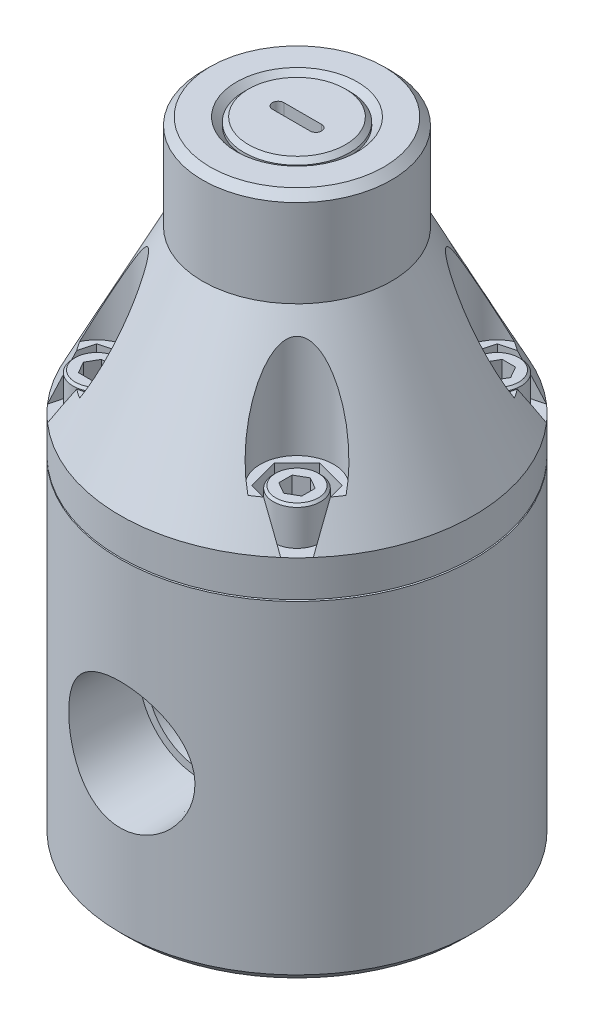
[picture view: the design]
ISO-10303-21;
HEADER;
FILE_DESCRIPTION(('STEP AP214'),'2;1');
FILE_NAME('part.step','',(''),(''),'','','');
FILE_SCHEMA(('AUTOMOTIVE_DESIGN { 1 0 10303 214 1 1 1 1 }'));
ENDSEC;
DATA;
#1=APPLICATION_CONTEXT('core data for automotive mechanical design processes');
#2=APPLICATION_PROTOCOL_DEFINITION('international standard','automotive_design',2000,#1);
#3=PRODUCT_CONTEXT('',#1,'mechanical');
#4=PRODUCT('Part','Part','',(#3));
#5=PRODUCT_RELATED_PRODUCT_CATEGORY('part','',(#4));
#6=PRODUCT_DEFINITION_FORMATION('','',#4);
#7=PRODUCT_DEFINITION_CONTEXT('part definition',#1,'design');
#8=PRODUCT_DEFINITION('design','',#6,#7);
#9=PRODUCT_DEFINITION_SHAPE('','',#8);
#10=(LENGTH_UNIT() NAMED_UNIT(*) SI_UNIT(.MILLI.,.METRE.));
#11=(NAMED_UNIT(*) PLANE_ANGLE_UNIT() SI_UNIT($,.RADIAN.));
#12=(NAMED_UNIT(*) SI_UNIT($,.STERADIAN.) SOLID_ANGLE_UNIT());
#13=UNCERTAINTY_MEASURE_WITH_UNIT(LENGTH_MEASURE(1.E-05),#10,'distance_accuracy_value','');
#14=(GEOMETRIC_REPRESENTATION_CONTEXT(3) GLOBAL_UNCERTAINTY_ASSIGNED_CONTEXT((#13)) GLOBAL_UNIT_ASSIGNED_CONTEXT((#10,
#11,#12)) REPRESENTATION_CONTEXT('',''));
#15=CARTESIAN_POINT('',(0.,0.,0.));
#16=DIRECTION('',(0.,0.,1.));
#17=DIRECTION('',(1.,0.,0.));
#18=AXIS2_PLACEMENT_3D('',#15,#16,#17);
#19=CARTESIAN_POINT('',(0.,62.23,0.));
#20=DIRECTION('',(0.,-1.,0.));
#21=DIRECTION('',(0.,0.,-1.));
#22=AXIS2_PLACEMENT_3D('',#19,#20,#21);
#23=CONICAL_SURFACE('',#22,29.718,0.471096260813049);
#24=CARTESIAN_POINT('',(-22.3373805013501,62.2298,-19.6011992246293));
#25=CARTESIAN_POINT('',(-22.2547645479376,62.7634166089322,-19.2832519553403));
#26=CARTESIAN_POINT('',(-22.1717744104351,63.29612059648,-18.9638646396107));
#27=CARTESIAN_POINT('',(-22.0049530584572,64.3594037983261,-18.3218531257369));
#28=CARTESIAN_POINT('',(-21.9211218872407,64.8899831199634,-17.9992290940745));
#29=CARTESIAN_POINT('',(-21.7525165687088,65.9487768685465,-17.3503519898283));
#30=CARTESIAN_POINT('',(-21.6677424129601,66.4769912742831,-17.0240988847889));
#31=CARTESIAN_POINT('',(-21.4971243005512,67.5307185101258,-16.367475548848));
#32=CARTESIAN_POINT('',(-21.4112802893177,68.0562312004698,-16.0371051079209));
#33=CARTESIAN_POINT('',(-21.3248419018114,68.5802,-15.7044472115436));
#34=B_SPLINE_CURVE_WITH_KNOTS('',3,(#24,#25,#26,#27,#28,#29,#30,#31,#32,#33),.UNSPECIFIED.,.F.,
.F.,(4,2,2,2,4),(0.,1.87988537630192,3.75967455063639,5.63948054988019,7.51938283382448),.UNSPECIFIED.);
#35=CARTESIAN_POINT('',(-22.3373495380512,62.23,-19.6010800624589));
#36=VERTEX_POINT('',#35);
#37=CARTESIAN_POINT('',(-21.324874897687,68.58,-15.7045741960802));
#38=VERTEX_POINT('',#37);
#39=EDGE_CURVE('E627',#36,#38,#34,.T.);
#40=ORIENTED_EDGE('',*,*,#39,.F.);
#41=CARTESIAN_POINT('',(0.,62.23,0.));
#42=DIRECTION('',(0.,-1.,0.));
#43=DIRECTION('',(0.,0.,-1.));
#44=AXIS2_PLACEMENT_3D('',#41,#42,#43);
#45=CIRCLE('',#44,29.718);
#46=CARTESIAN_POINT('',(-22.3373495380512,62.23,19.6010800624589));
#47=VERTEX_POINT('',#46);
#48=EDGE_CURVE('E935',#47,#36,#45,.T.);
#49=ORIENTED_EDGE('',*,*,#48,.F.);
#50=CARTESIAN_POINT('',(-21.3248419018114,68.5802,15.7044472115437));
#51=CARTESIAN_POINT('',(-21.4112802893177,68.0562312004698,16.0371051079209));
#52=CARTESIAN_POINT('',(-21.4971243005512,67.5307185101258,16.367475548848));
#53=CARTESIAN_POINT('',(-21.66774241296,66.4769912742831,17.024098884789));
#54=CARTESIAN_POINT('',(-21.7525165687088,65.9487768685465,17.3503519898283));
#55=CARTESIAN_POINT('',(-21.9211218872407,64.8899831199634,17.9992290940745));
#56=CARTESIAN_POINT('',(-22.0049530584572,64.3594037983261,18.3218531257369));
#57=CARTESIAN_POINT('',(-22.1717744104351,63.29612059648,18.9638646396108));
#58=CARTESIAN_POINT('',(-22.2547645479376,62.7634166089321,19.2832519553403));
#59=CARTESIAN_POINT('',(-22.3373805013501,62.2298,19.6011992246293));
#60=B_SPLINE_CURVE_WITH_KNOTS('',3,(#50,#51,#52,#53,#54,#55,#56,#57,#58,#59),.UNSPECIFIED.,.F.,
.F.,(4,2,2,2,4),(0.,1.87990228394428,3.75970828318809,5.63949745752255,7.51938283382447),.UNSPECIFIED.);
#61=CARTESIAN_POINT('',(-21.324874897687,68.58,15.7045741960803));
#62=VERTEX_POINT('',#61);
#63=EDGE_CURVE('E681',#62,#47,#60,.T.);
#64=ORIENTED_EDGE('',*,*,#63,.F.);
#65=CARTESIAN_POINT('',(0.,68.58,0.));
#66=DIRECTION('',(0.,1.,0.));
#67=DIRECTION('',(0.,0.,1.));
#68=AXIS2_PLACEMENT_3D('',#65,#66,#67);
#69=CIRCLE('',#68,26.4836542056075);
#70=CARTESIAN_POINT('',(-22.3908779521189,68.58,14.1432854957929));
#71=VERTEX_POINT('',#70);
#72=EDGE_CURVE('E1431',#62,#71,#69,.F.);
#73=ORIENTED_EDGE('',*,*,#72,.T.);
#74=CARTESIAN_POINT('',(-22.3909303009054,68.5798,14.143393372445));
#75=CARTESIAN_POINT('',(-22.350304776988,68.7350022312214,14.0596815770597));
#76=CARTESIAN_POINT('',(-22.3081630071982,68.89069928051,13.9776470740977));
#77=CARTESIAN_POINT('',(-22.2210302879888,69.2029732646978,13.8168553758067));
#78=CARTESIAN_POINT('',(-22.1760395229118,69.3595501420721,13.7380979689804));
#79=CARTESIAN_POINT('',(-22.0370947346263,69.8303500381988,13.5066666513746));
#80=CARTESIAN_POINT('',(-21.9391379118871,70.1457572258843,13.3587718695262));
#81=CARTESIAN_POINT('',(-21.7338262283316,70.7787217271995,13.0753567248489));
#82=CARTESIAN_POINT('',(-21.6264783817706,71.0962772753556,12.9398272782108));
#83=CARTESIAN_POINT('',(-21.4032338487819,71.7332404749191,12.6806046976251));
#84=CARTESIAN_POINT('',(-21.2873363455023,72.0526483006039,12.556912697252));
#85=CARTESIAN_POINT('',(-21.0470421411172,72.6946343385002,12.3204109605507));
#86=CARTESIAN_POINT('',(-20.9226003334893,73.0172202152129,12.2076680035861));
#87=CARTESIAN_POINT('',(-20.6663853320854,73.6632945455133,11.9936819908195));
#88=CARTESIAN_POINT('',(-20.5346119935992,73.9867830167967,11.8924391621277));
#89=CARTESIAN_POINT('',(-20.2641447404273,74.6342665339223,11.7013595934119));
#90=CARTESIAN_POINT('',(-20.1254503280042,74.9582616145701,11.6115236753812));
#91=CARTESIAN_POINT('',(-19.8414364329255,75.6062899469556,11.4433041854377));
#92=CARTESIAN_POINT('',(-19.6961171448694,75.9303231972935,11.3649202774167));
#93=CARTESIAN_POINT('',(-19.3211632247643,76.7476954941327,11.1817059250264));
#94=CARTESIAN_POINT('',(-19.0872302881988,77.2408247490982,11.0845248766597));
#95=CARTESIAN_POINT('',(-18.7249280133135,77.9784605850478,10.9599064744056));
#96=CARTESIAN_POINT('',(-18.6022415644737,78.2240315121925,10.9218885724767));
#97=CARTESIAN_POINT('',(-18.3529388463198,78.7141977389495,10.8531925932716));
#98=CARTESIAN_POINT('',(-18.2263228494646,78.9587931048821,10.8225140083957));
#99=CARTESIAN_POINT('',(-17.9690231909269,79.4465771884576,10.7688733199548));
#100=CARTESIAN_POINT('',(-17.8383410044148,79.6897663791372,10.7459084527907));
#101=CARTESIAN_POINT('',(-17.5726008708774,80.1743656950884,10.7081842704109));
#102=CARTESIAN_POINT('',(-17.4375433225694,80.4157759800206,10.693424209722));
#103=CARTESIAN_POINT('',(-17.1627429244,80.8961071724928,10.6727907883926));
#104=CARTESIAN_POINT('',(-17.0230031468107,81.1350295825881,10.6669117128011));
#105=CARTESIAN_POINT('',(-16.7382475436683,81.6097183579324,10.6649433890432));
#106=CARTESIAN_POINT('',(-16.5932325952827,81.8454852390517,10.6688525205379));
#107=CARTESIAN_POINT('',(-16.2968182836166,82.3133650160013,10.6877509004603));
#108=CARTESIAN_POINT('',(-16.1454043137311,82.5454676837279,10.7027669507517));
#109=CARTESIAN_POINT('',(-15.8354539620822,83.0038758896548,10.7457309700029));
#110=CARTESIAN_POINT('',(-15.6769137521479,83.2301782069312,10.7736859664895));
#111=CARTESIAN_POINT('',(-15.3515270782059,83.6741617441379,10.8451251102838));
#112=CARTESIAN_POINT('',(-15.1846866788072,83.8918490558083,10.8885980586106));
#113=CARTESIAN_POINT('',(-14.9269806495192,84.2084557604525,10.9683843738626));
#114=CARTESIAN_POINT('',(-14.839881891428,84.3122892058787,10.997391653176));
#115=CARTESIAN_POINT('',(-14.6629301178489,84.515808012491,11.0609509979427));
#116=CARTESIAN_POINT('',(-14.5730777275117,84.6154943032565,11.0955018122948));
#117=CARTESIAN_POINT('',(-14.3891167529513,84.8109037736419,11.1714874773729));
#118=CARTESIAN_POINT('',(-14.2949676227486,84.9065572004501,11.2130072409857));
#119=CARTESIAN_POINT('',(-14.1034347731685,85.0907355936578,11.3035808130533));
#120=CARTESIAN_POINT('',(-14.0060494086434,85.1792568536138,11.3526385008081));
#121=CARTESIAN_POINT('',(-13.7101223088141,85.429646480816,11.5123405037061));
#122=CARTESIAN_POINT('',(-13.5060546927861,85.5782916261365,11.6361944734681));
#123=CARTESIAN_POINT('',(-13.1996116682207,85.7493306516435,11.8507095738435));
#124=CARTESIAN_POINT('',(-13.0998509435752,85.7971000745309,11.9248690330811));
#125=CARTESIAN_POINT('',(-12.900706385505,85.873763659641,12.0829789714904));
#126=CARTESIAN_POINT('',(-12.8013223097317,85.9026733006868,12.1669213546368));
#127=CARTESIAN_POINT('',(-12.6053038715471,85.9385908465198,12.3437610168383));
#128=CARTESIAN_POINT('',(-12.5086917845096,85.9454540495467,12.4367133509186));
#129=CARTESIAN_POINT('',(-12.3223166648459,85.9359739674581,12.6281475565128));
#130=CARTESIAN_POINT('',(-12.2325552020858,85.9196253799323,12.7266306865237));
#131=CARTESIAN_POINT('',(-12.0684910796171,85.8677160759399,12.9184346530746));
#132=CARTESIAN_POINT('',(-11.9935403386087,85.8336265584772,13.0116153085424));
#133=CARTESIAN_POINT('',(-11.8522698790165,85.7502029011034,13.1975950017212));
#134=CARTESIAN_POINT('',(-11.7859543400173,85.7008614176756,13.290393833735));
#135=CARTESIAN_POINT('',(-11.6163662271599,85.5496530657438,13.5413620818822));
#136=CARTESIAN_POINT('',(-11.5214197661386,85.4357254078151,13.6978402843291));
#137=CARTESIAN_POINT('',(-11.3524385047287,85.1845941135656,14.0032728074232));
#138=CARTESIAN_POINT('',(-11.2784789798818,85.0473094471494,14.1521985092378));
#139=CARTESIAN_POINT('',(-11.1484302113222,84.7600134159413,14.44015441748));
#140=CARTESIAN_POINT('',(-11.0920802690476,84.6102339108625,14.5793027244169));
#141=CARTESIAN_POINT('',(-10.9925096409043,84.3006741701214,14.851149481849));
#142=CARTESIAN_POINT('',(-10.9493023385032,84.1408839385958,14.9838412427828));
#143=CARTESIAN_POINT('',(-10.8736636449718,83.8139640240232,15.2438249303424));
#144=CARTESIAN_POINT('',(-10.8412572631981,83.6468183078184,15.3711037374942));
#145=CARTESIAN_POINT('',(-10.7856662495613,83.307480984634,15.6206584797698));
#146=CARTESIAN_POINT('',(-10.7624784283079,83.1352911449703,15.7429361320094));
#147=CARTESIAN_POINT('',(-10.7205377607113,82.7552655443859,16.0051192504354));
#148=CARTESIAN_POINT('',(-10.7033691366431,82.5466647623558,16.1441638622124));
#149=CARTESIAN_POINT('',(-10.6786273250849,82.125493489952,16.4170496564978));
#150=CARTESIAN_POINT('',(-10.6710565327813,81.9129220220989,16.5508895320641));
#151=CARTESIAN_POINT('',(-10.664422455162,81.4846459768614,16.8140587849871));
#152=CARTESIAN_POINT('',(-10.6653663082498,81.2689389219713,16.9433842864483));
#153=CARTESIAN_POINT('',(-10.674967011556,80.8352423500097,17.1978874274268));
#154=CARTESIAN_POINT('',(-10.6836247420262,80.6172525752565,17.323064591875));
#155=CARTESIAN_POINT('',(-10.7080782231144,80.178919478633,17.5699535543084));
#156=CARTESIAN_POINT('',(-10.7238938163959,79.9585712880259,17.691654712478));
#157=CARTESIAN_POINT('',(-10.7622068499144,79.516512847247,17.9314908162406));
#158=CARTESIAN_POINT('',(-10.7847047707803,79.2948025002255,18.0496255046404));
#159=CARTESIAN_POINT('',(-10.8616544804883,78.628245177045,18.3989144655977));
#160=CARTESIAN_POINT('',(-10.9255713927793,78.1818168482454,18.6250403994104));
#161=CARTESIAN_POINT('',(-11.0664102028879,77.3479438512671,19.0346218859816));
#162=CARTESIAN_POINT('',(-11.1403619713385,76.9607742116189,19.2196861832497));
#163=CARTESIAN_POINT('',(-11.3050181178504,76.1856258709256,19.5805572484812));
#164=CARTESIAN_POINT('',(-11.3957241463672,75.7976470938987,19.7563631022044));
#165=CARTESIAN_POINT('',(-11.5935742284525,75.0216151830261,20.0985507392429));
#166=CARTESIAN_POINT('',(-11.7007221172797,74.6335620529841,20.264930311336));
#167=CARTESIAN_POINT('',(-11.9313879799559,73.8581881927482,20.5877481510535));
#168=CARTESIAN_POINT('',(-12.0549056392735,73.470867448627,20.7441866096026));
#169=CARTESIAN_POINT('',(-12.3163714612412,72.7038997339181,21.0439307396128));
#170=CARTESIAN_POINT('',(-12.4540552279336,72.3242296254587,21.1874073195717));
#171=CARTESIAN_POINT('',(-12.7458005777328,71.5671030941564,21.4629534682));
#172=CARTESIAN_POINT('',(-12.8998598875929,71.1896463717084,21.5950246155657));
#173=CARTESIAN_POINT('',(-13.2250025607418,70.4376533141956,21.8464430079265));
#174=CARTESIAN_POINT('',(-13.396090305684,70.0631177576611,21.9657869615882));
#175=CARTESIAN_POINT('',(-13.6660711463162,69.5043911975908,22.1338540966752));
#176=CARTESIAN_POINT('',(-13.7583155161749,69.3186135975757,22.1880644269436));
#177=CARTESIAN_POINT('',(-13.9473861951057,68.9482602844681,22.2925349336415));
#178=CARTESIAN_POINT('',(-14.044212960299,68.7636846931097,22.3427947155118));
#179=CARTESIAN_POINT('',(-14.1433933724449,68.5798000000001,22.3909303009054));
#180=B_SPLINE_CURVE_WITH_KNOTS('',3,(#74,#75,#76,#77,#78,#79,#80,#81,#82,#83,#84,#85,#86,#87,
#88,#89,#90,#91,#92,#93,#94,#95,#96,#97,#98,#99,#100,#101,#102,#103,#104,#105,#106,#107,#108,
#109,#110,#111,#112,#113,#114,#115,#116,#117,#118,#119,#120,#121,#122,#123,#124,#125,#126,#127,
#128,#129,#130,#131,#132,#133,#134,#135,#136,#137,#138,#139,#140,#141,#142,#143,#144,#145,#146,
#147,#148,#149,#150,#151,#152,#153,#154,#155,#156,#157,#158,#159,#160,#161,#162,#163,#164,#165,
#166,#167,#168,#169,#170,#171,#172,#173,#174,#175,#176,#177,#178,#179),.UNSPECIFIED.,.F.,.F.,(4,
2,2,2,2,2,2,2,2,2,2,2,2,2,2,2,2,2,2,2,2,2,2,2,2,2,2,2,2,2,2,2,2,2,2,2,2,2,2,2,2,2,2,2,2,2,2,2,2,
2,2,2,4),(0.,0.542840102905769,1.08564511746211,2.17085376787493,3.25525867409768,
4.33976732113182,5.43052218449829,6.5212985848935,7.61215354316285,8.70297647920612,
10.3650975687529,11.196398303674,12.027641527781,12.8585866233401,13.6894562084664,
14.5197908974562,15.3499881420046,16.1821952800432,17.014854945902,17.8469149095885,
18.2625409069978,18.6780732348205,19.0990950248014,19.5203342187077,20.354755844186,
20.7529146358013,21.1507462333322,21.5511837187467,21.9517126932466,22.32334462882,
22.6951557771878,23.3381727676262,23.9834677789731,24.6186994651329,25.2545758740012,
25.8919145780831,26.5290325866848,27.2825500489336,28.0362555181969,28.7905929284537,
29.5450164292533,30.3015442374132,31.0581264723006,32.5707579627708,33.8767149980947,
35.1828007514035,36.4891916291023,37.7955574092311,39.0808873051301,40.3660390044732,
41.6515222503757,42.2946005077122,42.9377429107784),.UNSPECIFIED.);
#181=CARTESIAN_POINT('',(-14.1432854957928,68.58,22.390877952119));
#182=VERTEX_POINT('',#181);
#183=EDGE_CURVE('E1425',#71,#182,#180,.T.);
#184=ORIENTED_EDGE('',*,*,#183,.T.);
#185=CARTESIAN_POINT('',(-15.7045741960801,68.58,21.3248748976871));
#186=VERTEX_POINT('',#185);
#187=EDGE_CURVE('E1358',#182,#186,#69,.F.);
#188=ORIENTED_EDGE('',*,*,#187,.T.);
#189=CARTESIAN_POINT('',(-19.6011992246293,62.2298,22.3373805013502));
#190=CARTESIAN_POINT('',(-19.2832519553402,62.7634166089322,22.2547645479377));
#191=CARTESIAN_POINT('',(-18.9638646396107,63.29612059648,22.1717744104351));
#192=CARTESIAN_POINT('',(-18.3218531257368,64.3594037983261,22.0049530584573));
#193=CARTESIAN_POINT('',(-17.9992290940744,64.8899831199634,21.9211218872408));
#194=CARTESIAN_POINT('',(-17.3503519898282,65.9487768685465,21.7525165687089));
#195=CARTESIAN_POINT('',(-17.0240988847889,66.4769912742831,21.6677424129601));
#196=CARTESIAN_POINT('',(-16.3674755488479,67.5307185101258,21.4971243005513));
#197=CARTESIAN_POINT('',(-16.0371051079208,68.0562312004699,21.4112802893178));
#198=CARTESIAN_POINT('',(-15.7044472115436,68.5802,21.3248419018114));
#199=B_SPLINE_CURVE_WITH_KNOTS('',3,(#189,#190,#191,#192,#193,#194,#195,#196,#197,#198),
.UNSPECIFIED.,.F.,.F.,(4,2,2,2,4),(0.,1.87988537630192,3.75967455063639,5.63948054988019,
7.51938283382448),.UNSPECIFIED.);
#200=CARTESIAN_POINT('',(-19.6010800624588,62.23,22.3373495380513));
#201=VERTEX_POINT('',#200);
#202=EDGE_CURVE('E674',#201,#186,#199,.T.);
#203=ORIENTED_EDGE('',*,*,#202,.F.);
#204=CARTESIAN_POINT('',(19.601080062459,62.23,22.3373495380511));
#205=VERTEX_POINT('',#204);
#206=EDGE_CURVE('E948',#205,#201,#45,.T.);
#207=ORIENTED_EDGE('',*,*,#206,.F.);
#208=CARTESIAN_POINT('',(15.7044472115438,68.5802,21.3248419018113));
#209=CARTESIAN_POINT('',(16.037105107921,68.0562312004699,21.4112802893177));
#210=CARTESIAN_POINT('',(16.3674755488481,67.5307185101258,21.4971243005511));
#211=CARTESIAN_POINT('',(17.024098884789,66.4769912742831,21.66774241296));
#212=CARTESIAN_POINT('',(17.3503519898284,65.9487768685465,21.7525165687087));
#213=CARTESIAN_POINT('',(17.9992290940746,64.8899831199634,21.9211218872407));
#214=CARTESIAN_POINT('',(18.321853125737,64.3594037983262,22.0049530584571));
#215=CARTESIAN_POINT('',(18.9638646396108,63.29612059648,22.171774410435));
#216=CARTESIAN_POINT('',(19.2832519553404,62.7634166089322,22.2547645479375));
#217=CARTESIAN_POINT('',(19.6011992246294,62.2298,22.33738050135));
#218=B_SPLINE_CURVE_WITH_KNOTS('',3,(#208,#209,#210,#211,#212,#213,#214,#215,#216,#217),
.UNSPECIFIED.,.F.,.F.,(4,2,2,2,4),(0.,1.87990228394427,3.75970828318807,5.63949745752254,
7.51938283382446),.UNSPECIFIED.);
#219=CARTESIAN_POINT('',(15.7045741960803,68.58,21.3248748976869));
#220=VERTEX_POINT('',#219);
#221=EDGE_CURVE('E712',#220,#205,#218,.T.);
#222=ORIENTED_EDGE('',*,*,#221,.F.);
#223=CARTESIAN_POINT('',(0.,68.58,0.));
#224=DIRECTION('',(0.,1.,0.));
#225=DIRECTION('',(0.,0.,1.));
#226=AXIS2_PLACEMENT_3D('',#223,#224,#225);
#227=CIRCLE('',#226,26.4836542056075);
#228=CARTESIAN_POINT('',(14.143285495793,68.58,22.3908779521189));
#229=VERTEX_POINT('',#228);
#230=EDGE_CURVE('E979',#220,#229,#227,.F.);
#231=ORIENTED_EDGE('',*,*,#230,.T.);
#232=CARTESIAN_POINT('',(14.1433933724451,68.5798,22.3909303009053));
#233=CARTESIAN_POINT('',(14.0596815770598,68.7350022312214,22.3503047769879));
#234=CARTESIAN_POINT('',(13.9776470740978,68.89069928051,22.3081630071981));
#235=CARTESIAN_POINT('',(13.8168553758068,69.2029732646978,22.2210302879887));
#236=CARTESIAN_POINT('',(13.7380979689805,69.3595501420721,22.1760395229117));
#237=CARTESIAN_POINT('',(13.5066666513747,69.8303500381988,22.0370947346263));
#238=CARTESIAN_POINT('',(13.3587718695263,70.1457572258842,21.939137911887));
#239=CARTESIAN_POINT('',(13.075356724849,70.7787217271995,21.7338262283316));
#240=CARTESIAN_POINT('',(12.9398272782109,71.0962772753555,21.6264783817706));
#241=CARTESIAN_POINT('',(12.6806046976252,71.7332404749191,21.4032338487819));
#242=CARTESIAN_POINT('',(12.5569126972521,72.0526483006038,21.2873363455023));
#243=CARTESIAN_POINT('',(12.3204109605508,72.6946343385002,21.0470421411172));
#244=CARTESIAN_POINT('',(12.2076680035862,73.0172202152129,20.9226003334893));
#245=CARTESIAN_POINT('',(11.9936819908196,73.6632945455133,20.6663853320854));
#246=CARTESIAN_POINT('',(11.8924391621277,73.9867830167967,20.5346119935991));
#247=CARTESIAN_POINT('',(11.7013595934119,74.6342665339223,20.2641447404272));
#248=CARTESIAN_POINT('',(11.6115236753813,74.9582616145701,20.1254503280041));
#249=CARTESIAN_POINT('',(11.4433041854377,75.6062899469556,19.8414364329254));
#250=CARTESIAN_POINT('',(11.3649202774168,75.9303231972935,19.6961171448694));
#251=CARTESIAN_POINT('',(11.1817059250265,76.7476954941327,19.3211632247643));
#252=CARTESIAN_POINT('',(11.0845248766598,77.2408247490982,19.0872302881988));
#253=CARTESIAN_POINT('',(10.9599064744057,77.9784605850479,18.7249280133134));
#254=CARTESIAN_POINT('',(10.9218885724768,78.2240315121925,18.6022415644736));
#255=CARTESIAN_POINT('',(10.8531925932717,78.7141977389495,18.3529388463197));
#256=CARTESIAN_POINT('',(10.8225140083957,78.9587931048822,18.2263228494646));
#257=CARTESIAN_POINT('',(10.7688733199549,79.4465771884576,17.9690231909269));
#258=CARTESIAN_POINT('',(10.7459084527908,79.6897663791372,17.8383410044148));
#259=CARTESIAN_POINT('',(10.7081842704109,80.1743656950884,17.5726008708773));
#260=CARTESIAN_POINT('',(10.6934242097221,80.4157759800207,17.4375433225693));
#261=CARTESIAN_POINT('',(10.6727907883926,80.8961071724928,17.1627429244));
#262=CARTESIAN_POINT('',(10.6669117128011,81.1350295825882,17.0230031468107));
#263=CARTESIAN_POINT('',(10.6649433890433,81.6097183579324,16.7382475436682));
#264=CARTESIAN_POINT('',(10.668852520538,81.8454852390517,16.5932325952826));
#265=CARTESIAN_POINT('',(10.6877509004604,82.3133650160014,16.2968182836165));
#266=CARTESIAN_POINT('',(10.7027669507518,82.545467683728,16.1454043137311));
#267=CARTESIAN_POINT('',(10.745730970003,83.0038758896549,15.8354539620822));
#268=CARTESIAN_POINT('',(10.7736859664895,83.2301782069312,15.6769137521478));
#269=CARTESIAN_POINT('',(10.8451251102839,83.6741617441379,15.3515270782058));
#270=CARTESIAN_POINT('',(10.8885980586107,83.8918490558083,15.1846866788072));
#271=CARTESIAN_POINT('',(10.9683843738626,84.2084557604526,14.9269806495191));
#272=CARTESIAN_POINT('',(10.997391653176,84.3122892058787,14.8398818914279));
#273=CARTESIAN_POINT('',(11.0609509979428,84.515808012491,14.6629301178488));
#274=CARTESIAN_POINT('',(11.0955018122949,84.6154943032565,14.5730777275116));
#275=CARTESIAN_POINT('',(11.171487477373,84.8109037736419,14.3891167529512));
#276=CARTESIAN_POINT('',(11.2130072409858,84.9065572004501,14.2949676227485));
#277=CARTESIAN_POINT('',(11.3035808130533,85.0907355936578,14.1034347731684));
#278=CARTESIAN_POINT('',(11.3526385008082,85.1792568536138,14.0060494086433));
#279=CARTESIAN_POINT('',(11.5123405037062,85.4296464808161,13.710122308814));
#280=CARTESIAN_POINT('',(11.6361944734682,85.5782916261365,13.506054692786));
#281=CARTESIAN_POINT('',(11.8507095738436,85.7493306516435,13.1996116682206));
#282=CARTESIAN_POINT('',(11.9248690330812,85.797100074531,13.0998509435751));
#283=CARTESIAN_POINT('',(12.0829789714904,85.873763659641,12.9007063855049));
#284=CARTESIAN_POINT('',(12.1669213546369,85.9026733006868,12.8013223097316));
#285=CARTESIAN_POINT('',(12.3437610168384,85.9385908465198,12.605303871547));
#286=CARTESIAN_POINT('',(12.4367133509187,85.9454540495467,12.5086917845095));
#287=CARTESIAN_POINT('',(12.6281475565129,85.9359739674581,12.3223166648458));
#288=CARTESIAN_POINT('',(12.7266306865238,85.9196253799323,12.2325552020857));
#289=CARTESIAN_POINT('',(12.9184346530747,85.8677160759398,12.068491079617));
#290=CARTESIAN_POINT('',(13.0116153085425,85.8336265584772,11.9935403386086));
#291=CARTESIAN_POINT('',(13.1975950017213,85.7502029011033,11.8522698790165));
#292=CARTESIAN_POINT('',(13.2903938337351,85.7008614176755,11.7859543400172));
#293=CARTESIAN_POINT('',(13.5413620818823,85.5496530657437,11.6163662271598));
#294=CARTESIAN_POINT('',(13.6978402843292,85.435725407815,11.5214197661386));
#295=CARTESIAN_POINT('',(14.0032728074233,85.1845941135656,11.3524385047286));
#296=CARTESIAN_POINT('',(14.1521985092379,85.0473094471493,11.2784789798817));
#297=CARTESIAN_POINT('',(14.4401544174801,84.7600134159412,11.1484302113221));
#298=CARTESIAN_POINT('',(14.579302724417,84.6102339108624,11.0920802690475));
#299=CARTESIAN_POINT('',(14.8511494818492,84.3006741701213,10.9925096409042));
#300=CARTESIAN_POINT('',(14.983841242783,84.1408839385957,10.9493023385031));
#301=CARTESIAN_POINT('',(15.2438249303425,83.813964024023,10.8736636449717));
#302=CARTESIAN_POINT('',(15.3711037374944,83.6468183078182,10.841257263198));
#303=CARTESIAN_POINT('',(15.62065847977,83.3074809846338,10.7856662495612));
#304=CARTESIAN_POINT('',(15.7429361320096,83.1352911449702,10.7624784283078));
#305=CARTESIAN_POINT('',(16.0051192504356,82.7552655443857,10.7205377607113));
#306=CARTESIAN_POINT('',(16.1441638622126,82.5466647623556,10.703369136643));
#307=CARTESIAN_POINT('',(16.417049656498,82.1254934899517,10.6786273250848));
#308=CARTESIAN_POINT('',(16.5508895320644,81.9129220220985,10.6710565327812));
#309=CARTESIAN_POINT('',(16.8140587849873,81.4846459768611,10.6644224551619));
#310=CARTESIAN_POINT('',(16.9433842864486,81.2689389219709,10.6653663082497));
#311=CARTESIAN_POINT('',(17.1978874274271,80.8352423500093,10.674967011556));
#312=CARTESIAN_POINT('',(17.3230645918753,80.6172525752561,10.6836247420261));
#313=CARTESIAN_POINT('',(17.5699535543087,80.1789194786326,10.7080782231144));
#314=CARTESIAN_POINT('',(17.6916547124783,79.9585712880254,10.7238938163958));
#315=CARTESIAN_POINT('',(17.9314908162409,79.5165128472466,10.7622068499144));
#316=CARTESIAN_POINT('',(18.0496255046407,79.294802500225,10.7847047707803));
#317=CARTESIAN_POINT('',(18.398914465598,78.6282451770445,10.8616544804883));
#318=CARTESIAN_POINT('',(18.6250403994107,78.1818168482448,10.9255713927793));
#319=CARTESIAN_POINT('',(19.0346218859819,77.3479438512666,11.0664102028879));
#320=CARTESIAN_POINT('',(19.21968618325,76.9607742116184,11.1403619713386));
#321=CARTESIAN_POINT('',(19.5805572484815,76.1856258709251,11.3050181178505));
#322=CARTESIAN_POINT('',(19.7563631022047,75.7976470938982,11.3957241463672));
#323=CARTESIAN_POINT('',(20.0985507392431,75.0216151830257,11.5935742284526));
#324=CARTESIAN_POINT('',(20.2649303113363,74.6335620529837,11.7007221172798));
#325=CARTESIAN_POINT('',(20.5877481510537,73.8581881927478,11.9313879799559));
#326=CARTESIAN_POINT('',(20.7441866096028,73.4708674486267,12.0549056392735));
#327=CARTESIAN_POINT('',(21.0439307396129,72.7038997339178,12.3163714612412));
#328=CARTESIAN_POINT('',(21.1874073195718,72.3242296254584,12.4540552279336));
#329=CARTESIAN_POINT('',(21.4629534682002,71.5671030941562,12.7458005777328));
#330=CARTESIAN_POINT('',(21.5950246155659,71.1896463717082,12.8998598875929));
#331=CARTESIAN_POINT('',(21.8464430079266,70.4376533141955,13.2250025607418));
#332=CARTESIAN_POINT('',(21.9657869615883,70.0631177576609,13.396090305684));
#333=CARTESIAN_POINT('',(22.1338540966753,69.5043911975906,13.6660711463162));
#334=CARTESIAN_POINT('',(22.1880644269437,69.3186135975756,13.7583155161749));
#335=CARTESIAN_POINT('',(22.2925349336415,68.948260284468,13.9473861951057));
#336=CARTESIAN_POINT('',(22.3427947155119,68.7636846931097,14.0442129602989));
#337=CARTESIAN_POINT('',(22.3909303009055,68.5798,14.1433933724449));
#338=B_SPLINE_CURVE_WITH_KNOTS('',3,(#232,#233,#234,#235,#236,#237,#238,#239,#240,#241,#242,
#243,#244,#245,#246,#247,#248,#249,#250,#251,#252,#253,#254,#255,#256,#257,#258,#259,#260,#261,
#262,#263,#264,#265,#266,#267,#268,#269,#270,#271,#272,#273,#274,#275,#276,#277,#278,#279,#280,
#281,#282,#283,#284,#285,#286,#287,#288,#289,#290,#291,#292,#293,#294,#295,#296,#297,#298,#299,
#300,#301,#302,#303,#304,#305,#306,#307,#308,#309,#310,#311,#312,#313,#314,#315,#316,#317,#318,
#319,#320,#321,#322,#323,#324,#325,#326,#327,#328,#329,#330,#331,#332,#333,#334,#335,#336,#337),
.UNSPECIFIED.,.F.,.F.,(4,2,2,2,2,2,2,2,2,2,2,2,2,2,2,2,2,2,2,2,2,2,2,2,2,2,2,2,2,2,2,2,2,2,2,2,
2,2,2,2,2,2,2,2,2,2,2,2,2,2,2,2,4),(0.,0.542840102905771,1.08564511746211,2.17085376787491,
3.25525867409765,4.3397673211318,5.43052218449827,6.52129858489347,7.61215354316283,
8.7029764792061,10.3650975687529,11.196398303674,12.0276415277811,12.8585866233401,
13.6894562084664,14.5197908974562,15.3499881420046,16.1821952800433,17.0148549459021,
17.8469149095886,18.2625409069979,18.6780732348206,19.0990950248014,19.5203342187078,
20.3547558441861,20.7529146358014,21.1507462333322,21.5511837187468,21.9517126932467,
22.3233446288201,22.6951557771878,23.3381727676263,23.9834677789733,24.618699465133,
25.2545758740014,25.8919145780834,26.529032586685,27.2825500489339,28.0362555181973,
28.7905929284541,29.5450164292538,30.3015442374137,31.0581264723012,32.5707579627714,
33.8767149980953,35.182800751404,36.4891916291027,37.7955574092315,39.0808873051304,
40.3660390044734,41.6515222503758,42.2946005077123,42.9377429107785),.UNSPECIFIED.);
#339=CARTESIAN_POINT('',(22.390877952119,68.58,14.1432854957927));
#340=VERTEX_POINT('',#339);
#341=EDGE_CURVE('E1432',#229,#340,#338,.T.);
#342=ORIENTED_EDGE('',*,*,#341,.T.);
#343=CARTESIAN_POINT('',(21.3248748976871,68.58,15.7045741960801));
#344=VERTEX_POINT('',#343);
#345=EDGE_CURVE('E989',#340,#344,#227,.F.);
#346=ORIENTED_EDGE('',*,*,#345,.T.);
#347=CARTESIAN_POINT('',(22.3373805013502,62.2298,19.6011992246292));
#348=CARTESIAN_POINT('',(22.2547645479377,62.7634166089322,19.2832519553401));
#349=CARTESIAN_POINT('',(22.1717744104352,63.29612059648,18.9638646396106));
#350=CARTESIAN_POINT('',(22.0049530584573,64.3594037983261,18.3218531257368));
#351=CARTESIAN_POINT('',(21.9211218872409,64.8899831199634,17.9992290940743));
#352=CARTESIAN_POINT('',(21.752516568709,65.9487768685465,17.3503519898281));
#353=CARTESIAN_POINT('',(21.6677424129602,66.4769912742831,17.0240988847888));
#354=CARTESIAN_POINT('',(21.4971243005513,67.5307185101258,16.3674755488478));
#355=CARTESIAN_POINT('',(21.4112802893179,68.0562312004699,16.0371051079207));
#356=CARTESIAN_POINT('',(21.3248419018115,68.5802,15.7044472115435));
#357=B_SPLINE_CURVE_WITH_KNOTS('',3,(#347,#348,#349,#350,#351,#352,#353,#354,#355,#356),
.UNSPECIFIED.,.F.,.F.,(4,2,2,2,4),(0.,1.87988537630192,3.75967455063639,5.63948054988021,
7.51938283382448),.UNSPECIFIED.);
#358=CARTESIAN_POINT('',(22.3373495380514,62.23,19.6010800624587));
#359=VERTEX_POINT('',#358);
#360=EDGE_CURVE('E725',#359,#344,#357,.T.);
#361=ORIENTED_EDGE('',*,*,#360,.F.);
#362=CARTESIAN_POINT('',(22.3373495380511,62.23,-19.6010800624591));
#363=VERTEX_POINT('',#362);
#364=EDGE_CURVE('E854',#363,#359,#45,.T.);
#365=ORIENTED_EDGE('',*,*,#364,.F.);
#366=CARTESIAN_POINT('',(21.3248419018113,68.5802,-15.7044472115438));
#367=CARTESIAN_POINT('',(21.4112802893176,68.0562312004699,-16.037105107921));
#368=CARTESIAN_POINT('',(21.4971243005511,67.5307185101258,-16.3674755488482));
#369=CARTESIAN_POINT('',(21.6677424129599,66.4769912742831,-17.0240988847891));
#370=CARTESIAN_POINT('',(21.7525165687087,65.9487768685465,-17.3503519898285));
#371=CARTESIAN_POINT('',(21.9211218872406,64.8899831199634,-17.9992290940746));
#372=CARTESIAN_POINT('',(22.004953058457,64.3594037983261,-18.3218531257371));
#373=CARTESIAN_POINT('',(22.1717744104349,63.29612059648,-18.9638646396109));
#374=CARTESIAN_POINT('',(22.2547645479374,62.7634166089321,-19.2832519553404));
#375=CARTESIAN_POINT('',(22.3373805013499,62.2298,-19.6011992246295));
#376=B_SPLINE_CURVE_WITH_KNOTS('',3,(#366,#367,#368,#369,#370,#371,#372,#373,#374,#375),
.UNSPECIFIED.,.F.,.F.,(4,2,2,2,4),(0.,1.87990228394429,3.75970828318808,5.63949745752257,
7.51938283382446),.UNSPECIFIED.);
#377=CARTESIAN_POINT('',(21.3248748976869,68.58,-15.7045741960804));
#378=VERTEX_POINT('',#377);
#379=EDGE_CURVE('E774',#378,#363,#376,.T.);
#380=ORIENTED_EDGE('',*,*,#379,.F.);
#381=CARTESIAN_POINT('',(0.,68.58,0.));
#382=DIRECTION('',(0.,1.,0.));
#383=DIRECTION('',(0.,0.,1.));
#384=AXIS2_PLACEMENT_3D('',#381,#382,#383);
#385=CIRCLE('',#384,26.4836542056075);
#386=CARTESIAN_POINT('',(22.3908779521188,68.58,-14.1432854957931));
#387=VERTEX_POINT('',#386);
#388=EDGE_CURVE('E977',#378,#387,#385,.F.);
#389=ORIENTED_EDGE('',*,*,#388,.T.);
#390=CARTESIAN_POINT('',(22.3909303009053,68.5798000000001,-14.1433933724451));
#391=CARTESIAN_POINT('',(22.3503047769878,68.7350022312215,-14.0596815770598));
#392=CARTESIAN_POINT('',(22.3081630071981,68.8906992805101,-13.9776470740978));
#393=CARTESIAN_POINT('',(22.2210302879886,69.2029732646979,-13.8168553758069));
#394=CARTESIAN_POINT('',(22.1760395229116,69.3595501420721,-13.7380979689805));
#395=CARTESIAN_POINT('',(22.0370947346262,69.8303500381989,-13.5066666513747));
#396=CARTESIAN_POINT('',(21.939137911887,70.1457572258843,-13.3587718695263));
#397=CARTESIAN_POINT('',(21.7338262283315,70.7787217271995,-13.075356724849));
#398=CARTESIAN_POINT('',(21.6264783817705,71.0962772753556,-12.9398272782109));
#399=CARTESIAN_POINT('',(21.4032338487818,71.7332404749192,-12.6806046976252));
#400=CARTESIAN_POINT('',(21.2873363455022,72.0526483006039,-12.5569126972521));
#401=CARTESIAN_POINT('',(21.0470421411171,72.6946343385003,-12.3204109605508));
#402=CARTESIAN_POINT('',(20.9226003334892,73.017220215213,-12.2076680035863));
#403=CARTESIAN_POINT('',(20.6663853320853,73.6632945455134,-11.9936819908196));
#404=CARTESIAN_POINT('',(20.5346119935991,73.9867830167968,-11.8924391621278));
#405=CARTESIAN_POINT('',(20.2641447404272,74.6342665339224,-11.701359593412));
#406=CARTESIAN_POINT('',(20.1254503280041,74.9582616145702,-11.6115236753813));
#407=CARTESIAN_POINT('',(19.8414364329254,75.6062899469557,-11.4433041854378));
#408=CARTESIAN_POINT('',(19.6961171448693,75.9303231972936,-11.3649202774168));
#409=CARTESIAN_POINT('',(19.3211632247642,76.7476954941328,-11.1817059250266));
#410=CARTESIAN_POINT('',(19.0872302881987,77.2408247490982,-11.0845248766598));
#411=CARTESIAN_POINT('',(18.7249280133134,77.9784605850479,-10.9599064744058));
#412=CARTESIAN_POINT('',(18.6022415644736,78.2240315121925,-10.9218885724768));
#413=CARTESIAN_POINT('',(18.3529388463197,78.7141977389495,-10.8531925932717));
#414=CARTESIAN_POINT('',(18.2263228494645,78.9587931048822,-10.8225140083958));
#415=CARTESIAN_POINT('',(17.9690231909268,79.4465771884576,-10.7688733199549));
#416=CARTESIAN_POINT('',(17.8383410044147,79.6897663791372,-10.7459084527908));
#417=CARTESIAN_POINT('',(17.5726008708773,80.1743656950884,-10.708184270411));
#418=CARTESIAN_POINT('',(17.4375433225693,80.4157759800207,-10.6934242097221));
#419=CARTESIAN_POINT('',(17.1627429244,80.8961071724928,-10.6727907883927));
#420=CARTESIAN_POINT('',(17.0230031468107,81.1350295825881,-10.6669117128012));
#421=CARTESIAN_POINT('',(16.7382475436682,81.6097183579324,-10.6649433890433));
#422=CARTESIAN_POINT('',(16.5932325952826,81.8454852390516,-10.668852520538));
#423=CARTESIAN_POINT('',(16.2968182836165,82.3133650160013,-10.6877509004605));
#424=CARTESIAN_POINT('',(16.1454043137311,82.5454676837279,-10.7027669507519));
#425=CARTESIAN_POINT('',(15.8354539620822,83.0038758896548,-10.745730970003));
#426=CARTESIAN_POINT('',(15.6769137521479,83.2301782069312,-10.7736859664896));
#427=CARTESIAN_POINT('',(15.3515270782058,83.6741617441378,-10.8451251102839));
#428=CARTESIAN_POINT('',(15.1846866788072,83.8918490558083,-10.8885980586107));
#429=CARTESIAN_POINT('',(14.9269806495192,84.2084557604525,-10.9683843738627));
#430=CARTESIAN_POINT('',(14.8398818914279,84.3122892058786,-10.9973916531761));
#431=CARTESIAN_POINT('',(14.6629301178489,84.5158080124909,-11.0609509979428));
#432=CARTESIAN_POINT('',(14.5730777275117,84.6154943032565,-11.0955018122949));
#433=CARTESIAN_POINT('',(14.3891167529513,84.8109037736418,-11.171487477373));
#434=CARTESIAN_POINT('',(14.2949676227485,84.90655720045,-11.2130072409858));
#435=CARTESIAN_POINT('',(14.1034347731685,85.0907355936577,-11.3035808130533));
#436=CARTESIAN_POINT('',(14.0060494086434,85.1792568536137,-11.3526385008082));
#437=CARTESIAN_POINT('',(13.7101223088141,85.429646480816,-11.5123405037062));
#438=CARTESIAN_POINT('',(13.5060546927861,85.5782916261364,-11.6361944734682));
#439=CARTESIAN_POINT('',(13.1996116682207,85.7493306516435,-11.8507095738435));
#440=CARTESIAN_POINT('',(13.0998509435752,85.7971000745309,-11.9248690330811));
#441=CARTESIAN_POINT('',(12.9007063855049,85.873763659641,-12.0829789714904));
#442=CARTESIAN_POINT('',(12.8013223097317,85.9026733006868,-12.1669213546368));
#443=CARTESIAN_POINT('',(12.6053038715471,85.9385908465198,-12.3437610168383));
#444=CARTESIAN_POINT('',(12.5086917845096,85.9454540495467,-12.4367133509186));
#445=CARTESIAN_POINT('',(12.3223166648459,85.9359739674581,-12.6281475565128));
#446=CARTESIAN_POINT('',(12.2325552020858,85.9196253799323,-12.7266306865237));
#447=CARTESIAN_POINT('',(12.0684910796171,85.8677160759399,-12.9184346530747));
#448=CARTESIAN_POINT('',(11.9935403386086,85.8336265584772,-13.0116153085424));
#449=CARTESIAN_POINT('',(11.8522698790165,85.7502029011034,-13.1975950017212));
#450=CARTESIAN_POINT('',(11.7859543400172,85.7008614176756,-13.290393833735));
#451=CARTESIAN_POINT('',(11.6163662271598,85.5496530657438,-13.5413620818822));
#452=CARTESIAN_POINT('',(11.5214197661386,85.4357254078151,-13.6978402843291));
#453=CARTESIAN_POINT('',(11.3524385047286,85.1845941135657,-14.0032728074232));
#454=CARTESIAN_POINT('',(11.2784789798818,85.0473094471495,-14.1521985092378));
#455=CARTESIAN_POINT('',(11.1484302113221,84.7600134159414,-14.4401544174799));
#456=CARTESIAN_POINT('',(11.0920802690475,84.6102339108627,-14.5793027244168));
#457=CARTESIAN_POINT('',(10.9925096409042,84.3006741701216,-14.851149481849));
#458=CARTESIAN_POINT('',(10.9493023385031,84.140883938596,-14.9838412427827));
#459=CARTESIAN_POINT('',(10.8736636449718,83.8139640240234,-15.2438249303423));
#460=CARTESIAN_POINT('',(10.841257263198,83.6468183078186,-15.3711037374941));
#461=CARTESIAN_POINT('',(10.7856662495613,83.3074809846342,-15.6206584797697));
#462=CARTESIAN_POINT('',(10.7624784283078,83.1352911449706,-15.7429361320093));
#463=CARTESIAN_POINT('',(10.7205377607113,82.7552655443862,-16.0051192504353));
#464=CARTESIAN_POINT('',(10.703369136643,82.5466647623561,-16.1441638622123));
#465=CARTESIAN_POINT('',(10.6786273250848,82.1254934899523,-16.4170496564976));
#466=CARTESIAN_POINT('',(10.6710565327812,81.9129220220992,-16.550889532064));
#467=CARTESIAN_POINT('',(10.6644224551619,81.4846459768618,-16.814058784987));
#468=CARTESIAN_POINT('',(10.6653663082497,81.2689389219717,-16.9433842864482));
#469=CARTESIAN_POINT('',(10.6749670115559,80.8352423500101,-17.1978874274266));
#470=CARTESIAN_POINT('',(10.683624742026,80.6172525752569,-17.3230645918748));
#471=CARTESIAN_POINT('',(10.7080782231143,80.1789194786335,-17.5699535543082));
#472=CARTESIAN_POINT('',(10.7238938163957,79.9585712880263,-17.6916547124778));
#473=CARTESIAN_POINT('',(10.7622068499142,79.5165128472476,-17.9314908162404));
#474=CARTESIAN_POINT('',(10.7847047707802,79.2948025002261,-18.0496255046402));
#475=CARTESIAN_POINT('',(10.8616544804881,78.6282451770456,-18.3989144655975));
#476=CARTESIAN_POINT('',(10.9255713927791,78.181816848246,-18.6250403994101));
#477=CARTESIAN_POINT('',(11.0664102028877,77.3479438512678,-19.0346218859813));
#478=CARTESIAN_POINT('',(11.1403619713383,76.9607742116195,-19.2196861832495));
#479=CARTESIAN_POINT('',(11.3050181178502,76.1856258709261,-19.580557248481));
#480=CARTESIAN_POINT('',(11.3957241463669,75.7976470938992,-19.7563631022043));
#481=CARTESIAN_POINT('',(11.5935742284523,75.0216151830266,-20.0985507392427));
#482=CARTESIAN_POINT('',(11.7007221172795,74.6335620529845,-20.264930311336));
#483=CARTESIAN_POINT('',(11.9313879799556,73.8581881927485,-20.5877481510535));
#484=CARTESIAN_POINT('',(12.0549056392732,73.4708674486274,-20.7441866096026));
#485=CARTESIAN_POINT('',(12.3163714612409,72.7038997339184,-21.0439307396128));
#486=CARTESIAN_POINT('',(12.4540552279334,72.3242296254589,-21.1874073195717));
#487=CARTESIAN_POINT('',(12.7458005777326,71.5671030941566,-21.4629534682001));
#488=CARTESIAN_POINT('',(12.8998598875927,71.1896463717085,-21.5950246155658));
#489=CARTESIAN_POINT('',(13.2250025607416,70.4376533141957,-21.8464430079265));
#490=CARTESIAN_POINT('',(13.3960903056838,70.0631177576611,-21.9657869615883));
#491=CARTESIAN_POINT('',(13.666071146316,69.5043911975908,-22.1338540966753));
#492=CARTESIAN_POINT('',(13.7583155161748,69.3186135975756,-22.1880644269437));
#493=CARTESIAN_POINT('',(13.9473861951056,68.948260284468,-22.2925349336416));
#494=CARTESIAN_POINT('',(14.0442129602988,68.7636846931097,-22.3427947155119));
#495=CARTESIAN_POINT('',(14.1433933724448,68.5798,-22.3909303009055));
#496=B_SPLINE_CURVE_WITH_KNOTS('',3,(#390,#391,#392,#393,#394,#395,#396,#397,#398,#399,#400,
#401,#402,#403,#404,#405,#406,#407,#408,#409,#410,#411,#412,#413,#414,#415,#416,#417,#418,#419,
#420,#421,#422,#423,#424,#425,#426,#427,#428,#429,#430,#431,#432,#433,#434,#435,#436,#437,#438,
#439,#440,#441,#442,#443,#444,#445,#446,#447,#448,#449,#450,#451,#452,#453,#454,#455,#456,#457,
#458,#459,#460,#461,#462,#463,#464,#465,#466,#467,#468,#469,#470,#471,#472,#473,#474,#475,#476,
#477,#478,#479,#480,#481,#482,#483,#484,#485,#486,#487,#488,#489,#490,#491,#492,#493,#494,#495),
.UNSPECIFIED.,.F.,.F.,(4,2,2,2,2,2,2,2,2,2,2,2,2,2,2,2,2,2,2,2,2,2,2,2,2,2,2,2,2,2,2,2,2,2,2,2,
2,2,2,2,2,2,2,2,2,2,2,2,2,2,2,2,4),(0.,0.542840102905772,1.08564511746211,2.17085376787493,
3.25525867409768,4.33976732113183,5.4305221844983,6.5212985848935,7.61215354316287,
8.70297647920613,10.3650975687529,11.196398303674,12.027641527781,12.85858662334,
13.6894562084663,14.5197908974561,15.3499881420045,16.1821952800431,17.0148549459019,
17.8469149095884,18.2625409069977,18.6780732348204,19.0990950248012,19.5203342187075,
20.3547558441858,20.7529146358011,21.150746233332,21.5511837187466,21.9517126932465,
22.3233446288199,22.6951557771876,23.338172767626,23.9834677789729,24.6186994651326,
25.2545758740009,25.8919145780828,26.5290325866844,27.2825500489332,28.0362555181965,
28.7905929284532,29.5450164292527,30.3015442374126,31.0581264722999,32.5707579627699,
33.876714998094,35.1828007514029,36.4891916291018,37.7955574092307,39.0808873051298,
40.366039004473,41.6515222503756,42.2946005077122,42.9377429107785),.UNSPECIFIED.);
#497=CARTESIAN_POINT('',(14.1432854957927,68.58,-22.3908779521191));
#498=VERTEX_POINT('',#497);
#499=EDGE_CURVE('E974',#387,#498,#496,.T.);
#500=ORIENTED_EDGE('',*,*,#499,.T.);
#501=CARTESIAN_POINT('',(15.70457419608,68.58,-21.3248748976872));
#502=VERTEX_POINT('',#501);
#503=EDGE_CURVE('E972',#498,#502,#385,.F.);
#504=ORIENTED_EDGE('',*,*,#503,.T.);
#505=CARTESIAN_POINT('',(19.6011992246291,62.2298,-22.3373805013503));
#506=CARTESIAN_POINT('',(19.28325195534,62.7634166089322,-22.2547645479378));
#507=CARTESIAN_POINT('',(18.9638646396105,63.29612059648,-22.1717744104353));
#508=CARTESIAN_POINT('',(18.3218531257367,64.3594037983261,-22.0049530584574));
#509=CARTESIAN_POINT('',(17.9992290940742,64.8899831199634,-21.9211218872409));
#510=CARTESIAN_POINT('',(17.350351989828,65.9487768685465,-21.752516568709));
#511=CARTESIAN_POINT('',(17.0240988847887,66.4769912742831,-21.6677424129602));
#512=CARTESIAN_POINT('',(16.3674755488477,67.5307185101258,-21.4971243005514));
#513=CARTESIAN_POINT('',(16.0371051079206,68.0562312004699,-21.4112802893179));
#514=CARTESIAN_POINT('',(15.7044472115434,68.5802,-21.3248419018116));
#515=B_SPLINE_CURVE_WITH_KNOTS('',3,(#505,#506,#507,#508,#509,#510,#511,#512,#513,#514),
.UNSPECIFIED.,.F.,.F.,(4,2,2,2,4),(0.,1.87988537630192,3.75967455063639,5.63948054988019,
7.51938283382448),.UNSPECIFIED.);
#516=CARTESIAN_POINT('',(19.6010800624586,62.23,-22.3373495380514));
#517=VERTEX_POINT('',#516);
#518=EDGE_CURVE('E767',#517,#502,#515,.T.);
#519=ORIENTED_EDGE('',*,*,#518,.F.);
#520=CARTESIAN_POINT('',(-19.6010800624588,62.23,-22.3373495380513));
#521=VERTEX_POINT('',#520);
#522=EDGE_CURVE('E849',#521,#517,#45,.T.);
#523=ORIENTED_EDGE('',*,*,#522,.F.);
#524=CARTESIAN_POINT('',(-15.7044472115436,68.5802,-21.3248419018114));
#525=CARTESIAN_POINT('',(-16.0371051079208,68.0562312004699,-21.4112802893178));
#526=CARTESIAN_POINT('',(-16.3674755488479,67.5307185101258,-21.4971243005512));
#527=CARTESIAN_POINT('',(-17.0240988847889,66.4769912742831,-21.6677424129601));
#528=CARTESIAN_POINT('',(-17.3503519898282,65.9487768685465,-21.7525165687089));
#529=CARTESIAN_POINT('',(-17.9992290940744,64.8899831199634,-21.9211218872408));
#530=CARTESIAN_POINT('',(-18.3218531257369,64.3594037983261,-22.0049530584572));
#531=CARTESIAN_POINT('',(-18.9638646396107,63.29612059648,-22.1717744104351));
#532=CARTESIAN_POINT('',(-19.2832519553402,62.7634166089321,-22.2547645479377));
#533=CARTESIAN_POINT('',(-19.6011992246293,62.2298,-22.3373805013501));
#534=B_SPLINE_CURVE_WITH_KNOTS('',3,(#524,#525,#526,#527,#528,#529,#530,#531,#532,#533),
.UNSPECIFIED.,.F.,.F.,(4,2,2,2,4),(0.,1.87990228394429,3.75970828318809,5.63949745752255,
7.51938283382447),.UNSPECIFIED.);
#535=CARTESIAN_POINT('',(-15.7045741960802,68.58,-21.3248748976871));
#536=VERTEX_POINT('',#535);
#537=EDGE_CURVE('E613',#536,#521,#534,.T.);
#538=ORIENTED_EDGE('',*,*,#537,.F.);
#539=CARTESIAN_POINT('',(0.,68.58,0.));
#540=DIRECTION('',(0.,1.,0.));
#541=DIRECTION('',(0.,0.,1.));
#542=AXIS2_PLACEMENT_3D('',#539,#540,#541);
#543=CIRCLE('',#542,26.4836542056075);
#544=CARTESIAN_POINT('',(-14.1432854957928,68.58,-22.390877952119));
#545=VERTEX_POINT('',#544);
#546=EDGE_CURVE('E1430',#536,#545,#543,.F.);
#547=ORIENTED_EDGE('',*,*,#546,.T.);
#548=CARTESIAN_POINT('',(-14.1433933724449,68.5798000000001,-22.3909303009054));
#549=CARTESIAN_POINT('',(-14.0596815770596,68.7350022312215,-22.350304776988));
#550=CARTESIAN_POINT('',(-13.9776470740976,68.8906992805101,-22.3081630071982));
#551=CARTESIAN_POINT('',(-13.8168553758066,69.2029732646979,-22.2210302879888));
#552=CARTESIAN_POINT('',(-13.7380979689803,69.3595501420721,-22.1760395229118));
#553=CARTESIAN_POINT('',(-13.5066666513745,69.8303500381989,-22.0370947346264));
#554=CARTESIAN_POINT('',(-13.3587718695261,70.1457572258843,-21.9391379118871));
#555=CARTESIAN_POINT('',(-13.0753567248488,70.7787217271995,-21.7338262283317));
#556=CARTESIAN_POINT('',(-12.9398272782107,71.0962772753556,-21.6264783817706));
#557=CARTESIAN_POINT('',(-12.680604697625,71.7332404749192,-21.4032338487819));
#558=CARTESIAN_POINT('',(-12.5569126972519,72.0526483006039,-21.2873363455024));
#559=CARTESIAN_POINT('',(-12.3204109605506,72.6946343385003,-21.0470421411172));
#560=CARTESIAN_POINT('',(-12.207668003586,73.017220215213,-20.9226003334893));
#561=CARTESIAN_POINT('',(-11.9936819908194,73.6632945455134,-20.6663853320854));
#562=CARTESIAN_POINT('',(-11.8924391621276,73.9867830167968,-20.5346119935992));
#563=CARTESIAN_POINT('',(-11.7013595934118,74.6342665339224,-20.2641447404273));
#564=CARTESIAN_POINT('',(-11.6115236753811,74.9582616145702,-20.1254503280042));
#565=CARTESIAN_POINT('',(-11.4433041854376,75.6062899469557,-19.8414364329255));
#566=CARTESIAN_POINT('',(-11.3649202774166,75.9303231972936,-19.6961171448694));
#567=CARTESIAN_POINT('',(-11.1817059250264,76.7476954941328,-19.3211632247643));
#568=CARTESIAN_POINT('',(-11.0845248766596,77.2408247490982,-19.0872302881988));
#569=CARTESIAN_POINT('',(-10.9599064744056,77.9784605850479,-18.7249280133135));
#570=CARTESIAN_POINT('',(-10.9218885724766,78.2240315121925,-18.6022415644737));
#571=CARTESIAN_POINT('',(-10.8531925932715,78.7141977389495,-18.3529388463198));
#572=CARTESIAN_POINT('',(-10.8225140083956,78.9587931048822,-18.2263228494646));
#573=CARTESIAN_POINT('',(-10.7688733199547,79.4465771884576,-17.9690231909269));
#574=CARTESIAN_POINT('',(-10.7459084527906,79.6897663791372,-17.8383410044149));
#575=CARTESIAN_POINT('',(-10.7081842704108,80.1743656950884,-17.5726008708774));
#576=CARTESIAN_POINT('',(-10.693424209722,80.4157759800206,-17.4375433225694));
#577=CARTESIAN_POINT('',(-10.6727907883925,80.8961071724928,-17.1627429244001));
#578=CARTESIAN_POINT('',(-10.666911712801,81.1350295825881,-17.0230031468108));
#579=CARTESIAN_POINT('',(-10.6649433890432,81.6097183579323,-16.7382475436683));
#580=CARTESIAN_POINT('',(-10.6688525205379,81.8454852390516,-16.5932325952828));
#581=CARTESIAN_POINT('',(-10.6877509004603,82.3133650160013,-16.2968182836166));
#582=CARTESIAN_POINT('',(-10.7027669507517,82.5454676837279,-16.1454043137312));
#583=CARTESIAN_POINT('',(-10.7457309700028,83.0038758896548,-15.8354539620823));
#584=CARTESIAN_POINT('',(-10.7736859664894,83.2301782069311,-15.676913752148));
#585=CARTESIAN_POINT('',(-10.8451251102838,83.6741617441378,-15.351527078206));
#586=CARTESIAN_POINT('',(-10.8885980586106,83.8918490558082,-15.1846866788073));
#587=CARTESIAN_POINT('',(-10.9683843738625,84.2084557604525,-14.9269806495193));
#588=CARTESIAN_POINT('',(-10.9973916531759,84.3122892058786,-14.8398818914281));
#589=CARTESIAN_POINT('',(-11.0609509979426,84.5158080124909,-14.662930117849));
#590=CARTESIAN_POINT('',(-11.0955018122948,84.6154943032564,-14.5730777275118));
#591=CARTESIAN_POINT('',(-11.1714874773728,84.8109037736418,-14.3891167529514));
#592=CARTESIAN_POINT('',(-11.2130072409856,84.90655720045,-14.2949676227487));
#593=CARTESIAN_POINT('',(-11.3035808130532,85.0907355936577,-14.1034347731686));
#594=CARTESIAN_POINT('',(-11.352638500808,85.1792568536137,-14.0060494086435));
#595=CARTESIAN_POINT('',(-11.512340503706,85.429646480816,-13.7101223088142));
#596=CARTESIAN_POINT('',(-11.636194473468,85.5782916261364,-13.5060546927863));
#597=CARTESIAN_POINT('',(-11.8507095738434,85.7493306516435,-13.1996116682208));
#598=CARTESIAN_POINT('',(-11.924869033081,85.7971000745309,-13.0998509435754));
#599=CARTESIAN_POINT('',(-12.0829789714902,85.873763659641,-12.9007063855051));
#600=CARTESIAN_POINT('',(-12.1669213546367,85.9026733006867,-12.8013223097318));
#601=CARTESIAN_POINT('',(-12.3437610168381,85.9385908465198,-12.6053038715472));
#602=CARTESIAN_POINT('',(-12.4367133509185,85.9454540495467,-12.5086917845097));
#603=CARTESIAN_POINT('',(-12.6281475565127,85.9359739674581,-12.322316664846));
#604=CARTESIAN_POINT('',(-12.7266306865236,85.9196253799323,-12.2325552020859));
#605=CARTESIAN_POINT('',(-12.9184346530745,85.8677160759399,-12.0684910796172));
#606=CARTESIAN_POINT('',(-13.0116153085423,85.8336265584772,-11.9935403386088));
#607=CARTESIAN_POINT('',(-13.1975950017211,85.7502029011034,-11.8522698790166));
#608=CARTESIAN_POINT('',(-13.2903938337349,85.7008614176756,-11.7859543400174));
#609=CARTESIAN_POINT('',(-13.5413620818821,85.5496530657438,-11.61636622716));
#610=CARTESIAN_POINT('',(-13.697840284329,85.4357254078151,-11.5214197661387));
#611=CARTESIAN_POINT('',(-14.0032728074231,85.1845941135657,-11.3524385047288));
#612=CARTESIAN_POINT('',(-14.1521985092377,85.0473094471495,-11.2784789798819));
#613=CARTESIAN_POINT('',(-14.4401544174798,84.7600134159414,-11.1484302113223));
#614=CARTESIAN_POINT('',(-14.5793027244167,84.6102339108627,-11.0920802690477));
#615=CARTESIAN_POINT('',(-14.8511494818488,84.3006741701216,-10.9925096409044));
#616=CARTESIAN_POINT('',(-14.9838412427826,84.140883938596,-10.9493023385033));
#617=CARTESIAN_POINT('',(-15.2438249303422,83.8139640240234,-10.8736636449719));
#618=CARTESIAN_POINT('',(-15.371103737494,83.6468183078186,-10.8412572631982));
#619=CARTESIAN_POINT('',(-15.6206584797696,83.3074809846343,-10.7856662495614));
#620=CARTESIAN_POINT('',(-15.7429361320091,83.1352911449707,-10.762478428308));
#621=CARTESIAN_POINT('',(-16.0051192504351,82.7552655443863,-10.7205377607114));
#622=CARTESIAN_POINT('',(-16.1441638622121,82.5466647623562,-10.7033691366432));
#623=CARTESIAN_POINT('',(-16.4170496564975,82.1254934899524,-10.678627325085));
#624=CARTESIAN_POINT('',(-16.5508895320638,81.9129220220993,-10.6710565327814));
#625=CARTESIAN_POINT('',(-16.8140587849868,81.4846459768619,-10.664422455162));
#626=CARTESIAN_POINT('',(-16.943384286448,81.2689389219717,-10.6653663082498));
#627=CARTESIAN_POINT('',(-17.1978874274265,80.8352423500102,-10.674967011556));
#628=CARTESIAN_POINT('',(-17.3230645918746,80.6172525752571,-10.6836247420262));
#629=CARTESIAN_POINT('',(-17.5699535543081,80.1789194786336,-10.7080782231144));
#630=CARTESIAN_POINT('',(-17.6916547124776,79.9585712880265,-10.7238938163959));
#631=CARTESIAN_POINT('',(-17.9314908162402,79.5165128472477,-10.7622068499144));
#632=CARTESIAN_POINT('',(-18.04962550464,79.2948025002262,-10.7847047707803));
#633=CARTESIAN_POINT('',(-18.3989144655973,78.6282451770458,-10.8616544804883));
#634=CARTESIAN_POINT('',(-18.62504039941,78.1818168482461,-10.9255713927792));
#635=CARTESIAN_POINT('',(-19.0346218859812,77.3479438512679,-11.0664102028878));
#636=CARTESIAN_POINT('',(-19.2196861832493,76.9607742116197,-11.1403619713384));
#637=CARTESIAN_POINT('',(-19.5805572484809,76.1856258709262,-11.3050181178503));
#638=CARTESIAN_POINT('',(-19.7563631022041,75.7976470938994,-11.3957241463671));
#639=CARTESIAN_POINT('',(-20.0985507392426,75.0216151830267,-11.5935742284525));
#640=CARTESIAN_POINT('',(-20.2649303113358,74.6335620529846,-11.7007221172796));
#641=CARTESIAN_POINT('',(-20.5877481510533,73.8581881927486,-11.9313879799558));
#642=CARTESIAN_POINT('',(-20.7441866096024,73.4708674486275,-12.0549056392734));
#643=CARTESIAN_POINT('',(-21.0439307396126,72.7038997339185,-12.3163714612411));
#644=CARTESIAN_POINT('',(-21.1874073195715,72.324229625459,-12.4540552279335));
#645=CARTESIAN_POINT('',(-21.4629534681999,71.5671030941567,-12.7458005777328));
#646=CARTESIAN_POINT('',(-21.5950246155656,71.1896463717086,-12.8998598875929));
#647=CARTESIAN_POINT('',(-21.8464430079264,70.4376533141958,-13.2250025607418));
#648=CARTESIAN_POINT('',(-21.9657869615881,70.0631177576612,-13.396090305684));
#649=CARTESIAN_POINT('',(-22.1338540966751,69.5043911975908,-13.6660711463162));
#650=CARTESIAN_POINT('',(-22.1880644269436,69.3186135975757,-13.7583155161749));
#651=CARTESIAN_POINT('',(-22.2925349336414,68.9482602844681,-13.9473861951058));
#652=CARTESIAN_POINT('',(-22.3427947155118,68.7636846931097,-14.044212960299));
#653=CARTESIAN_POINT('',(-22.3909303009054,68.5798000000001,-14.143393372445));
#654=B_SPLINE_CURVE_WITH_KNOTS('',3,(#548,#549,#550,#551,#552,#553,#554,#555,#556,#557,#558,
#559,#560,#561,#562,#563,#564,#565,#566,#567,#568,#569,#570,#571,#572,#573,#574,#575,#576,#577,
#578,#579,#580,#581,#582,#583,#584,#585,#586,#587,#588,#589,#590,#591,#592,#593,#594,#595,#596,
#597,#598,#599,#600,#601,#602,#603,#604,#605,#606,#607,#608,#609,#610,#611,#612,#613,#614,#615,
#616,#617,#618,#619,#620,#621,#622,#623,#624,#625,#626,#627,#628,#629,#630,#631,#632,#633,#634,
#635,#636,#637,#638,#639,#640,#641,#642,#643,#644,#645,#646,#647,#648,#649,#650,#651,#652,#653),
.UNSPECIFIED.,.F.,.F.,(4,2,2,2,2,2,2,2,2,2,2,2,2,2,2,2,2,2,2,2,2,2,2,2,2,2,2,2,2,2,2,2,2,2,2,2,
2,2,2,2,2,2,2,2,2,2,2,2,2,2,2,2,4),(0.,0.542840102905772,1.08564511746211,2.17085376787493,
3.25525867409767,4.33976732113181,5.43052218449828,6.52129858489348,7.61215354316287,
8.70297647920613,10.3650975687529,11.196398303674,12.027641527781,12.85858662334,
13.6894562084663,14.5197908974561,15.3499881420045,16.1821952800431,17.0148549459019,
17.8469149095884,18.2625409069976,18.6780732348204,19.0990950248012,19.5203342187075,
20.3547558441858,20.7529146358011,21.150746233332,21.5511837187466,21.9517126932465,
22.3233446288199,22.6951557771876,23.338172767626,23.9834677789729,24.6186994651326,
25.2545758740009,25.8919145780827,26.5290325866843,27.2825500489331,28.0362555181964,
28.7905929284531,29.5450164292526,30.3015442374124,31.0581264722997,32.5707579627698,
33.8767149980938,35.1828007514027,36.4891916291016,37.7955574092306,39.0808873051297,
40.3660390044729,41.6515222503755,42.294600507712,42.9377429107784),.UNSPECIFIED.);
#655=CARTESIAN_POINT('',(-22.3908779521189,68.58,-14.1432854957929));
#656=VERTEX_POINT('',#655);
#657=EDGE_CURVE('E1400',#545,#656,#654,.T.);
#658=ORIENTED_EDGE('',*,*,#657,.T.);
#659=EDGE_CURVE('E938',#656,#38,#543,.F.);
#660=ORIENTED_EDGE('',*,*,#659,.T.);
#661=EDGE_LOOP('',(#40,#49,#64,#73,#184,#188,#203,#207,#222,#231,#342,#346,#361,#365,#380,#389,
#500,#504,#519,#523,#538,#547,#658,#660));
#662=FACE_BOUND('',#661,.T.);
#663=CARTESIAN_POINT('',(0.,89.408,0.));
#664=DIRECTION('',(0.,-1.,0.));
#665=DIRECTION('',(0.,0.,-1.));
#666=AXIS2_PLACEMENT_3D('',#663,#664,#665);
#667=CIRCLE('',#666,15.875);
#668=CARTESIAN_POINT('',(0.,89.408,-15.875));
#669=VERTEX_POINT('',#668);
#670=EDGE_CURVE('E846',#669,#669,#667,.T.);
#671=ORIENTED_EDGE('',*,*,#670,.T.);
#672=EDGE_LOOP('',(#671));
#673=FACE_BOUND('',#672,.T.);
#674=ADVANCED_FACE('F31',(#662,#673),#23,.T.);
#675=CARTESIAN_POINT('',(0.,105.41,0.));
#676=DIRECTION('',(0.,-1.,0.));
#677=DIRECTION('',(0.,0.,-1.));
#678=AXIS2_PLACEMENT_3D('',#675,#676,#677);
#679=CYLINDRICAL_SURFACE('',#678,29.718);
#680=CARTESIAN_POINT('',(0.,1.52399999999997,0.));
#681=DIRECTION('',(0.,1.,0.));
#682=DIRECTION('',(0.,0.,1.));
#683=AXIS2_PLACEMENT_3D('',#680,#681,#682);
#684=CIRCLE('',#683,29.718);
#685=CARTESIAN_POINT('',(0.,1.52399999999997,29.718));
#686=VERTEX_POINT('',#685);
#687=EDGE_CURVE('E1056',#686,#686,#684,.T.);
#688=ORIENTED_EDGE('',*,*,#687,.T.);
#689=EDGE_LOOP('',(#688));
#690=FACE_BOUND('',#689,.T.);
#691=CARTESIAN_POINT('',(-7.85615249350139,20.2665766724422,-28.6607814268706));
#692=CARTESIAN_POINT('',(-7.65712208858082,20.0459360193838,-28.7153371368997));
#693=CARTESIAN_POINT('',(-7.4488859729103,19.8336774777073,-28.7701860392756));
#694=CARTESIAN_POINT('',(-7.01523925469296,19.4272434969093,-28.8789872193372));
#695=CARTESIAN_POINT('',(-6.7898288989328,19.2330677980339,-28.9329395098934));
#696=CARTESIAN_POINT('',(-6.32315712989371,18.8640818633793,-29.0384990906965));
#697=CARTESIAN_POINT('',(-6.08189568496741,18.689271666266,-29.0901063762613));
#698=CARTESIAN_POINT('',(-5.58505684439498,18.3603278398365,-29.189566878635));
#699=CARTESIAN_POINT('',(-5.32948479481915,18.2061865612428,-29.2374214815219));
#700=CARTESIAN_POINT('',(-4.80487780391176,17.9193486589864,-29.3282065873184));
#701=CARTESIAN_POINT('',(-4.53581076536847,17.7867066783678,-29.3711244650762));
#702=CARTESIAN_POINT('',(-3.98658729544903,17.5444751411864,-29.4506982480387));
#703=CARTESIAN_POINT('',(-3.70643082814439,17.4348856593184,-29.4873541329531));
#704=CARTESIAN_POINT('',(-3.13708182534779,17.2398112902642,-29.5533473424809));
#705=CARTESIAN_POINT('',(-2.84789163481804,17.1543202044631,-29.5826865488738));
#706=CARTESIAN_POINT('',(-2.26258385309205,17.008271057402,-29.6331992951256));
#707=CARTESIAN_POINT('',(-1.96646656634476,16.9477119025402,-29.6543731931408));
#708=CARTESIAN_POINT('',(-1.3821546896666,16.8541726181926,-29.6872225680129));
#709=CARTESIAN_POINT('',(-1.09414803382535,16.8201432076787,-29.6992588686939));
#710=CARTESIAN_POINT('',(-0.516084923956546,16.7759074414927,-29.7149250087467));
#711=CARTESIAN_POINT('',(-0.226028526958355,16.7657004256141,-29.718555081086));
#712=CARTESIAN_POINT('',(0.353873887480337,16.7692146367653,-29.7173074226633));
#713=CARTESIAN_POINT('',(0.643719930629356,16.7829321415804,-29.7124310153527));
#714=CARTESIAN_POINT('',(1.22103534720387,16.8341457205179,-29.6943092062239));
#715=CARTESIAN_POINT('',(1.50850475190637,16.8716414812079,-29.68106391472));
#716=CARTESIAN_POINT('',(2.06928409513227,16.9683662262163,-29.6471554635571));
#717=CARTESIAN_POINT('',(2.34274450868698,17.0268191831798,-29.6267576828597));
#718=CARTESIAN_POINT('',(2.88359361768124,17.1650314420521,-29.5790147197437));
#719=CARTESIAN_POINT('',(3.15098248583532,17.2447901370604,-29.5516697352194));
#720=CARTESIAN_POINT('',(3.67795466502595,17.4249187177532,-29.490719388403));
#721=CARTESIAN_POINT('',(3.93753866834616,17.5252867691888,-29.4571145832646));
#722=CARTESIAN_POINT('',(4.4474483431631,17.7458715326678,-29.3844531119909));
#723=CARTESIAN_POINT('',(4.69777045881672,17.8660957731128,-29.3453943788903));
#724=CARTESIAN_POINT('',(5.19505086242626,18.1294068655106,-29.2615185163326));
#725=CARTESIAN_POINT('',(5.44167732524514,18.2730761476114,-29.2165627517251));
#726=CARTESIAN_POINT('',(5.92213668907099,18.5795185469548,-29.1229763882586));
#727=CARTESIAN_POINT('',(6.15596514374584,18.7422982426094,-29.0743445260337));
#728=CARTESIAN_POINT('',(6.60948160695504,19.0858614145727,-28.9746129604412));
#729=CARTESIAN_POINT('',(6.82916780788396,19.2666471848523,-28.9235129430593));
#730=CARTESIAN_POINT('',(7.25318857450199,19.6450937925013,-28.8201043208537));
#731=CARTESIAN_POINT('',(7.45752256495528,19.8427552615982,-28.7677956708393));
#732=CARTESIAN_POINT('',(7.86066679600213,20.2652712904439,-28.6603446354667));
#733=CARTESIAN_POINT('',(8.05853452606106,20.4910274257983,-28.6052067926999));
#734=CARTESIAN_POINT('',(8.4346253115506,20.9585947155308,-28.4965775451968));
#735=CARTESIAN_POINT('',(8.61285462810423,21.2004007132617,-28.4430856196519));
#736=CARTESIAN_POINT('',(8.94864434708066,21.698776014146,-28.3392342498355));
#737=CARTESIAN_POINT('',(9.10619506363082,21.955352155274,-28.288876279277));
#738=CARTESIAN_POINT('',(9.39933251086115,22.4814601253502,-28.1928335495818));
#739=CARTESIAN_POINT('',(9.53492829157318,22.7509865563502,-28.1471468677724));
#740=CARTESIAN_POINT('',(9.78379719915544,23.3027621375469,-28.0616152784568));
#741=CARTESIAN_POINT('',(9.8969522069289,23.5850694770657,-28.0218015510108));
#742=CARTESIAN_POINT('',(10.0990649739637,24.1591535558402,-27.9495964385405));
#743=CARTESIAN_POINT('',(10.1880225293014,24.4509303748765,-27.9172051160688));
#744=CARTESIAN_POINT('',(10.3408444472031,25.0416664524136,-27.8609601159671));
#745=CARTESIAN_POINT('',(10.4047193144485,25.3406226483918,-27.8371028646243));
#746=CARTESIAN_POINT('',(10.5067576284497,25.9434799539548,-27.7987509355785));
#747=CARTESIAN_POINT('',(10.5449225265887,26.2473807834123,-27.7842557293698));
#748=CARTESIAN_POINT('',(10.5937616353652,26.8410408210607,-27.7656689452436));
#749=CARTESIAN_POINT('',(10.605817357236,27.1306708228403,-27.7610546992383));
#750=CARTESIAN_POINT('',(10.6064476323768,27.7099540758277,-27.7608140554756));
#751=CARTESIAN_POINT('',(10.5950230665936,27.9996073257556,-27.7651873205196));
#752=CARTESIAN_POINT('',(10.5488110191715,28.5767481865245,-27.7827773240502));
#753=CARTESIAN_POINT('',(10.5140251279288,28.8642359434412,-27.7959934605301));
#754=CARTESIAN_POINT('',(10.421435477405,29.4349587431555,-27.8308398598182));
#755=CARTESIAN_POINT('',(10.3636316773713,29.7181937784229,-27.8524701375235));
#756=CARTESIAN_POINT('',(10.2271486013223,30.2719313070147,-27.9028692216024));
#757=CARTESIAN_POINT('',(10.1489826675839,30.5425767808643,-27.9314614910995));
#758=CARTESIAN_POINT('',(9.97182944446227,31.0762719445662,-27.9951959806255));
#759=CARTESIAN_POINT('',(9.87283479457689,31.3393189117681,-28.0303405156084));
#760=CARTESIAN_POINT('',(9.65480789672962,31.8561278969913,-28.1061829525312));
#761=CARTESIAN_POINT('',(9.53577608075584,32.1098901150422,-28.1468807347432));
#762=CARTESIAN_POINT('',(9.27850647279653,32.6067091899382,-28.2327332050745));
#763=CARTESIAN_POINT('',(9.14026731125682,32.8497652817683,-28.2778882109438));
#764=CARTESIAN_POINT('',(8.83859079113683,33.3349100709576,-28.3736678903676));
#765=CARTESIAN_POINT('',(8.67427839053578,33.5764239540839,-28.4244494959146));
#766=CARTESIAN_POINT('',(8.32665356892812,34.0448622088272,-28.5282186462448));
#767=CARTESIAN_POINT('',(8.14334067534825,34.2717862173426,-28.5812062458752));
#768=CARTESIAN_POINT('',(7.75876512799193,34.7097930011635,-28.6879925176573));
#769=CARTESIAN_POINT('',(7.55749731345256,34.9208711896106,-28.7417914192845));
#770=CARTESIAN_POINT('',(7.13822296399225,35.3258509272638,-28.8487798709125));
#771=CARTESIAN_POINT('',(6.92021667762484,35.5197527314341,-28.9019694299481));
#772=CARTESIAN_POINT('',(6.45929676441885,35.8968536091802,-29.0085374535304));
#773=CARTESIAN_POINT('',(6.21572442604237,36.079272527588,-29.0618318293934));
#774=CARTESIAN_POINT('',(5.71336110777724,36.42275081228,-29.1647515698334));
#775=CARTESIAN_POINT('',(5.45457598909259,36.5838183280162,-29.2143783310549));
#776=CARTESIAN_POINT('',(4.92335444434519,36.8833936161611,-29.3085800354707));
#777=CARTESIAN_POINT('',(4.65091730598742,37.0219002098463,-29.3531547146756));
#778=CARTESIAN_POINT('',(4.0942712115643,37.275117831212,-29.4359580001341));
#779=CARTESIAN_POINT('',(3.81006275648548,37.3898298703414,-29.4741868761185));
#780=CARTESIAN_POINT('',(3.2401694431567,37.5914480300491,-29.54218704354));
#781=CARTESIAN_POINT('',(2.95475677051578,37.6790525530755,-29.5721680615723));
#782=CARTESIAN_POINT('',(2.37685200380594,37.8299064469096,-29.6242173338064));
#783=CARTESIAN_POINT('',(2.08436001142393,37.8931561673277,-29.6462857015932));
#784=CARTESIAN_POINT('',(1.49464909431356,37.99462391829,-29.6818593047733));
#785=CARTESIAN_POINT('',(1.19743179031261,38.0328503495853,-29.6953674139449));
#786=CARTESIAN_POINT('',(0.600556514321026,38.0838878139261,-29.713431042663));
#787=CARTESIAN_POINT('',(0.300898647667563,38.0966999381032,-29.7179869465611));
#788=CARTESIAN_POINT('',(-0.281947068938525,38.096770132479,-29.7180122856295));
#789=CARTESIAN_POINT('',(-0.565135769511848,38.0853927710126,-29.7139669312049));
#790=CARTESIAN_POINT('',(-1.1294453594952,38.0399317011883,-29.6978710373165));
#791=CARTESIAN_POINT('',(-1.41056633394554,38.0058489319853,-29.6858208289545));
#792=CARTESIAN_POINT('',(-1.96872638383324,37.9153106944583,-29.6540348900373));
#793=CARTESIAN_POINT('',(-2.24576557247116,37.8588558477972,-29.6342993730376));
#794=CARTESIAN_POINT('',(-2.79385992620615,37.7241019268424,-29.5876583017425));
#795=CARTESIAN_POINT('',(-3.06491500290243,37.6458025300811,-29.5607526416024));
#796=CARTESIAN_POINT('',(-3.59825216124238,37.4683865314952,-29.500573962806));
#797=CARTESIAN_POINT('',(-3.86056317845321,37.3693486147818,-29.4673250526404));
#798=CARTESIAN_POINT('',(-4.37593704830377,37.1510568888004,-29.3952110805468));
#799=CARTESIAN_POINT('',(-4.62899655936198,37.031795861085,-29.3563440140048));
#800=CARTESIAN_POINT('',(-5.12428986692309,36.7739905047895,-29.2739510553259));
#801=CARTESIAN_POINT('',(-5.36652380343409,36.6354464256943,-29.2304252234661));
#802=CARTESIAN_POINT('',(-5.83884689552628,36.3400342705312,-29.1397534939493));
#803=CARTESIAN_POINT('',(-6.06893518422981,36.1831648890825,-29.0926073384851));
#804=CARTESIAN_POINT('',(-6.52722679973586,35.8436007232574,-28.9933198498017));
#805=CARTESIAN_POINT('',(-6.7547255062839,35.6599930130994,-28.941046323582));
#806=CARTESIAN_POINT('',(-7.19364342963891,35.2748427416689,-28.8350828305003));
#807=CARTESIAN_POINT('',(-7.4050621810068,35.0732996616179,-28.7813928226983));
#808=CARTESIAN_POINT('',(-7.81067832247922,34.6534507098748,-28.6739753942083));
#809=CARTESIAN_POINT('',(-8.00487021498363,34.4351395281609,-28.6202479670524));
#810=CARTESIAN_POINT('',(-8.37481066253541,33.9831027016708,-28.5141912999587));
#811=CARTESIAN_POINT('',(-8.55055951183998,33.7493773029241,-28.4618620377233));
#812=CARTESIAN_POINT('',(-8.8891678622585,33.258223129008,-28.3579765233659));
#813=CARTESIAN_POINT('',(-9.05123108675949,33.0002202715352,-28.306534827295));
#814=CARTESIAN_POINT('',(-9.35298806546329,32.4707399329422,-28.2082668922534));
#815=CARTESIAN_POINT('',(-9.49269043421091,32.1992676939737,-28.1614388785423));
#816=CARTESIAN_POINT('',(-9.74867898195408,31.6445492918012,-28.0738507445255));
#817=CARTESIAN_POINT('',(-9.86496546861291,31.3613032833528,-28.0330905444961));
#818=CARTESIAN_POINT('',(-10.0730862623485,30.7850245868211,-27.9589820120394));
#819=CARTESIAN_POINT('',(-10.164921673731,30.4919923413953,-27.9256333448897));
#820=CARTESIAN_POINT('',(-10.3208696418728,29.907250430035,-27.86836683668));
#821=CARTESIAN_POINT('',(-10.3857324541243,29.6157657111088,-27.844195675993));
#822=CARTESIAN_POINT('',(-10.4909749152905,29.0278123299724,-27.8047143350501));
#823=CARTESIAN_POINT('',(-10.5313550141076,28.73134375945,-27.7894039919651));
#824=CARTESIAN_POINT('',(-10.5871996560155,28.1358399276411,-27.7681764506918));
#825=CARTESIAN_POINT('',(-10.6026731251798,27.8368056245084,-27.7622558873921));
#826=CARTESIAN_POINT('',(-10.6085644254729,27.2384585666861,-27.7600053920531));
#827=CARTESIAN_POINT('',(-10.5989830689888,26.9391458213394,-27.7636751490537));
#828=CARTESIAN_POINT('',(-10.556017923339,26.3581211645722,-27.7800376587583));
#829=CARTESIAN_POINT('',(-10.5238943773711,26.0763015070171,-27.7922525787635));
#830=CARTESIAN_POINT('',(-10.4375304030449,25.5165639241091,-27.8248020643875));
#831=CARTESIAN_POINT('',(-10.3832910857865,25.2386458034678,-27.8451362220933));
#832=CARTESIAN_POINT('',(-10.2531692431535,24.6885142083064,-27.8933119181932));
#833=CARTESIAN_POINT('',(-10.177280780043,24.4163023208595,-27.9211555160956));
#834=CARTESIAN_POINT('',(-10.0045082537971,23.8794008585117,-27.9835266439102));
#835=CARTESIAN_POINT('',(-9.90762230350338,23.6147119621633,-28.018054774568));
#836=CARTESIAN_POINT('',(-9.68381651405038,23.070672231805,-28.0962368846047));
#837=CARTESIAN_POINT('',(-9.55496000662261,22.7921951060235,-28.1404367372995));
#838=CARTESIAN_POINT('',(-9.27422460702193,22.2480367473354,-28.2342020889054));
#839=CARTESIAN_POINT('',(-9.12234385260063,21.9823565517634,-28.2837680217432));
#840=CARTESIAN_POINT('',(-8.79671166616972,21.4654965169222,-28.3867317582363));
#841=CARTESIAN_POINT('',(-8.62295725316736,21.2143186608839,-28.4401300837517));
#842=CARTESIAN_POINT('',(-8.25475219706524,20.7280097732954,-28.5491761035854));
#843=CARTESIAN_POINT('',(-8.06029467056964,20.4928841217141,-28.6048245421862));
#844=CARTESIAN_POINT('',(-7.85615249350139,20.2665766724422,-28.6607814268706));
#845=B_SPLINE_CURVE_WITH_KNOTS('',3,(#691,#692,#693,#694,#695,#696,#697,#698,#699,#700,#701,
#702,#703,#704,#705,#706,#707,#708,#709,#710,#711,#712,#713,#714,#715,#716,#717,#718,#719,#720,
#721,#722,#723,#724,#725,#726,#727,#728,#729,#730,#731,#732,#733,#734,#735,#736,#737,#738,#739,
#740,#741,#742,#743,#744,#745,#746,#747,#748,#749,#750,#751,#752,#753,#754,#755,#756,#757,#758,
#759,#760,#761,#762,#763,#764,#765,#766,#767,#768,#769,#770,#771,#772,#773,#774,#775,#776,#777,
#778,#779,#780,#781,#782,#783,#784,#785,#786,#787,#788,#789,#790,#791,#792,#793,#794,#795,#796,
#797,#798,#799,#800,#801,#802,#803,#804,#805,#806,#807,#808,#809,#810,#811,#812,#813,#814,#815,
#816,#817,#818,#819,#820,#821,#822,#823,#824,#825,#826,#827,#828,#829,#830,#831,#832,#833,#834,
#835,#836,#837,#838,#839,#840,#841,#842,#843,#844),.UNSPECIFIED.,.T.,.F.,(4,2,2,2,2,2,2,2,2,2,2,
2,2,2,2,2,2,2,2,2,2,2,2,2,2,2,2,2,2,2,2,2,2,2,2,2,2,2,2,2,2,2,2,2,2,2,2,2,2,2,2,2,2,2,2,2,2,2,2,
2,2,2,2,2,2,2,2,2,2,2,2,2,2,2,2,2,4),(0.,0.906072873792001,1.8121327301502,2.71819439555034,
3.62391980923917,4.53191230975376,5.43990775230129,6.34766942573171,7.25539127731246,
8.12507804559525,8.99474071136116,9.86426808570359,10.7337839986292,11.5739601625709,
12.4141123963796,13.2541898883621,14.0945866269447,14.9604511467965,15.826614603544,
16.6928885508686,17.5591949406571,18.4737819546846,19.3880765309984,20.3027978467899,
21.2171411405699,22.1361763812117,23.0552193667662,23.9738770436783,24.8924828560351,
25.7611573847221,26.6297993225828,27.4983821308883,28.3669664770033,29.215476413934,
30.0642867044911,30.9130786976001,31.7619312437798,32.6504093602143,33.5389095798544,
34.4276660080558,35.3164092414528,36.2421030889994,37.1674425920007,38.0928304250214,
39.0181789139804,39.9171937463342,40.8161956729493,41.7148956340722,42.613557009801,
43.4628719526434,44.312151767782,45.1614079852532,46.0106767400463,46.8567798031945,
47.7031855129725,48.549580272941,49.3960353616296,50.2859932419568,51.1759768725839,
52.0662435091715,52.9564959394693,53.8823420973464,54.8078307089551,55.7333071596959,
56.6587418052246,57.5563624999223,58.4539666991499,59.3512491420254,60.2485024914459,
61.0992213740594,61.9498975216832,62.8008072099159,63.6517934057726,64.5806255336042,
65.5095328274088,66.4385668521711,67.3679107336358),.UNSPECIFIED.);
#846=CARTESIAN_POINT('',(-7.85615249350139,20.2665766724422,-28.6607814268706));
#847=VERTEX_POINT('',#846);
#848=EDGE_CURVE('E873',#847,#847,#845,.T.);
#849=ORIENTED_EDGE('',*,*,#848,.T.);
#850=EDGE_LOOP('',(#849));
#851=FACE_BOUND('',#850,.T.);
#852=CARTESIAN_POINT('',(-7.85615249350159,20.2665766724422,28.6607814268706));
#853=CARTESIAN_POINT('',(-8.05440487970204,20.4863542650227,28.6064390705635));
#854=CARTESIAN_POINT('',(-8.24351690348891,20.7144413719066,28.5523893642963));
#855=CARTESIAN_POINT('',(-8.60230043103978,21.1858739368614,28.446352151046));
#856=CARTESIAN_POINT('',(-8.77197245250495,21.4292189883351,28.3943645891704));
#857=CARTESIAN_POINT('',(-9.0907466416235,21.929701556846,28.2939178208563));
#858=CARTESIAN_POINT('',(-9.23985026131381,22.1868380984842,28.2454583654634));
#859=CARTESIAN_POINT('',(-9.51637581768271,22.7132509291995,28.1534962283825));
#860=CARTESIAN_POINT('',(-9.64380576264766,22.9825226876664,28.1099917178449));
#861=CARTESIAN_POINT('',(-9.8763493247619,23.5323041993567,28.0291358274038));
#862=CARTESIAN_POINT('',(-9.98140246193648,23.8128420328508,27.991801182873));
#863=CARTESIAN_POINT('',(-10.1678372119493,24.3825604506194,27.9246207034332));
#864=CARTESIAN_POINT('',(-10.2492188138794,24.6717410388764,27.894774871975));
#865=CARTESIAN_POINT('',(-10.3875092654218,25.2565510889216,27.8435741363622));
#866=CARTESIAN_POINT('',(-10.4444253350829,25.5521786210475,27.8222167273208));
#867=CARTESIAN_POINT('',(-10.5332319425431,26.147683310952,27.7887173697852));
#868=CARTESIAN_POINT('',(-10.5651235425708,26.4475602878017,27.7765750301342));
#869=CARTESIAN_POINT('',(-10.6027218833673,27.0363134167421,27.762243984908));
#870=CARTESIAN_POINT('',(-10.6094885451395,27.325112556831,27.7596524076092));
#871=CARTESIAN_POINT('',(-10.599711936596,27.902252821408,27.7633870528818));
#872=CARTESIAN_POINT('',(-10.5831693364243,28.1905939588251,27.7697130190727));
#873=CARTESIAN_POINT('',(-10.5269416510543,28.7646703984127,27.7910763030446));
#874=CARTESIAN_POINT('',(-10.4872572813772,29.0504057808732,27.8061133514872));
#875=CARTESIAN_POINT('',(-10.3851323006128,29.6172150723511,27.8444162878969));
#876=CARTESIAN_POINT('',(-10.3226916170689,29.8982889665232,27.8676822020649));
#877=CARTESIAN_POINT('',(-10.1770024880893,30.4486440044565,27.9212113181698));
#878=CARTESIAN_POINT('',(-10.0941635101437,30.7180473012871,27.9513360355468));
#879=CARTESIAN_POINT('',(-9.90777687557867,31.2488829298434,28.0179455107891));
#880=CARTESIAN_POINT('',(-9.80422188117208,31.5103123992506,28.0544325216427));
#881=CARTESIAN_POINT('',(-9.57720952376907,32.0235402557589,28.1327387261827));
#882=CARTESIAN_POINT('',(-9.45375244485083,32.2753387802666,28.1745578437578));
#883=CARTESIAN_POINT('',(-9.18778347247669,32.7679059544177,28.2624090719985));
#884=CARTESIAN_POINT('',(-9.04527023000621,33.0086738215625,28.3084414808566));
#885=CARTESIAN_POINT('',(-8.73467232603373,33.4893503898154,28.4058582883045));
#886=CARTESIAN_POINT('',(-8.56567771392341,33.7286407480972,28.4573943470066));
#887=CARTESIAN_POINT('',(-8.20880040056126,34.1922479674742,28.562382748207));
#888=CARTESIAN_POINT('',(-8.02091719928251,34.4165644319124,28.6158351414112));
#889=CARTESIAN_POINT('',(-7.62733393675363,34.8489716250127,28.7232469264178));
#890=CARTESIAN_POINT('',(-7.42162886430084,35.0570577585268,28.7772064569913));
#891=CARTESIAN_POINT('',(-6.99363962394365,35.4556679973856,28.8842029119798));
#892=CARTESIAN_POINT('',(-6.77135576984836,35.6461924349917,28.9372398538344));
#893=CARTESIAN_POINT('',(-6.30257497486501,36.0154674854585,29.0430198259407));
#894=CARTESIAN_POINT('',(-6.055474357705,36.1934788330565,29.0956723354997));
#895=CARTESIAN_POINT('',(-5.54639100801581,36.5278427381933,29.1969928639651));
#896=CARTESIAN_POINT('',(-5.28441408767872,36.6842036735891,29.2456624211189));
#897=CARTESIAN_POINT('',(-4.74719064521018,36.9740730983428,29.3376543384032));
#898=CARTESIAN_POINT('',(-4.47194379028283,37.1075810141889,29.3809765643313));
#899=CARTESIAN_POINT('',(-3.91010018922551,37.3505335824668,29.461010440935));
#900=CARTESIAN_POINT('',(-3.62350395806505,37.4599793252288,29.4977223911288));
#901=CARTESIAN_POINT('',(-3.05038221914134,37.650643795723,29.562394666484));
#902=CARTESIAN_POINT('',(-2.76414686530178,37.7326524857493,29.590597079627));
#903=CARTESIAN_POINT('',(-2.18512234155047,37.8723094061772,29.6389802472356));
#904=CARTESIAN_POINT('',(-1.89233328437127,37.9299580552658,29.6591611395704));
#905=CARTESIAN_POINT('',(-1.30255918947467,38.0202767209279,29.6909084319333));
#906=CARTESIAN_POINT('',(-1.00557553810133,38.0529548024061,29.7024776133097));
#907=CARTESIAN_POINT('',(-0.409697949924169,38.0930061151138,29.7166699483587));
#908=CARTESIAN_POINT('',(-0.110804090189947,38.1003803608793,29.7192934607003));
#909=CARTESIAN_POINT('',(0.470401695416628,38.0900338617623,29.7156208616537));
#910=CARTESIAN_POINT('',(0.752741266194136,38.0736408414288,29.7097966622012));
#911=CARTESIAN_POINT('',(1.31491276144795,38.0182945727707,29.6902277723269));
#912=CARTESIAN_POINT('',(1.59474478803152,37.9793422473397,29.6764834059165));
#913=CARTESIAN_POINT('',(2.14992064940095,37.8792536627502,29.6414361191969));
#914=CARTESIAN_POINT('',(2.4252645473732,37.8181177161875,29.620133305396));
#915=CARTESIAN_POINT('',(2.96959537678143,37.6742257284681,29.5705212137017));
#916=CARTESIAN_POINT('',(3.23858219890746,37.5914693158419,29.5422118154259));
#917=CARTESIAN_POINT('',(3.76845279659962,37.4050564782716,29.4793059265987));
#918=CARTESIAN_POINT('',(4.02933640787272,37.3013996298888,29.4447093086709));
#919=CARTESIAN_POINT('',(4.54148803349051,37.073987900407,29.3700767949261));
#920=CARTESIAN_POINT('',(4.79275256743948,36.9502258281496,29.3300389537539));
#921=CARTESIAN_POINT('',(5.28411618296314,36.6835567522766,29.2455089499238));
#922=CARTESIAN_POINT('',(5.52421525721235,36.5406497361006,29.2010167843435));
#923=CARTESIAN_POINT('',(5.99194625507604,36.2366667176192,29.1086403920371));
#924=CARTESIAN_POINT('',(6.21957729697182,36.0755894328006,29.0607559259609));
#925=CARTESIAN_POINT('',(6.67283458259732,35.7273197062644,28.9601364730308));
#926=CARTESIAN_POINT('',(6.8977194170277,35.5391971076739,28.9072788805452));
#927=CARTESIAN_POINT('',(7.33104140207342,35.1451679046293,28.800436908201));
#928=CARTESIAN_POINT('',(7.53947805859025,34.9392607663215,28.7464524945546));
#929=CARTESIAN_POINT('',(7.93876344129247,34.5108555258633,28.6387558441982));
#930=CARTESIAN_POINT('',(8.12960671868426,34.2883523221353,28.5850436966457));
#931=CARTESIAN_POINT('',(8.49248650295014,33.8281290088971,28.4793419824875));
#932=CARTESIAN_POINT('',(8.66452338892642,33.5904092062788,28.4273523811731));
#933=CARTESIAN_POINT('',(8.99471646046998,33.0920519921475,28.3246465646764));
#934=CARTESIAN_POINT('',(9.15212157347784,32.8308916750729,28.2740490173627));
#935=CARTESIAN_POINT('',(9.44430021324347,32.2954623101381,28.1777994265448));
#936=CARTESIAN_POINT('',(9.57908257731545,32.021198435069,28.1321454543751));
#937=CARTESIAN_POINT('',(9.82497867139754,31.4613109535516,28.0472146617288));
#938=CARTESIAN_POINT('',(9.93609358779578,31.175687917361,28.0079375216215));
#939=CARTESIAN_POINT('',(10.1336492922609,30.5951058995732,27.937066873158));
#940=CARTESIAN_POINT('',(10.2200912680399,30.3001473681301,27.9054729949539));
#941=CARTESIAN_POINT('',(10.3649707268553,29.7131592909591,27.8519778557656));
#942=CARTESIAN_POINT('',(10.4242515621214,29.4213643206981,27.829786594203));
#943=CARTESIAN_POINT('',(10.5183821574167,28.8333193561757,27.7943465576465));
#944=CARTESIAN_POINT('',(10.5532324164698,28.5370694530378,27.7810975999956));
#945=CARTESIAN_POINT('',(10.5981301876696,27.9425110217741,27.7640007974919));
#946=CARTESIAN_POINT('',(10.6081848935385,27.6442031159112,27.7601502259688));
#947=CARTESIAN_POINT('',(10.6034035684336,27.0478212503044,27.7619769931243));
#948=CARTESIAN_POINT('',(10.5885683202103,26.7497472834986,27.7676540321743));
#949=CARTESIAN_POINT('',(10.5355294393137,26.1710252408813,27.7878190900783));
#950=CARTESIAN_POINT('',(10.4985291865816,25.8902499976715,27.8018531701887));
#951=CARTESIAN_POINT('',(10.4025599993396,25.3330133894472,27.8379039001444));
#952=CARTESIAN_POINT('',(10.3435918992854,25.0565518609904,27.8599202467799));
#953=CARTESIAN_POINT('',(10.2042194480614,24.5098132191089,27.911268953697));
#954=CARTESIAN_POINT('',(10.1238167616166,24.2395356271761,27.9406007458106));
#955=CARTESIAN_POINT('',(9.94220977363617,23.7067585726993,28.0057367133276));
#956=CARTESIAN_POINT('',(9.84099754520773,23.4442621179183,28.0415433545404));
#957=CARTESIAN_POINT('',(9.61661885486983,22.9242137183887,28.1192905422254));
#958=CARTESIAN_POINT('',(9.49309926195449,22.6668286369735,28.1613274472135));
#959=CARTESIAN_POINT('',(9.22619757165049,22.163275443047,28.2498950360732));
#960=CARTESIAN_POINT('',(9.08280869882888,21.9171111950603,28.2964272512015));
#961=CARTESIAN_POINT('',(8.77713295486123,21.4374498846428,28.3927302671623));
#962=CARTESIAN_POINT('',(8.6148443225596,21.2039540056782,28.4425013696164));
#963=CARTESIAN_POINT('',(8.27236355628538,20.7509290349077,28.5439909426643));
#964=CARTESIAN_POINT('',(8.09217073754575,20.5314004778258,28.5957094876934));
#965=CARTESIAN_POINT('',(7.7042553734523,20.0955554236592,28.7027297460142));
#966=CARTESIAN_POINT('',(7.49555319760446,19.8801189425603,28.7580689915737));
#967=CARTESIAN_POINT('',(7.06065147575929,19.4676197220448,28.867923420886));
#968=CARTESIAN_POINT('',(6.83445752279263,19.2705511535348,28.9224388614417));
#969=CARTESIAN_POINT('',(6.36574964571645,18.8959350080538,29.0292015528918));
#970=CARTESIAN_POINT('',(6.12322792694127,18.718396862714,29.0814477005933));
#971=CARTESIAN_POINT('',(5.62353927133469,18.3843064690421,29.1821906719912));
#972=CARTESIAN_POINT('',(5.36637837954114,18.2277456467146,29.2306890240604));
#973=CARTESIAN_POINT('',(4.83729568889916,17.9358519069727,29.3229029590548));
#974=CARTESIAN_POINT('',(4.56529168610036,17.8006577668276,29.3665867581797));
#975=CARTESIAN_POINT('',(4.00984816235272,17.5538714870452,29.4475703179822));
#976=CARTESIAN_POINT('',(3.72640851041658,17.4422796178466,29.4848700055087));
#977=CARTESIAN_POINT('',(3.15024705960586,17.243803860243,29.551980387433));
#978=CARTESIAN_POINT('',(2.85752853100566,17.1569113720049,29.5817936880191));
#979=CARTESIAN_POINT('',(2.26497523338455,17.008685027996,29.6330528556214));
#980=CARTESIAN_POINT('',(1.96514086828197,16.9473497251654,29.6544991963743));
#981=CARTESIAN_POINT('',(1.37692945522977,16.8534805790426,29.68746673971));
#982=CARTESIAN_POINT('',(1.08879555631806,16.8195836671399,29.6994567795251));
#983=CARTESIAN_POINT('',(0.510492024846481,16.7756322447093,29.715022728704));
#984=CARTESIAN_POINT('',(0.220322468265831,16.7655768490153,29.7185989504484));
#985=CARTESIAN_POINT('',(-0.359771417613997,16.7694117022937,29.7172374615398));
#986=CARTESIAN_POINT('',(-0.649695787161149,16.7832966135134,29.7123016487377));
#987=CARTESIAN_POINT('',(-1.22715260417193,16.8348575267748,29.6940577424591));
#988=CARTESIAN_POINT('',(-1.51468507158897,16.8725333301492,29.6807497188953));
#989=CARTESIAN_POINT('',(-2.07545456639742,16.969602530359,29.6467235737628));
#990=CARTESIAN_POINT('',(-2.34884445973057,17.0282103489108,29.6262740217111));
#991=CARTESIAN_POINT('',(-2.88953685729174,17.1667216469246,29.5784340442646));
#992=CARTESIAN_POINT('',(-3.15683961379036,17.2466242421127,29.5510439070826));
#993=CARTESIAN_POINT('',(-3.68373476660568,17.4270662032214,29.4899980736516));
#994=CARTESIAN_POINT('',(-3.94332478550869,17.5276118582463,29.4563404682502));
#995=CARTESIAN_POINT('',(-4.45315323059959,17.7485215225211,29.383588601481));
#996=CARTESIAN_POINT('',(-4.70339074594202,17.8688874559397,29.3444938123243));
#997=CARTESIAN_POINT('',(-5.22210445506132,18.1439423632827,29.2569012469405));
#998=CARTESIAN_POINT('',(-5.48922760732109,18.3010084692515,29.2078381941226));
#999=CARTESIAN_POINT('',(-6.00816795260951,18.637492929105,29.1055221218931));
#1000=CARTESIAN_POINT('',(-6.2599835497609,18.8169136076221,29.0522686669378));
#1001=CARTESIAN_POINT('',(-6.74670086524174,19.1967346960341,28.9431126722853));
#1002=CARTESIAN_POINT('',(-6.98160005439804,19.3971382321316,28.8872097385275));
#1003=CARTESIAN_POINT('',(-7.43302973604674,19.8175411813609,28.7743593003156));
#1004=CARTESIAN_POINT('',(-7.64955418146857,20.0375469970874,28.7174114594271));
#1005=CARTESIAN_POINT('',(-7.85615249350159,20.2665766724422,28.6607814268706));
#1006=B_SPLINE_CURVE_WITH_KNOTS('',3,(#852,#853,#854,#855,#856,#857,#858,#859,#860,#861,#862,
#863,#864,#865,#866,#867,#868,#869,#870,#871,#872,#873,#874,#875,#876,#877,#878,#879,#880,#881,
#882,#883,#884,#885,#886,#887,#888,#889,#890,#891,#892,#893,#894,#895,#896,#897,#898,#899,#900,
#901,#902,#903,#904,#905,#906,#907,#908,#909,#910,#911,#912,#913,#914,#915,#916,#917,#918,#919,
#920,#921,#922,#923,#924,#925,#926,#927,#928,#929,#930,#931,#932,#933,#934,#935,#936,#937,#938,
#939,#940,#941,#942,#943,#944,#945,#946,#947,#948,#949,#950,#951,#952,#953,#954,#955,#956,#957,
#958,#959,#960,#961,#962,#963,#964,#965,#966,#967,#968,#969,#970,#971,#972,#973,#974,#975,#976,
#977,#978,#979,#980,#981,#982,#983,#984,#985,#986,#987,#988,#989,#990,#991,#992,#993,#994,#995,
#996,#997,#998,#999,#1000,#1001,#1002,#1003,#1004,#1005),.UNSPECIFIED.,.T.,.F.,(4,2,2,2,2,2,2,2,
2,2,2,2,2,2,2,2,2,2,2,2,2,2,2,2,2,2,2,2,2,2,2,2,2,2,2,2,2,2,2,2,2,2,2,2,2,2,2,2,2,2,2,2,2,2,2,2,
2,2,2,2,2,2,2,2,2,2,2,2,2,2,2,2,2,2,2,2,4),(0.,0.902527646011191,1.80503125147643,
2.70747111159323,3.60957679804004,4.51409059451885,5.41860480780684,6.32285190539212,
7.22706061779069,8.0926605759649,8.95823564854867,9.82378395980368,10.6893350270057,
11.5387553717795,12.3884771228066,13.2381867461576,14.0879565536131,14.9793010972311,
15.8706692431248,16.7622888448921,17.6538915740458,18.5799411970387,19.505631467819,
20.4313449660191,21.357016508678,22.2531201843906,23.1492084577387,24.0450071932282,
24.9407700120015,25.7883791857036,26.6359536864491,27.4835162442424,28.331093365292,
29.1786876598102,30.0265857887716,30.8744844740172,31.7224430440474,32.6152049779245,
33.5079937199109,34.4010580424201,35.2941043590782,36.2202594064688,37.1460518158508,
38.0717978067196,38.9974992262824,39.8920974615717,40.7866774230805,41.6809978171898,
42.5752900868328,43.4249443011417,44.2745662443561,45.1241222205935,45.9740024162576,
46.8387521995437,47.7037975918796,48.5689236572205,49.4340828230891,50.3480537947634,
51.2617337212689,52.175852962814,53.0895974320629,54.0090523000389,54.9285177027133,
55.8476625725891,56.7667553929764,57.636769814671,58.5067519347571,59.3765401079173,
60.2463210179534,61.0863994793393,61.9264430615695,62.7667429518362,63.6071244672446,
64.5470999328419,65.4871732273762,66.4273867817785,67.3679085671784),.UNSPECIFIED.);
#1007=CARTESIAN_POINT('',(-7.85615249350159,20.2665766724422,28.6607814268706));
#1008=VERTEX_POINT('',#1007);
#1009=EDGE_CURVE('E866',#1008,#1008,#1006,.T.);
#1010=ORIENTED_EDGE('',*,*,#1009,.T.);
#1011=EDGE_LOOP('',(#1010));
#1012=FACE_BOUND('',#1011,.T.);
#1013=CARTESIAN_POINT('',(0.,55.88,0.));
#1014=DIRECTION('',(0.,-1.,0.));
#1015=DIRECTION('',(0.,0.,-1.));
#1016=AXIS2_PLACEMENT_3D('',#1013,#1014,#1015);
#1017=CIRCLE('',#1016,29.718);
#1018=CARTESIAN_POINT('',(0.,55.88,-29.718));
#1019=VERTEX_POINT('',#1018);
#1020=EDGE_CURVE('E863',#1019,#1019,#1017,.T.);
#1021=ORIENTED_EDGE('',*,*,#1020,.T.);
#1022=EDGE_LOOP('',(#1021));
#1023=FACE_BOUND('',#1022,.T.);
#1024=ADVANCED_FACE('F878',(#690,#851,#1012,#1023),#679,.T.);
#1025=CARTESIAN_POINT('',(0.,0.,0.));
#1026=DIRECTION('',(0.,1.,0.));
#1027=DIRECTION('',(0.,0.,1.));
#1028=AXIS2_PLACEMENT_3D('',#1025,#1026,#1027);
#1029=PLANE('',#1028);
#1030=CARTESIAN_POINT('',(0.,0.,0.));
#1031=DIRECTION('',(0.,1.,0.));
#1032=DIRECTION('',(0.,0.,1.));
#1033=AXIS2_PLACEMENT_3D('',#1030,#1031,#1032);
#1034=CIRCLE('',#1033,28.194);
#1035=CARTESIAN_POINT('',(0.,0.,28.194));
#1036=VERTEX_POINT('',#1035);
#1037=EDGE_CURVE('E1061',#1036,#1036,#1034,.F.);
#1038=ORIENTED_EDGE('',*,*,#1037,.T.);
#1039=EDGE_LOOP('',(#1038));
#1040=FACE_BOUND('',#1039,.T.);
#1041=ADVANCED_FACE('F926',(#1040),#1029,.F.);
#1042=CARTESIAN_POINT('',(-29.718,55.88,0.));
#1043=DIRECTION('',(0.,1.,0.));
#1044=DIRECTION('',(0.,0.,1.));
#1045=AXIS2_PLACEMENT_3D('',#1042,#1043,#1044);
#1046=PLANE('',#1045);
#1047=CARTESIAN_POINT('',(0.,55.88,0.));
#1048=DIRECTION('',(0.,-1.,0.));
#1049=DIRECTION('',(0.,0.,-1.));
#1050=AXIS2_PLACEMENT_3D('',#1047,#1048,#1049);
#1051=CIRCLE('',#1050,20.6254667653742);
#1052=CARTESIAN_POINT('',(0.,55.88,-20.6254667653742));
#1053=VERTEX_POINT('',#1052);
#1054=EDGE_CURVE('E860',#1053,#1053,#1051,.T.);
#1055=ORIENTED_EDGE('',*,*,#1054,.T.);
#1056=EDGE_LOOP('',(#1055));
#1057=FACE_BOUND('',#1056,.T.);
#1058=ORIENTED_EDGE('',*,*,#1020,.F.);
#1059=EDGE_LOOP('',(#1058));
#1060=FACE_BOUND('',#1059,.T.);
#1061=ADVANCED_FACE('F1784',(#1057,#1060),#1046,.T.);
#1062=CARTESIAN_POINT('',(0.,0.,0.));
#1063=DIRECTION('',(0.,-1.,0.));
#1064=DIRECTION('',(0.,0.,-1.));
#1065=AXIS2_PLACEMENT_3D('',#1062,#1063,#1064);
#1066=CYLINDRICAL_SURFACE('',#1065,20.6254667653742);
#1067=CARTESIAN_POINT('',(0.,56.134,0.));
#1068=DIRECTION('',(0.,-1.,0.));
#1069=DIRECTION('',(0.,0.,-1.));
#1070=AXIS2_PLACEMENT_3D('',#1067,#1068,#1069);
#1071=CIRCLE('',#1070,20.6254667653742);
#1072=CARTESIAN_POINT('',(0.,56.134,-20.6254667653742));
#1073=VERTEX_POINT('',#1072);
#1074=EDGE_CURVE('E857',#1073,#1073,#1071,.T.);
#1075=ORIENTED_EDGE('',*,*,#1074,.T.);
#1076=EDGE_LOOP('',(#1075));
#1077=FACE_BOUND('',#1076,.T.);
#1078=ORIENTED_EDGE('',*,*,#1054,.F.);
#1079=EDGE_LOOP('',(#1078));
#1080=FACE_BOUND('',#1079,.T.);
#1081=ADVANCED_FACE('F1866',(#1077,#1080),#1066,.T.);
#1082=CARTESIAN_POINT('',(-20.6254667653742,56.134,0.));
#1083=DIRECTION('',(0.,-1.,0.));
#1084=DIRECTION('',(0.,0.,-1.));
#1085=AXIS2_PLACEMENT_3D('',#1082,#1083,#1084);
#1086=PLANE('',#1085);
#1087=CARTESIAN_POINT('',(0.,56.134,0.));
#1088=DIRECTION('',(0.,-1.,0.));
#1089=DIRECTION('',(0.,0.,-1.));
#1090=AXIS2_PLACEMENT_3D('',#1087,#1088,#1089);
#1091=CIRCLE('',#1090,29.718);
#1092=CARTESIAN_POINT('',(0.,56.134,-29.718));
#1093=VERTEX_POINT('',#1092);
#1094=EDGE_CURVE('E853',#1093,#1093,#1091,.T.);
#1095=ORIENTED_EDGE('',*,*,#1094,.T.);
#1096=EDGE_LOOP('',(#1095));
#1097=FACE_BOUND('',#1096,.T.);
#1098=ORIENTED_EDGE('',*,*,#1074,.F.);
#1099=EDGE_LOOP('',(#1098));
#1100=FACE_BOUND('',#1099,.T.);
#1101=ADVANCED_FACE('F917',(#1097,#1100),#1086,.T.);
#1102=EDGE_CURVE('E850',#517,#363,#45,.T.);
#1103=ORIENTED_EDGE('',*,*,#1102,.T.);
#1104=ORIENTED_EDGE('',*,*,#364,.T.);
#1105=EDGE_CURVE('E1359',#359,#205,#45,.T.);
#1106=ORIENTED_EDGE('',*,*,#1105,.T.);
#1107=ORIENTED_EDGE('',*,*,#206,.T.);
#1108=EDGE_CURVE('E947',#201,#47,#45,.T.);
#1109=ORIENTED_EDGE('',*,*,#1108,.T.);
#1110=ORIENTED_EDGE('',*,*,#48,.T.);
#1111=EDGE_CURVE('E945',#36,#521,#45,.T.);
#1112=ORIENTED_EDGE('',*,*,#1111,.T.);
#1113=ORIENTED_EDGE('',*,*,#522,.T.);
#1114=EDGE_LOOP('',(#1103,#1104,#1106,#1107,#1109,#1110,#1112,#1113));
#1115=FACE_BOUND('',#1114,.T.);
#1116=ORIENTED_EDGE('',*,*,#1094,.F.);
#1117=EDGE_LOOP('',(#1116));
#1118=FACE_BOUND('',#1117,.T.);
#1119=ADVANCED_FACE('F909',(#1115,#1118),#679,.T.);
#1120=CARTESIAN_POINT('',(0.,0.,0.));
#1121=DIRECTION('',(0.,-1.,0.));
#1122=DIRECTION('',(0.,0.,-1.));
#1123=AXIS2_PLACEMENT_3D('',#1120,#1121,#1122);
#1124=CYLINDRICAL_SURFACE('',#1123,15.875);
#1125=CARTESIAN_POINT('',(0.,104.14,0.));
#1126=DIRECTION('',(0.,1.,0.));
#1127=DIRECTION('',(0.,0.,1.));
#1128=AXIS2_PLACEMENT_3D('',#1125,#1126,#1127);
#1129=CIRCLE('',#1128,15.875);
#1130=CARTESIAN_POINT('',(0.,104.14,15.875));
#1131=VERTEX_POINT('',#1130);
#1132=EDGE_CURVE('E1052',#1131,#1131,#1129,.F.);
#1133=ORIENTED_EDGE('',*,*,#1132,.T.);
#1134=EDGE_LOOP('',(#1133));
#1135=FACE_BOUND('',#1134,.T.);
#1136=ORIENTED_EDGE('',*,*,#670,.F.);
#1137=EDGE_LOOP('',(#1136));
#1138=FACE_BOUND('',#1137,.T.);
#1139=ADVANCED_FACE('F907',(#1135,#1138),#1124,.T.);
#1140=CARTESIAN_POINT('',(0.,105.41,0.));
#1141=DIRECTION('',(0.,1.,0.));
#1142=DIRECTION('',(0.,0.,1.));
#1143=AXIS2_PLACEMENT_3D('',#1140,#1141,#1142);
#1144=PLANE('',#1143);
#1145=CARTESIAN_POINT('',(0.,105.41,0.));
#1146=DIRECTION('',(0.,1.,0.));
#1147=DIRECTION('',(0.,0.,1.));
#1148=AXIS2_PLACEMENT_3D('',#1145,#1146,#1147);
#1149=CIRCLE('',#1148,14.605);
#1150=CARTESIAN_POINT('',(0.,105.41,14.605));
#1151=VERTEX_POINT('',#1150);
#1152=EDGE_CURVE('E1053',#1151,#1151,#1149,.T.);
#1153=ORIENTED_EDGE('',*,*,#1152,.T.);
#1154=EDGE_LOOP('',(#1153));
#1155=FACE_BOUND('',#1154,.T.);
#1156=CARTESIAN_POINT('',(0.,105.41,0.));
#1157=DIRECTION('',(0.,1.,0.));
#1158=DIRECTION('',(0.,0.,1.));
#1159=AXIS2_PLACEMENT_3D('',#1156,#1157,#1158);
#1160=CIRCLE('',#1159,10.16);
#1161=CARTESIAN_POINT('',(0.,105.41,10.16));
#1162=VERTEX_POINT('',#1161);
#1163=EDGE_CURVE('E840',#1162,#1162,#1160,.T.);
#1164=ORIENTED_EDGE('',*,*,#1163,.F.);
#1165=EDGE_LOOP('',(#1164));
#1166=FACE_BOUND('',#1165,.T.);
#1167=ADVANCED_FACE('F905',(#1155,#1166),#1144,.T.);
#1168=CARTESIAN_POINT('',(0.,105.41,0.));
#1169=DIRECTION('',(0.,1.,0.));
#1170=DIRECTION('',(0.,0.,1.));
#1171=AXIS2_PLACEMENT_3D('',#1168,#1169,#1170);
#1172=CONICAL_SURFACE('',#1171,10.16,0.78539816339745);
#1173=CARTESIAN_POINT('',(0.,104.14,0.));
#1174=DIRECTION('',(0.,1.,0.));
#1175=DIRECTION('',(0.,0.,1.));
#1176=AXIS2_PLACEMENT_3D('',#1173,#1174,#1175);
#1177=CIRCLE('',#1176,8.89);
#1178=CARTESIAN_POINT('',(0.,104.14,8.89));
#1179=VERTEX_POINT('',#1178);
#1180=EDGE_CURVE('E843',#1179,#1179,#1177,.T.);
#1181=ORIENTED_EDGE('',*,*,#1180,.F.);
#1182=EDGE_LOOP('',(#1181));
#1183=FACE_BOUND('',#1182,.T.);
#1184=ORIENTED_EDGE('',*,*,#1163,.T.);
#1185=EDGE_LOOP('',(#1184));
#1186=FACE_BOUND('',#1185,.T.);
#1187=ADVANCED_FACE('F888',(#1183,#1186),#1172,.F.);
#1188=CARTESIAN_POINT('',(0.,27.432,29.718));
#1189=DIRECTION('',(0.,0.,1.));
#1190=DIRECTION('',(1.,0.,0.));
#1191=AXIS2_PLACEMENT_3D('',#1188,#1189,#1190);
#1192=CONICAL_SURFACE('',#1191,10.6647361,0.0299323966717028);
#1193=CARTESIAN_POINT('',(0.,27.432,16.256));
#1194=DIRECTION('',(0.,0.,1.));
#1195=DIRECTION('',(1.,0.,0.));
#1196=AXIS2_PLACEMENT_3D('',#1193,#1194,#1195);
#1197=CIRCLE('',#1196,10.2616657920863);
#1198=CARTESIAN_POINT('',(10.2616657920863,27.432,16.256));
#1199=VERTEX_POINT('',#1198);
#1200=EDGE_CURVE('E831',#1199,#1199,#1197,.T.);
#1201=ORIENTED_EDGE('',*,*,#1200,.F.);
#1202=EDGE_LOOP('',(#1201));
#1203=FACE_BOUND('',#1202,.T.);
#1204=ORIENTED_EDGE('',*,*,#1009,.F.);
#1205=EDGE_LOOP('',(#1204));
#1206=FACE_BOUND('',#1205,.T.);
#1207=ADVANCED_FACE('F882',(#1203,#1206),#1192,.F.);
#1208=CARTESIAN_POINT('',(0.,27.432,13.208));
#1209=DIRECTION('',(0.,0.,1.));
#1210=DIRECTION('',(1.,0.,0.));
#1211=AXIS2_PLACEMENT_3D('',#1208,#1209,#1210);
#1212=CONICAL_SURFACE('',#1211,8.9281,1.17809724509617);
#1213=CARTESIAN_POINT('',(0.,27.432,9.50985989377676));
#1214=VERTEX_POINT('',#1213);
#1215=VERTEX_LOOP('',#1214);
#1216=FACE_BOUND('',#1215,.T.);
#1217=CARTESIAN_POINT('',(0.,27.432,13.208));
#1218=DIRECTION('',(0.,0.,1.));
#1219=DIRECTION('',(1.,0.,0.));
#1220=AXIS2_PLACEMENT_3D('',#1217,#1218,#1219);
#1221=CIRCLE('',#1220,8.9281);
#1222=CARTESIAN_POINT('',(8.9281,27.432,13.208));
#1223=VERTEX_POINT('',#1222);
#1224=EDGE_CURVE('E837',#1223,#1223,#1221,.T.);
#1225=ORIENTED_EDGE('',*,*,#1224,.T.);
#1226=EDGE_LOOP('',(#1225));
#1227=FACE_BOUND('',#1226,.T.);
#1228=ADVANCED_FACE('F887',(#1216,#1227),#1212,.F.);
#1229=CARTESIAN_POINT('',(0.,27.432,29.718));
#1230=DIRECTION('',(0.,0.,1.));
#1231=DIRECTION('',(1.,0.,0.));
#1232=AXIS2_PLACEMENT_3D('',#1229,#1230,#1231);
#1233=CYLINDRICAL_SURFACE('',#1232,8.9281);
#1234=ORIENTED_EDGE('',*,*,#1224,.F.);
#1235=EDGE_LOOP('',(#1234));
#1236=FACE_BOUND('',#1235,.T.);
#1237=CARTESIAN_POINT('',(0.,27.432,16.256));
#1238=DIRECTION('',(0.,0.,1.));
#1239=DIRECTION('',(1.,0.,0.));
#1240=AXIS2_PLACEMENT_3D('',#1237,#1238,#1239);
#1241=CIRCLE('',#1240,8.9281);
#1242=CARTESIAN_POINT('',(8.9281,27.432,16.256));
#1243=VERTEX_POINT('',#1242);
#1244=EDGE_CURVE('E834',#1243,#1243,#1241,.T.);
#1245=ORIENTED_EDGE('',*,*,#1244,.T.);
#1246=EDGE_LOOP('',(#1245));
#1247=FACE_BOUND('',#1246,.T.);
#1248=ADVANCED_FACE('F896',(#1236,#1247),#1233,.F.);
#1249=CARTESIAN_POINT('',(8.9281,27.432,16.256));
#1250=DIRECTION('',(0.,0.,-1.));
#1251=DIRECTION('',(-1.,0.,0.));
#1252=AXIS2_PLACEMENT_3D('',#1249,#1250,#1251);
#1253=PLANE('',#1252);
#1254=ORIENTED_EDGE('',*,*,#1244,.F.);
#1255=EDGE_LOOP('',(#1254));
#1256=FACE_BOUND('',#1255,.T.);
#1257=ORIENTED_EDGE('',*,*,#1200,.T.);
#1258=EDGE_LOOP('',(#1257));
#1259=FACE_BOUND('',#1258,.T.);
#1260=ADVANCED_FACE('F892',(#1256,#1259),#1253,.F.);
#1261=CARTESIAN_POINT('',(2.07519805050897E-13,27.432,-29.718));
#1262=DIRECTION('',(0.,0.,-1.));
#1263=DIRECTION('',(-1.,0.,0.));
#1264=AXIS2_PLACEMENT_3D('',#1261,#1262,#1263);
#1265=CONICAL_SURFACE('',#1264,10.6647361,0.0299323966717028);
#1266=CARTESIAN_POINT('',(2.07519805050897E-13,27.432,-16.256));
#1267=DIRECTION('',(0.,0.,-1.));
#1268=DIRECTION('',(-1.,0.,0.));
#1269=AXIS2_PLACEMENT_3D('',#1266,#1267,#1268);
#1270=CIRCLE('',#1269,10.2616657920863);
#1271=CARTESIAN_POINT('',(-10.2616657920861,27.432,-16.256));
#1272=VERTEX_POINT('',#1271);
#1273=EDGE_CURVE('E816',#1272,#1272,#1270,.T.);
#1274=ORIENTED_EDGE('',*,*,#1273,.F.);
#1275=EDGE_LOOP('',(#1274));
#1276=FACE_BOUND('',#1275,.T.);
#1277=ORIENTED_EDGE('',*,*,#848,.F.);
#1278=EDGE_LOOP('',(#1277));
#1279=FACE_BOUND('',#1278,.T.);
#1280=ADVANCED_FACE('F895',(#1276,#1279),#1265,.F.);
#1281=CARTESIAN_POINT('',(2.07519805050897E-13,27.432,-13.208));
#1282=DIRECTION('',(0.,0.,-1.));
#1283=DIRECTION('',(-1.,0.,0.));
#1284=AXIS2_PLACEMENT_3D('',#1281,#1282,#1283);
#1285=CONICAL_SURFACE('',#1284,8.9281,1.17809724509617);
#1286=CARTESIAN_POINT('',(2.07519805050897E-13,27.432,-9.50985989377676));
#1287=VERTEX_POINT('',#1286);
#1288=VERTEX_LOOP('',#1287);
#1289=FACE_BOUND('',#1288,.T.);
#1290=CARTESIAN_POINT('',(2.07519805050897E-13,27.432,-13.208));
#1291=DIRECTION('',(0.,0.,-1.));
#1292=DIRECTION('',(-1.,0.,0.));
#1293=AXIS2_PLACEMENT_3D('',#1290,#1291,#1292);
#1294=CIRCLE('',#1293,8.9281);
#1295=CARTESIAN_POINT('',(-8.92809999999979,27.432,-13.208));
#1296=VERTEX_POINT('',#1295);
#1297=EDGE_CURVE('E828',#1296,#1296,#1294,.T.);
#1298=ORIENTED_EDGE('',*,*,#1297,.T.);
#1299=EDGE_LOOP('',(#1298));
#1300=FACE_BOUND('',#1299,.T.);
#1301=ADVANCED_FACE('F890',(#1289,#1300),#1285,.F.);
#1302=CARTESIAN_POINT('',(2.07519805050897E-13,27.432,-29.718));
#1303=DIRECTION('',(0.,0.,-1.));
#1304=DIRECTION('',(-1.,0.,0.));
#1305=AXIS2_PLACEMENT_3D('',#1302,#1303,#1304);
#1306=CYLINDRICAL_SURFACE('',#1305,8.9281);
#1307=ORIENTED_EDGE('',*,*,#1297,.F.);
#1308=EDGE_LOOP('',(#1307));
#1309=FACE_BOUND('',#1308,.T.);
#1310=CARTESIAN_POINT('',(2.07519805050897E-13,27.432,-16.256));
#1311=DIRECTION('',(0.,0.,-1.));
#1312=DIRECTION('',(-1.,0.,0.));
#1313=AXIS2_PLACEMENT_3D('',#1310,#1311,#1312);
#1314=CIRCLE('',#1313,8.9281);
#1315=CARTESIAN_POINT('',(-8.92809999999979,27.432,-16.256));
#1316=VERTEX_POINT('',#1315);
#1317=EDGE_CURVE('E825',#1316,#1316,#1314,.T.);
#1318=ORIENTED_EDGE('',*,*,#1317,.T.);
#1319=EDGE_LOOP('',(#1318));
#1320=FACE_BOUND('',#1319,.T.);
#1321=ADVANCED_FACE('F1035',(#1309,#1320),#1306,.F.);
#1322=CARTESIAN_POINT('',(8.92810000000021,27.432,-16.256));
#1323=DIRECTION('',(0.,0.,1.));
#1324=DIRECTION('',(1.,0.,0.));
#1325=AXIS2_PLACEMENT_3D('',#1322,#1323,#1324);
#1326=PLANE('',#1325);
#1327=ORIENTED_EDGE('',*,*,#1317,.F.);
#1328=EDGE_LOOP('',(#1327));
#1329=FACE_BOUND('',#1328,.T.);
#1330=ORIENTED_EDGE('',*,*,#1273,.T.);
#1331=EDGE_LOOP('',(#1330));
#1332=FACE_BOUND('',#1331,.T.);
#1333=ADVANCED_FACE('F1032',(#1329,#1332),#1326,.F.);
#1334=CARTESIAN_POINT('',(0.,104.14,0.));
#1335=DIRECTION('',(0.,-1.,0.));
#1336=DIRECTION('',(0.,0.,-1.));
#1337=AXIS2_PLACEMENT_3D('',#1334,#1335,#1336);
#1338=CONICAL_SURFACE('',#1337,15.875,0.785398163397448);
#1339=ORIENTED_EDGE('',*,*,#1152,.F.);
#1340=EDGE_LOOP('',(#1339));
#1341=FACE_BOUND('',#1340,.T.);
#1342=ORIENTED_EDGE('',*,*,#1132,.F.);
#1343=EDGE_LOOP('',(#1342));
#1344=FACE_BOUND('',#1343,.T.);
#1345=ADVANCED_FACE('F1034',(#1341,#1344),#1338,.T.);
#1346=CARTESIAN_POINT('',(0.,1.52399999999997,0.));
#1347=DIRECTION('',(0.,1.,0.));
#1348=DIRECTION('',(0.,0.,1.));
#1349=AXIS2_PLACEMENT_3D('',#1346,#1347,#1348);
#1350=CONICAL_SURFACE('',#1349,29.718,0.785398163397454);
#1351=ORIENTED_EDGE('',*,*,#1037,.F.);
#1352=EDGE_LOOP('',(#1351));
#1353=FACE_BOUND('',#1352,.T.);
#1354=ORIENTED_EDGE('',*,*,#687,.F.);
#1355=EDGE_LOOP('',(#1354));
#1356=FACE_BOUND('',#1355,.T.);
#1357=ADVANCED_FACE('F1026',(#1353,#1356),#1350,.T.);
#1358=CARTESIAN_POINT('',(0.,78.9952828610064,0.));
#1359=DIRECTION('',(0.,1.,0.));
#1360=DIRECTION('',(0.,0.,1.));
#1361=AXIS2_PLACEMENT_3D('',#1358,#1359,#1360);
#1362=CYLINDRICAL_SURFACE('',#1361,8.89);
#1363=CARTESIAN_POINT('',(0.,104.648,0.));
#1364=DIRECTION('',(0.,1.,0.));
#1365=DIRECTION('',(0.,0.,1.));
#1366=AXIS2_PLACEMENT_3D('',#1363,#1364,#1365);
#1367=CIRCLE('',#1366,8.89);
#1368=CARTESIAN_POINT('',(0.,104.648,-8.89000000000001));
#1369=VERTEX_POINT('',#1368);
#1370=EDGE_CURVE('E981',#1369,#1369,#1367,.F.);
#1371=ORIENTED_EDGE('',*,*,#1370,.T.);
#1372=EDGE_LOOP('',(#1371));
#1373=FACE_BOUND('',#1372,.T.);
#1374=ORIENTED_EDGE('',*,*,#1180,.T.);
#1375=EDGE_LOOP('',(#1374));
#1376=FACE_BOUND('',#1375,.T.);
#1377=ADVANCED_FACE('F1023',(#1373,#1376),#1362,.T.);
#1378=CARTESIAN_POINT('',(0.,105.41,0.));
#1379=DIRECTION('',(0.,1.,0.));
#1380=DIRECTION('',(0.,0.,1.));
#1381=AXIS2_PLACEMENT_3D('',#1378,#1379,#1380);
#1382=PLANE('',#1381);
#1383=CARTESIAN_POINT('',(3.175,105.41,0.));
#1384=DIRECTION('',(0.,1.,0.));
#1385=DIRECTION('',(0.,0.,1.));
#1386=AXIS2_PLACEMENT_3D('',#1383,#1384,#1385);
#1387=CIRCLE('',#1386,0.9652);
#1388=CARTESIAN_POINT('',(3.175,105.41,0.9652));
#1389=VERTEX_POINT('',#1388);
#1390=CARTESIAN_POINT('',(3.175,105.41,-0.9652));
#1391=VERTEX_POINT('',#1390);
#1392=EDGE_CURVE('E790',#1389,#1391,#1387,.T.);
#1393=ORIENTED_EDGE('',*,*,#1392,.F.);
#1394=DIRECTION('',(1.,0.,0.));
#1395=VECTOR('',#1394,1.);
#1396=CARTESIAN_POINT('',(3.175,105.41,0.9652));
#1397=LINE('',#1396,#1395);
#1398=CARTESIAN_POINT('',(-3.175,105.41,0.9652));
#1399=VERTEX_POINT('',#1398);
#1400=EDGE_CURVE('E795',#1399,#1389,#1397,.T.);
#1401=ORIENTED_EDGE('',*,*,#1400,.F.);
#1402=CARTESIAN_POINT('',(-3.175,105.41,0.));
#1403=DIRECTION('',(0.,1.,0.));
#1404=DIRECTION('',(0.,0.,1.));
#1405=AXIS2_PLACEMENT_3D('',#1402,#1403,#1404);
#1406=CIRCLE('',#1405,0.9652);
#1407=CARTESIAN_POINT('',(-3.175,105.41,-0.9652));
#1408=VERTEX_POINT('',#1407);
#1409=EDGE_CURVE('E809',#1408,#1399,#1406,.T.);
#1410=ORIENTED_EDGE('',*,*,#1409,.F.);
#1411=DIRECTION('',(-1.,0.,0.));
#1412=VECTOR('',#1411,1.);
#1413=CARTESIAN_POINT('',(-3.175,105.41,-0.9652));
#1414=LINE('',#1413,#1412);
#1415=EDGE_CURVE('E806',#1391,#1408,#1414,.T.);
#1416=ORIENTED_EDGE('',*,*,#1415,.F.);
#1417=EDGE_LOOP('',(#1393,#1401,#1410,#1416));
#1418=FACE_BOUND('',#1417,.T.);
#1419=CARTESIAN_POINT('',(0.,105.41,0.));
#1420=DIRECTION('',(0.,1.,0.));
#1421=DIRECTION('',(0.,0.,1.));
#1422=AXIS2_PLACEMENT_3D('',#1419,#1420,#1421);
#1423=CIRCLE('',#1422,8.128);
#1424=CARTESIAN_POINT('',(0.,105.41,-8.128));
#1425=VERTEX_POINT('',#1424);
#1426=EDGE_CURVE('E1063',#1425,#1425,#1423,.T.);
#1427=ORIENTED_EDGE('',*,*,#1426,.T.);
#1428=EDGE_LOOP('',(#1427));
#1429=FACE_BOUND('',#1428,.T.);
#1430=ADVANCED_FACE('F1020',(#1418,#1429),#1382,.T.);
#1431=CARTESIAN_POINT('',(0.,105.41,0.));
#1432=DIRECTION('',(0.,-1.,0.));
#1433=DIRECTION('',(0.,0.,-1.));
#1434=AXIS2_PLACEMENT_3D('',#1431,#1432,#1433);
#1435=CONICAL_SURFACE('',#1434,8.128,0.785398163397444);
#1436=CARTESIAN_POINT('',(0.,104.648,-8.89000000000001));
#1437=CARTESIAN_POINT('',(0.,104.6559375,-8.88206250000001));
#1438=CARTESIAN_POINT('',(0.,104.663875,-8.87412500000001));
#1439=CARTESIAN_POINT('',(0.,104.67975,-8.85825000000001));
#1440=CARTESIAN_POINT('',(0.,104.6876875,-8.85031250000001));
#1441=CARTESIAN_POINT('',(0.,104.7035625,-8.83443750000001));
#1442=CARTESIAN_POINT('',(0.,104.7115,-8.82650000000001));
#1443=CARTESIAN_POINT('',(0.,104.727375,-8.81062500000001));
#1444=CARTESIAN_POINT('',(0.,104.7353125,-8.80268750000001));
#1445=CARTESIAN_POINT('',(0.,104.7511875,-8.78681250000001));
#1446=CARTESIAN_POINT('',(0.,104.759125,-8.77887500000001));
#1447=CARTESIAN_POINT('',(0.,104.775,-8.76300000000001));
#1448=CARTESIAN_POINT('',(0.,104.7829375,-8.75506250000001));
#1449=CARTESIAN_POINT('',(0.,104.7988125,-8.73918750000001));
#1450=CARTESIAN_POINT('',(0.,104.80675,-8.73125000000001));
#1451=CARTESIAN_POINT('',(0.,104.822625,-8.71537500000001));
#1452=CARTESIAN_POINT('',(0.,104.8305625,-8.70743750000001));
#1453=CARTESIAN_POINT('',(0.,104.8464375,-8.69156250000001));
#1454=CARTESIAN_POINT('',(0.,104.854375,-8.68362500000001));
#1455=CARTESIAN_POINT('',(0.,104.87025,-8.66775000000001));
#1456=CARTESIAN_POINT('',(0.,104.8781875,-8.65981250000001));
#1457=CARTESIAN_POINT('',(0.,104.8940625,-8.64393750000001));
#1458=CARTESIAN_POINT('',(0.,104.902,-8.63600000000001));
#1459=CARTESIAN_POINT('',(0.,104.917875,-8.62012500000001));
#1460=CARTESIAN_POINT('',(0.,104.9258125,-8.61218750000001));
#1461=CARTESIAN_POINT('',(0.,104.9416875,-8.59631250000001));
#1462=CARTESIAN_POINT('',(0.,104.949625,-8.58837500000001));
#1463=CARTESIAN_POINT('',(0.,104.9655,-8.57250000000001));
#1464=CARTESIAN_POINT('',(0.,104.9734375,-8.56456250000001));
#1465=CARTESIAN_POINT('',(0.,104.9893125,-8.54868750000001));
#1466=CARTESIAN_POINT('',(0.,104.99725,-8.54075000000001));
#1467=CARTESIAN_POINT('',(0.,105.013125,-8.52487500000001));
#1468=CARTESIAN_POINT('',(0.,105.0210625,-8.5169375));
#1469=CARTESIAN_POINT('',(0.,105.0369375,-8.50106250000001));
#1470=CARTESIAN_POINT('',(0.,105.044875,-8.49312500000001));
#1471=CARTESIAN_POINT('',(0.,105.06075,-8.47725000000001));
#1472=CARTESIAN_POINT('',(0.,105.0686875,-8.46931250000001));
#1473=CARTESIAN_POINT('',(0.,105.0845625,-8.45343750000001));
#1474=CARTESIAN_POINT('',(0.,105.0925,-8.4455));
#1475=CARTESIAN_POINT('',(0.,105.108375,-8.42962500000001));
#1476=CARTESIAN_POINT('',(0.,105.1163125,-8.42168750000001));
#1477=CARTESIAN_POINT('',(0.,105.1321875,-8.40581250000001));
#1478=CARTESIAN_POINT('',(0.,105.140125,-8.397875));
#1479=CARTESIAN_POINT('',(0.,105.156,-8.382));
#1480=CARTESIAN_POINT('',(0.,105.1639375,-8.37406250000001));
#1481=CARTESIAN_POINT('',(0.,105.1798125,-8.35818750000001));
#1482=CARTESIAN_POINT('',(0.,105.18775,-8.35025));
#1483=CARTESIAN_POINT('',(0.,105.203625,-8.334375));
#1484=CARTESIAN_POINT('',(0.,105.2115625,-8.3264375));
#1485=CARTESIAN_POINT('',(0.,105.2274375,-8.3105625));
#1486=CARTESIAN_POINT('',(0.,105.235375,-8.30262500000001));
#1487=CARTESIAN_POINT('',(0.,105.25125,-8.28675));
#1488=CARTESIAN_POINT('',(0.,105.2591875,-8.2788125));
#1489=CARTESIAN_POINT('',(0.,105.2750625,-8.2629375));
#1490=CARTESIAN_POINT('',(0.,105.283,-8.25500000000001));
#1491=CARTESIAN_POINT('',(0.,105.298875,-8.23912500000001));
#1492=CARTESIAN_POINT('',(0.,105.3068125,-8.23118750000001));
#1493=CARTESIAN_POINT('',(0.,105.3226875,-8.2153125));
#1494=CARTESIAN_POINT('',(0.,105.330625,-8.207375));
#1495=CARTESIAN_POINT('',(0.,105.3465,-8.1915));
#1496=CARTESIAN_POINT('',(0.,105.3544375,-8.1835625));
#1497=CARTESIAN_POINT('',(0.,105.3703125,-8.1676875));
#1498=CARTESIAN_POINT('',(0.,105.37825,-8.15975));
#1499=CARTESIAN_POINT('',(0.,105.394125,-8.143875));
#1500=CARTESIAN_POINT('',(0.,105.4020625,-8.1359375));
#1501=CARTESIAN_POINT('',(0.,105.41,-8.128));
#1502=B_SPLINE_CURVE_WITH_KNOTS('',3,(#1436,#1437,#1438,#1439,#1440,#1441,#1442,#1443,#1444,
#1445,#1446,#1447,#1448,#1449,#1450,#1451,#1452,#1453,#1454,#1455,#1456,#1457,#1458,#1459,#1460,
#1461,#1462,#1463,#1464,#1465,#1466,#1467,#1468,#1469,#1470,#1471,#1472,#1473,#1474,#1475,#1476,
#1477,#1478,#1479,#1480,#1481,#1482,#1483,#1484,#1485,#1486,#1487,#1488,#1489,#1490,#1491,#1492,
#1493,#1494,#1495,#1496,#1497,#1498,#1499,#1500,#1501),.UNSPECIFIED.,.F.,.F.,(4,2,2,2,2,2,2,2,2,
2,2,2,2,2,2,2,2,2,2,2,2,2,2,2,2,2,2,2,2,2,2,2,4),(0.,0.0336759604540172,0.0673519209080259,
0.101027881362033,0.134703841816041,0.168379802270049,0.202055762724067,0.235731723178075,
0.269407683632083,0.30308364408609,0.336759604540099,0.370435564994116,0.404111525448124,
0.437787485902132,0.47146344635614,0.505139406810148,0.538815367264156,0.572491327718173,
0.606167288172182,0.639843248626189,0.673519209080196,0.707195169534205,0.740871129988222,
0.774547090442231,0.808223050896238,0.841899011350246,0.875574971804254,0.909250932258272,
0.942926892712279,0.976602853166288,1.0102788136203,1.0439547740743,1.07763073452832),.UNSPECIFIED.);
#1503=EDGE_CURVE('BSEAM1018',#1369,#1425,#1502,.T.);
#1504=ORIENTED_EDGE('',*,*,#1370,.F.);
#1505=ORIENTED_EDGE('',*,*,#1426,.F.);
#1506=ORIENTED_EDGE('',*,*,#1503,.T.);
#1507=ORIENTED_EDGE('',*,*,#1503,.F.);
#1508=EDGE_LOOP('',(#1504,#1506,#1505,#1507));
#1509=FACE_BOUND('',#1508,.T.);
#1510=ADVANCED_FACE('F1018',(#1509),#1435,.T.);
#1511=CARTESIAN_POINT('',(3.175,100.6602,0.));
#1512=DIRECTION('',(0.,1.,0.));
#1513=DIRECTION('',(0.,0.,1.));
#1514=AXIS2_PLACEMENT_3D('',#1511,#1512,#1513);
#1515=CYLINDRICAL_SURFACE('',#1514,0.9652);
#1516=ORIENTED_EDGE('',*,*,#1392,.T.);
#1517=DIRECTION('',(0.,1.,0.));
#1518=VECTOR('',#1517,1.);
#1519=CARTESIAN_POINT('',(3.175,100.6602,-0.9652));
#1520=LINE('',#1519,#1518);
#1521=CARTESIAN_POINT('',(3.175,100.6602,-0.9652));
#1522=VERTEX_POINT('',#1521);
#1523=EDGE_CURVE('E804',#1522,#1391,#1520,.T.);
#1524=ORIENTED_EDGE('',*,*,#1523,.F.);
#1525=CARTESIAN_POINT('',(3.175,100.6602,0.));
#1526=DIRECTION('',(0.,1.,0.));
#1527=DIRECTION('',(0.,0.,1.));
#1528=AXIS2_PLACEMENT_3D('',#1525,#1526,#1527);
#1529=CIRCLE('',#1528,0.9652);
#1530=CARTESIAN_POINT('',(3.175,100.6602,0.9652));
#1531=VERTEX_POINT('',#1530);
#1532=EDGE_CURVE('E791',#1531,#1522,#1529,.T.);
#1533=ORIENTED_EDGE('',*,*,#1532,.F.);
#1534=DIRECTION('',(0.,1.,0.));
#1535=VECTOR('',#1534,1.);
#1536=CARTESIAN_POINT('',(3.175,100.6602,0.9652));
#1537=LINE('',#1536,#1535);
#1538=EDGE_CURVE('E814',#1531,#1389,#1537,.T.);
#1539=ORIENTED_EDGE('',*,*,#1538,.T.);
#1540=EDGE_LOOP('',(#1516,#1524,#1533,#1539));
#1541=FACE_BOUND('',#1540,.T.);
#1542=ADVANCED_FACE('F1008',(#1541),#1515,.F.);
#1543=CARTESIAN_POINT('',(3.175,100.6602,0.9652));
#1544=DIRECTION('',(0.,0.,1.));
#1545=DIRECTION('',(1.,0.,0.));
#1546=AXIS2_PLACEMENT_3D('',#1543,#1544,#1545);
#1547=PLANE('',#1546);
#1548=ORIENTED_EDGE('',*,*,#1400,.T.);
#1549=ORIENTED_EDGE('',*,*,#1538,.F.);
#1550=DIRECTION('',(1.,0.,0.));
#1551=VECTOR('',#1550,1.);
#1552=CARTESIAN_POINT('',(3.175,100.6602,0.9652));
#1553=LINE('',#1552,#1551);
#1554=CARTESIAN_POINT('',(-3.175,100.6602,0.9652));
#1555=VERTEX_POINT('',#1554);
#1556=EDGE_CURVE('E801',#1555,#1531,#1553,.T.);
#1557=ORIENTED_EDGE('',*,*,#1556,.F.);
#1558=DIRECTION('',(0.,1.,0.));
#1559=VECTOR('',#1558,1.);
#1560=CARTESIAN_POINT('',(-3.175,100.6602,0.9652));
#1561=LINE('',#1560,#1559);
#1562=EDGE_CURVE('E817',#1555,#1399,#1561,.T.);
#1563=ORIENTED_EDGE('',*,*,#1562,.T.);
#1564=EDGE_LOOP('',(#1548,#1549,#1557,#1563));
#1565=FACE_BOUND('',#1564,.T.);
#1566=ADVANCED_FACE('F1004',(#1565),#1547,.F.);
#1567=CARTESIAN_POINT('',(-3.175,100.6602,0.));
#1568=DIRECTION('',(0.,1.,0.));
#1569=DIRECTION('',(0.,0.,1.));
#1570=AXIS2_PLACEMENT_3D('',#1567,#1568,#1569);
#1571=CYLINDRICAL_SURFACE('',#1570,0.9652);
#1572=ORIENTED_EDGE('',*,*,#1409,.T.);
#1573=ORIENTED_EDGE('',*,*,#1562,.F.);
#1574=CARTESIAN_POINT('',(-3.175,100.6602,0.));
#1575=DIRECTION('',(0.,1.,0.));
#1576=DIRECTION('',(0.,0.,1.));
#1577=AXIS2_PLACEMENT_3D('',#1574,#1575,#1576);
#1578=CIRCLE('',#1577,0.9652);
#1579=CARTESIAN_POINT('',(-3.175,100.6602,-0.9652));
#1580=VERTEX_POINT('',#1579);
#1581=EDGE_CURVE('E798',#1580,#1555,#1578,.T.);
#1582=ORIENTED_EDGE('',*,*,#1581,.F.);
#1583=DIRECTION('',(0.,1.,0.));
#1584=VECTOR('',#1583,1.);
#1585=CARTESIAN_POINT('',(-3.175,100.6602,-0.9652));
#1586=LINE('',#1585,#1584);
#1587=EDGE_CURVE('E819',#1580,#1408,#1586,.T.);
#1588=ORIENTED_EDGE('',*,*,#1587,.T.);
#1589=EDGE_LOOP('',(#1572,#1573,#1582,#1588));
#1590=FACE_BOUND('',#1589,.T.);
#1591=ADVANCED_FACE('F1007',(#1590),#1571,.F.);
#1592=CARTESIAN_POINT('',(-3.175,100.6602,-0.9652));
#1593=DIRECTION('',(0.,0.,-1.));
#1594=DIRECTION('',(-1.,0.,0.));
#1595=AXIS2_PLACEMENT_3D('',#1592,#1593,#1594);
#1596=PLANE('',#1595);
#1597=ORIENTED_EDGE('',*,*,#1415,.T.);
#1598=ORIENTED_EDGE('',*,*,#1587,.F.);
#1599=DIRECTION('',(-1.,0.,0.));
#1600=VECTOR('',#1599,1.);
#1601=CARTESIAN_POINT('',(-3.175,100.6602,-0.9652));
#1602=LINE('',#1601,#1600);
#1603=EDGE_CURVE('E794',#1522,#1580,#1602,.T.);
#1604=ORIENTED_EDGE('',*,*,#1603,.F.);
#1605=ORIENTED_EDGE('',*,*,#1523,.T.);
#1606=EDGE_LOOP('',(#1597,#1598,#1604,#1605));
#1607=FACE_BOUND('',#1606,.T.);
#1608=ADVANCED_FACE('F1002',(#1607),#1596,.F.);
#1609=CARTESIAN_POINT('',(3.175,100.6602,0.));
#1610=DIRECTION('',(0.,1.,0.));
#1611=DIRECTION('',(0.,0.,1.));
#1612=AXIS2_PLACEMENT_3D('',#1609,#1610,#1611);
#1613=PLANE('',#1612);
#1614=ORIENTED_EDGE('',*,*,#1532,.T.);
#1615=ORIENTED_EDGE('',*,*,#1603,.T.);
#1616=ORIENTED_EDGE('',*,*,#1581,.T.);
#1617=ORIENTED_EDGE('',*,*,#1556,.T.);
#1618=EDGE_LOOP('',(#1614,#1615,#1616,#1617));
#1619=FACE_BOUND('',#1618,.T.);
#1620=ADVANCED_FACE('F997',(#1619),#1613,.T.);
#1621=CARTESIAN_POINT('',(16.8379802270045,89.5858,-16.8379802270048));
#1622=DIRECTION('',(0.,-1.,0.));
#1623=DIRECTION('',(0.,0.,-1.));
#1624=AXIS2_PLACEMENT_3D('',#1621,#1622,#1623);
#1625=CYLINDRICAL_SURFACE('',#1624,6.1722);
#1626=CARTESIAN_POINT('',(16.8379802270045,68.58,-16.8379802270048));
#1627=DIRECTION('',(0.,1.,0.));
#1628=DIRECTION('',(0.,0.,1.));
#1629=AXIS2_PLACEMENT_3D('',#1626,#1627,#1628);
#1630=CIRCLE('',#1629,6.1722);
#1631=EDGE_CURVE('E787',#498,#387,#1630,.T.);
#1632=ORIENTED_EDGE('',*,*,#1631,.F.);
#1633=ORIENTED_EDGE('',*,*,#499,.F.);
#1634=EDGE_LOOP('',(#1632,#1633));
#1635=FACE_BOUND('',#1634,.T.);
#1636=ADVANCED_FACE('F991',(#1635),#1625,.F.);
#1637=CARTESIAN_POINT('',(16.8379802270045,68.58,-16.8379802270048));
#1638=DIRECTION('',(0.,1.,0.));
#1639=DIRECTION('',(0.,0.,1.));
#1640=AXIS2_PLACEMENT_3D('',#1637,#1638,#1639);
#1641=PLANE('',#1640);
#1642=DIRECTION('',(-0.967859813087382,0.,0.251490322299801));
#1643=VECTOR('',#1642,1.);
#1644=CARTESIAN_POINT('',(15.6741520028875,68.58,-21.3169699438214));
#1645=LINE('',#1644,#1643);
#1646=CARTESIAN_POINT('',(13.0427408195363,68.58,-20.6332196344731));
#1647=VERTEX_POINT('',#1646);
#1648=EDGE_CURVE('E1399',#502,#1647,#1645,.T.);
#1649=ORIENTED_EDGE('',*,*,#1648,.F.);
#1650=ORIENTED_EDGE('',*,*,#503,.F.);
#1651=ORIENTED_EDGE('',*,*,#1631,.T.);
#1652=ORIENTED_EDGE('',*,*,#388,.F.);
#1653=DIRECTION('',(0.251490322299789,0.,-0.967859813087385));
#1654=VECTOR('',#1653,1.);
#1655=CARTESIAN_POINT('',(20.6332196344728,68.58,-13.0427408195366));
#1656=LINE('',#1655,#1654);
#1657=CARTESIAN_POINT('',(20.6332196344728,68.58,-13.0427408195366));
#1658=VERTEX_POINT('',#1657);
#1659=EDGE_CURVE('E1369',#1658,#378,#1656,.T.);
#1660=ORIENTED_EDGE('',*,*,#1659,.F.);
#1661=DIRECTION('',(0.965925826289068,0.,-0.258819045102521));
#1662=VECTOR('',#1661,1.);
#1663=CARTESIAN_POINT('',(15.4488261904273,68.58,-11.6535867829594));
#1664=LINE('',#1663,#1662);
#1665=CARTESIAN_POINT('',(15.4488261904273,68.58,-11.6535867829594));
#1666=VERTEX_POINT('',#1665);
#1667=EDGE_CURVE('E1368',#1666,#1658,#1664,.T.);
#1668=ORIENTED_EDGE('',*,*,#1667,.F.);
#1669=DIRECTION('',(0.707106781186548,0.,0.707106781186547));
#1670=VECTOR('',#1669,1.);
#1671=CARTESIAN_POINT('',(11.6535867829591,68.58,-15.4488261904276));
#1672=LINE('',#1671,#1670);
#1673=CARTESIAN_POINT('',(11.6535867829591,68.58,-15.4488261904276));
#1674=VERTEX_POINT('',#1673);
#1675=EDGE_CURVE('E1382',#1674,#1666,#1672,.T.);
#1676=ORIENTED_EDGE('',*,*,#1675,.F.);
#1677=DIRECTION('',(-0.258819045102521,0.,0.965925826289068));
#1678=VECTOR('',#1677,1.);
#1679=CARTESIAN_POINT('',(13.0427408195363,68.58,-20.6332196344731));
#1680=LINE('',#1679,#1678);
#1681=EDGE_CURVE('E1374',#1647,#1674,#1680,.T.);
#1682=ORIENTED_EDGE('',*,*,#1681,.F.);
#1683=EDGE_LOOP('',(#1649,#1650,#1651,#1652,#1660,#1668,#1676,#1682));
#1684=FACE_BOUND('',#1683,.T.);
#1685=ADVANCED_FACE('F996',(#1684),#1641,.T.);
#1686=CARTESIAN_POINT('',(16.8379802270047,89.5858,16.8379802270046));
#1687=DIRECTION('',(0.,-1.,0.));
#1688=DIRECTION('',(0.,0.,-1.));
#1689=AXIS2_PLACEMENT_3D('',#1686,#1687,#1688);
#1690=CYLINDRICAL_SURFACE('',#1689,6.1722);
#1691=CARTESIAN_POINT('',(16.8379802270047,68.58,16.8379802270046));
#1692=DIRECTION('',(0.,1.,0.));
#1693=DIRECTION('',(-1.,0.,0.));
#1694=AXIS2_PLACEMENT_3D('',#1691,#1692,#1693);
#1695=CIRCLE('',#1694,6.1722);
#1696=EDGE_CURVE('E784',#340,#229,#1695,.T.);
#1697=ORIENTED_EDGE('',*,*,#1696,.F.);
#1698=ORIENTED_EDGE('',*,*,#341,.F.);
#1699=EDGE_LOOP('',(#1697,#1698));
#1700=FACE_BOUND('',#1699,.T.);
#1701=ADVANCED_FACE('F1436',(#1700),#1690,.F.);
#1702=CARTESIAN_POINT('',(16.8379802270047,68.58,16.8379802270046));
#1703=DIRECTION('',(0.,1.,0.));
#1704=DIRECTION('',(-1.,0.,0.));
#1705=AXIS2_PLACEMENT_3D('',#1702,#1703,#1704);
#1706=PLANE('',#1705);
#1707=DIRECTION('',(-0.251490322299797,0.,-0.967859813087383));
#1708=VECTOR('',#1707,1.);
#1709=CARTESIAN_POINT('',(21.3169699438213,68.58,15.6741520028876));
#1710=LINE('',#1709,#1708);
#1711=CARTESIAN_POINT('',(20.633219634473,68.58,13.0427408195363));
#1712=VERTEX_POINT('',#1711);
#1713=EDGE_CURVE('E1282',#344,#1712,#1710,.T.);
#1714=ORIENTED_EDGE('',*,*,#1713,.F.);
#1715=ORIENTED_EDGE('',*,*,#345,.F.);
#1716=ORIENTED_EDGE('',*,*,#1696,.T.);
#1717=ORIENTED_EDGE('',*,*,#230,.F.);
#1718=DIRECTION('',(0.967859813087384,0.,0.251490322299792));
#1719=VECTOR('',#1718,1.);
#1720=CARTESIAN_POINT('',(13.0427408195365,68.58,20.6332196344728));
#1721=LINE('',#1720,#1719);
#1722=CARTESIAN_POINT('',(13.0427408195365,68.58,20.6332196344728));
#1723=VERTEX_POINT('',#1722);
#1724=EDGE_CURVE('E703',#1723,#220,#1721,.T.);
#1725=ORIENTED_EDGE('',*,*,#1724,.F.);
#1726=DIRECTION('',(0.258819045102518,0.,0.965925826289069));
#1727=VECTOR('',#1726,1.);
#1728=CARTESIAN_POINT('',(11.6535867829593,68.58,15.4488261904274));
#1729=LINE('',#1728,#1727);
#1730=CARTESIAN_POINT('',(11.6535867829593,68.58,15.4488261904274));
#1731=VERTEX_POINT('',#1730);
#1732=EDGE_CURVE('E680',#1731,#1723,#1729,.T.);
#1733=ORIENTED_EDGE('',*,*,#1732,.F.);
#1734=DIRECTION('',(-0.70710678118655,0.,0.707106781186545));
#1735=VECTOR('',#1734,1.);
#1736=CARTESIAN_POINT('',(15.4488261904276,68.58,11.6535867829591));
#1737=LINE('',#1736,#1735);
#1738=CARTESIAN_POINT('',(15.4488261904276,68.58,11.6535867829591));
#1739=VERTEX_POINT('',#1738);
#1740=EDGE_CURVE('E690',#1739,#1731,#1737,.T.);
#1741=ORIENTED_EDGE('',*,*,#1740,.F.);
#1742=DIRECTION('',(-0.965925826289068,0.,-0.258819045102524));
#1743=VECTOR('',#1742,1.);
#1744=CARTESIAN_POINT('',(20.633219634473,68.58,13.0427408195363));
#1745=LINE('',#1744,#1743);
#1746=EDGE_CURVE('E705',#1712,#1739,#1745,.T.);
#1747=ORIENTED_EDGE('',*,*,#1746,.F.);
#1748=EDGE_LOOP('',(#1714,#1715,#1716,#1717,#1725,#1733,#1741,#1747));
#1749=FACE_BOUND('',#1748,.T.);
#1750=ADVANCED_FACE('F1423',(#1749),#1706,.T.);
#1751=CARTESIAN_POINT('',(-16.8379802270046,89.5858,16.8379802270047));
#1752=DIRECTION('',(0.,-1.,0.));
#1753=DIRECTION('',(0.,0.,-1.));
#1754=AXIS2_PLACEMENT_3D('',#1751,#1752,#1753);
#1755=CYLINDRICAL_SURFACE('',#1754,6.1722);
#1756=CARTESIAN_POINT('',(-16.8379802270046,68.58,16.8379802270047));
#1757=DIRECTION('',(0.,1.,0.));
#1758=DIRECTION('',(0.,0.,-1.));
#1759=AXIS2_PLACEMENT_3D('',#1756,#1757,#1758);
#1760=CIRCLE('',#1759,6.1722);
#1761=EDGE_CURVE('E781',#182,#71,#1760,.T.);
#1762=ORIENTED_EDGE('',*,*,#1761,.F.);
#1763=ORIENTED_EDGE('',*,*,#183,.F.);
#1764=EDGE_LOOP('',(#1762,#1763));
#1765=FACE_BOUND('',#1764,.T.);
#1766=ADVANCED_FACE('F1418',(#1765),#1755,.F.);
#1767=CARTESIAN_POINT('',(-16.8379802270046,68.58,16.8379802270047));
#1768=DIRECTION('',(0.,1.,0.));
#1769=DIRECTION('',(0.,0.,-1.));
#1770=AXIS2_PLACEMENT_3D('',#1767,#1768,#1769);
#1771=PLANE('',#1770);
#1772=DIRECTION('',(0.967859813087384,0.,-0.251490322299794));
#1773=VECTOR('',#1772,1.);
#1774=CARTESIAN_POINT('',(-15.6741520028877,68.58,21.3169699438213));
#1775=LINE('',#1774,#1773);
#1776=CARTESIAN_POINT('',(-13.0427408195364,68.58,20.633219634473));
#1777=VERTEX_POINT('',#1776);
#1778=EDGE_CURVE('E1277',#186,#1777,#1775,.T.);
#1779=ORIENTED_EDGE('',*,*,#1778,.F.);
#1780=ORIENTED_EDGE('',*,*,#187,.F.);
#1781=ORIENTED_EDGE('',*,*,#1761,.T.);
#1782=ORIENTED_EDGE('',*,*,#72,.F.);
#1783=DIRECTION('',(-0.251490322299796,0.,0.967859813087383));
#1784=VECTOR('',#1783,1.);
#1785=CARTESIAN_POINT('',(-20.6332196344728,68.58,13.0427408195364));
#1786=LINE('',#1785,#1784);
#1787=CARTESIAN_POINT('',(-20.6332196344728,68.58,13.0427408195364));
#1788=VERTEX_POINT('',#1787);
#1789=EDGE_CURVE('E2098',#1788,#62,#1786,.T.);
#1790=ORIENTED_EDGE('',*,*,#1789,.F.);
#1791=DIRECTION('',(-0.96592582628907,0.,0.258819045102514));
#1792=VECTOR('',#1791,1.);
#1793=CARTESIAN_POINT('',(-15.4488261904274,68.58,11.6535867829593));
#1794=LINE('',#1793,#1792);
#1795=CARTESIAN_POINT('',(-15.4488261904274,68.58,11.6535867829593));
#1796=VERTEX_POINT('',#1795);
#1797=EDGE_CURVE('E942',#1796,#1788,#1794,.T.);
#1798=ORIENTED_EDGE('',*,*,#1797,.F.);
#1799=DIRECTION('',(-0.707106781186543,0.,-0.707106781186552));
#1800=VECTOR('',#1799,1.);
#1801=CARTESIAN_POINT('',(-11.6535867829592,68.58,15.4488261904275));
#1802=LINE('',#1801,#1800);
#1803=CARTESIAN_POINT('',(-11.6535867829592,68.58,15.4488261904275));
#1804=VERTEX_POINT('',#1803);
#1805=EDGE_CURVE('E2107',#1804,#1796,#1802,.T.);
#1806=ORIENTED_EDGE('',*,*,#1805,.F.);
#1807=DIRECTION('',(0.258819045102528,0.,-0.965925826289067));
#1808=VECTOR('',#1807,1.);
#1809=CARTESIAN_POINT('',(-13.0427408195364,68.58,20.633219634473));
#1810=LINE('',#1809,#1808);
#1811=EDGE_CURVE('E2118',#1777,#1804,#1810,.T.);
#1812=ORIENTED_EDGE('',*,*,#1811,.F.);
#1813=EDGE_LOOP('',(#1779,#1780,#1781,#1782,#1790,#1798,#1806,#1812));
#1814=FACE_BOUND('',#1813,.T.);
#1815=ADVANCED_FACE('F1414',(#1814),#1771,.T.);
#1816=CARTESIAN_POINT('',(-16.8379802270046,89.5858,-16.8379802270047));
#1817=DIRECTION('',(0.,-1.,0.));
#1818=DIRECTION('',(0.,0.,-1.));
#1819=AXIS2_PLACEMENT_3D('',#1816,#1817,#1818);
#1820=CYLINDRICAL_SURFACE('',#1819,6.1722);
#1821=CARTESIAN_POINT('',(-16.8379802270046,68.58,-16.8379802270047));
#1822=DIRECTION('',(0.,1.,0.));
#1823=DIRECTION('',(1.,0.,0.));
#1824=AXIS2_PLACEMENT_3D('',#1821,#1822,#1823);
#1825=CIRCLE('',#1824,6.1722);
#1826=EDGE_CURVE('E773',#656,#545,#1825,.T.);
#1827=ORIENTED_EDGE('',*,*,#1826,.F.);
#1828=ORIENTED_EDGE('',*,*,#657,.F.);
#1829=EDGE_LOOP('',(#1827,#1828));
#1830=FACE_BOUND('',#1829,.T.);
#1831=ADVANCED_FACE('F1409',(#1830),#1820,.F.);
#1832=CARTESIAN_POINT('',(-16.8379802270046,68.58,-16.8379802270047));
#1833=DIRECTION('',(0.,1.,0.));
#1834=DIRECTION('',(1.,0.,0.));
#1835=AXIS2_PLACEMENT_3D('',#1832,#1833,#1834);
#1836=PLANE('',#1835);
#1837=DIRECTION('',(0.25149032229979,0.,0.967859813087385));
#1838=VECTOR('',#1837,1.);
#1839=CARTESIAN_POINT('',(-21.3169699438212,68.58,-15.6741520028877));
#1840=LINE('',#1839,#1838);
#1841=CARTESIAN_POINT('',(-20.6332196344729,68.58,-13.0427408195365));
#1842=VERTEX_POINT('',#1841);
#1843=EDGE_CURVE('E1275',#38,#1842,#1840,.T.);
#1844=ORIENTED_EDGE('',*,*,#1843,.F.);
#1845=ORIENTED_EDGE('',*,*,#659,.F.);
#1846=ORIENTED_EDGE('',*,*,#1826,.T.);
#1847=ORIENTED_EDGE('',*,*,#546,.F.);
#1848=DIRECTION('',(-0.967859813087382,0.,-0.251490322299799));
#1849=VECTOR('',#1848,1.);
#1850=CARTESIAN_POINT('',(-13.0427408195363,68.58,-20.6332196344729));
#1851=LINE('',#1850,#1849);
#1852=CARTESIAN_POINT('',(-13.0427408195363,68.58,-20.6332196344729));
#1853=VERTEX_POINT('',#1852);
#1854=EDGE_CURVE('E604',#1853,#536,#1851,.T.);
#1855=ORIENTED_EDGE('',*,*,#1854,.F.);
#1856=DIRECTION('',(-0.258819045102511,0.,-0.965925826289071));
#1857=VECTOR('',#1856,1.);
#1858=CARTESIAN_POINT('',(-11.6535867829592,68.58,-15.4488261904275));
#1859=LINE('',#1858,#1857);
#1860=CARTESIAN_POINT('',(-11.6535867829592,68.58,-15.4488261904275));
#1861=VERTEX_POINT('',#1860);
#1862=EDGE_CURVE('E576',#1861,#1853,#1859,.T.);
#1863=ORIENTED_EDGE('',*,*,#1862,.F.);
#1864=DIRECTION('',(0.707106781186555,0.,-0.70710678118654));
#1865=VECTOR('',#1864,1.);
#1866=CARTESIAN_POINT('',(-15.4488261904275,68.58,-11.6535867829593));
#1867=LINE('',#1866,#1865);
#1868=CARTESIAN_POINT('',(-15.4488261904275,68.58,-11.6535867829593));
#1869=VERTEX_POINT('',#1868);
#1870=EDGE_CURVE('E591',#1869,#1861,#1867,.T.);
#1871=ORIENTED_EDGE('',*,*,#1870,.F.);
#1872=DIRECTION('',(0.965925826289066,0.,0.258819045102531));
#1873=VECTOR('',#1872,1.);
#1874=CARTESIAN_POINT('',(-20.6332196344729,68.58,-13.0427408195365));
#1875=LINE('',#1874,#1873);
#1876=EDGE_CURVE('E606',#1842,#1869,#1875,.T.);
#1877=ORIENTED_EDGE('',*,*,#1876,.F.);
#1878=EDGE_LOOP('',(#1844,#1845,#1846,#1847,#1855,#1863,#1871,#1877));
#1879=FACE_BOUND('',#1878,.T.);
#1880=ADVANCED_FACE('F748',(#1879),#1836,.T.);
#1881=CARTESIAN_POINT('',(20.6332196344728,62.23,-13.0427408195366));
#1882=DIRECTION('',(0.,1.,0.));
#1883=DIRECTION('',(0.,0.,1.));
#1884=AXIS2_PLACEMENT_3D('',#1881,#1882,#1883);
#1885=PLANE('',#1884);
#1886=CARTESIAN_POINT('',(16.8379802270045,62.23,-16.8379802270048));
#1887=DIRECTION('',(0.,1.,0.));
#1888=DIRECTION('',(0.,0.,1.));
#1889=AXIS2_PLACEMENT_3D('',#1886,#1887,#1888);
#1890=CIRCLE('',#1889,3.9624);
#1891=CARTESIAN_POINT('',(16.8379802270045,62.23,-12.8755802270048));
#1892=VERTEX_POINT('',#1891);
#1893=EDGE_CURVE('E1276',#1892,#1892,#1890,.T.);
#1894=ORIENTED_EDGE('',*,*,#1893,.F.);
#1895=EDGE_LOOP('',(#1894));
#1896=FACE_BOUND('',#1895,.T.);
#1897=ORIENTED_EDGE('',*,*,#1102,.F.);
#1898=DIRECTION('',(-0.967859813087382,0.,0.251490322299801));
#1899=VECTOR('',#1898,1.);
#1900=CARTESIAN_POINT('',(23.2979505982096,62.23,-23.29795059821));
#1901=LINE('',#1900,#1899);
#1902=CARTESIAN_POINT('',(13.0427408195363,62.23,-20.6332196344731));
#1903=VERTEX_POINT('',#1902);
#1904=EDGE_CURVE('E958',#517,#1903,#1901,.T.);
#1905=ORIENTED_EDGE('',*,*,#1904,.T.);
#1906=DIRECTION('',(-0.258819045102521,0.,0.965925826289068));
#1907=VECTOR('',#1906,1.);
#1908=CARTESIAN_POINT('',(13.0427408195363,62.23,-20.6332196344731));
#1909=LINE('',#1908,#1907);
#1910=CARTESIAN_POINT('',(11.6535867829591,62.23,-15.4488261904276));
#1911=VERTEX_POINT('',#1910);
#1912=EDGE_CURVE('E968',#1903,#1911,#1909,.T.);
#1913=ORIENTED_EDGE('',*,*,#1912,.T.);
#1914=DIRECTION('',(0.707106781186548,0.,0.707106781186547));
#1915=VECTOR('',#1914,1.);
#1916=CARTESIAN_POINT('',(11.6535867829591,62.23,-15.4488261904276));
#1917=LINE('',#1916,#1915);
#1918=CARTESIAN_POINT('',(15.4488261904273,62.23,-11.6535867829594));
#1919=VERTEX_POINT('',#1918);
#1920=EDGE_CURVE('E1377',#1911,#1919,#1917,.T.);
#1921=ORIENTED_EDGE('',*,*,#1920,.T.);
#1922=DIRECTION('',(0.965925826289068,0.,-0.258819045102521));
#1923=VECTOR('',#1922,1.);
#1924=CARTESIAN_POINT('',(15.4488261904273,62.23,-11.6535867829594));
#1925=LINE('',#1924,#1923);
#1926=CARTESIAN_POINT('',(20.6332196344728,62.23,-13.0427408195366));
#1927=VERTEX_POINT('',#1926);
#1928=EDGE_CURVE('E1385',#1919,#1927,#1925,.T.);
#1929=ORIENTED_EDGE('',*,*,#1928,.T.);
#1930=DIRECTION('',(0.251490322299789,0.,-0.967859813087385));
#1931=VECTOR('',#1930,1.);
#1932=CARTESIAN_POINT('',(20.6332196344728,62.23,-13.0427408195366));
#1933=LINE('',#1932,#1931);
#1934=EDGE_CURVE('E962',#1927,#363,#1933,.T.);
#1935=ORIENTED_EDGE('',*,*,#1934,.T.);
#1936=EDGE_LOOP('',(#1897,#1905,#1913,#1921,#1929,#1935));
#1937=FACE_BOUND('',#1936,.T.);
#1938=ADVANCED_FACE('F744',(#1896,#1937),#1885,.T.);
#1939=CARTESIAN_POINT('',(15.4488261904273,62.23,-11.6535867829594));
#1940=DIRECTION('',(0.258819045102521,0.,0.965925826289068));
#1941=DIRECTION('',(0.965925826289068,0.,-0.258819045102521));
#1942=AXIS2_PLACEMENT_3D('',#1939,#1940,#1941);
#1943=PLANE('',#1942);
#1944=ORIENTED_EDGE('',*,*,#1667,.T.);
#1945=DIRECTION('',(0.,1.,0.));
#1946=VECTOR('',#1945,1.);
#1947=CARTESIAN_POINT('',(20.6332196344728,62.23,-13.0427408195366));
#1948=LINE('',#1947,#1946);
#1949=EDGE_CURVE('E1390',#1927,#1658,#1948,.T.);
#1950=ORIENTED_EDGE('',*,*,#1949,.F.);
#1951=ORIENTED_EDGE('',*,*,#1928,.F.);
#1952=DIRECTION('',(0.,1.,0.));
#1953=VECTOR('',#1952,1.);
#1954=CARTESIAN_POINT('',(15.4488261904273,62.23,-11.6535867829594));
#1955=LINE('',#1954,#1953);
#1956=EDGE_CURVE('E1386',#1919,#1666,#1955,.T.);
#1957=ORIENTED_EDGE('',*,*,#1956,.T.);
#1958=EDGE_LOOP('',(#1944,#1950,#1951,#1957));
#1959=FACE_BOUND('',#1958,.T.);
#1960=ADVANCED_FACE('F747',(#1959),#1943,.F.);
#1961=CARTESIAN_POINT('',(11.6535867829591,62.23,-15.4488261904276));
#1962=DIRECTION('',(-0.707106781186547,0.,0.707106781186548));
#1963=DIRECTION('',(0.707106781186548,0.,0.707106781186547));
#1964=AXIS2_PLACEMENT_3D('',#1961,#1962,#1963);
#1965=PLANE('',#1964);
#1966=ORIENTED_EDGE('',*,*,#1675,.T.);
#1967=ORIENTED_EDGE('',*,*,#1956,.F.);
#1968=ORIENTED_EDGE('',*,*,#1920,.F.);
#1969=DIRECTION('',(0.,1.,0.));
#1970=VECTOR('',#1969,1.);
#1971=CARTESIAN_POINT('',(11.6535867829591,62.23,-15.4488261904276));
#1972=LINE('',#1971,#1970);
#1973=EDGE_CURVE('E1388',#1911,#1674,#1972,.T.);
#1974=ORIENTED_EDGE('',*,*,#1973,.T.);
#1975=EDGE_LOOP('',(#1966,#1967,#1968,#1974));
#1976=FACE_BOUND('',#1975,.T.);
#1977=ADVANCED_FACE('F750',(#1976),#1965,.F.);
#1978=CARTESIAN_POINT('',(13.0427408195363,62.23,-20.6332196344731));
#1979=DIRECTION('',(-0.965925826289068,0.,-0.258819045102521));
#1980=DIRECTION('',(-0.258819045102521,0.,0.965925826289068));
#1981=AXIS2_PLACEMENT_3D('',#1978,#1979,#1980);
#1982=PLANE('',#1981);
#1983=ORIENTED_EDGE('',*,*,#1681,.T.);
#1984=ORIENTED_EDGE('',*,*,#1973,.F.);
#1985=ORIENTED_EDGE('',*,*,#1912,.F.);
#1986=DIRECTION('',(0.,1.,0.));
#1987=VECTOR('',#1986,1.);
#1988=CARTESIAN_POINT('',(13.0427408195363,62.23,-20.6332196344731));
#1989=LINE('',#1988,#1987);
#1990=EDGE_CURVE('E966',#1903,#1647,#1989,.T.);
#1991=ORIENTED_EDGE('',*,*,#1990,.T.);
#1992=EDGE_LOOP('',(#1983,#1984,#1985,#1991));
#1993=FACE_BOUND('',#1992,.T.);
#1994=ADVANCED_FACE('F753',(#1993),#1982,.F.);
#1995=CARTESIAN_POINT('',(23.2979505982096,62.23,-23.29795059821));
#1996=DIRECTION('',(-0.251490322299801,0.,-0.967859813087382));
#1997=DIRECTION('',(-0.967859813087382,0.,0.251490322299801));
#1998=AXIS2_PLACEMENT_3D('',#1995,#1996,#1997);
#1999=PLANE('',#1998);
#2000=ORIENTED_EDGE('',*,*,#518,.T.);
#2001=ORIENTED_EDGE('',*,*,#1648,.T.);
#2002=ORIENTED_EDGE('',*,*,#1990,.F.);
#2003=ORIENTED_EDGE('',*,*,#1904,.F.);
#2004=EDGE_LOOP('',(#2000,#2001,#2002,#2003));
#2005=FACE_BOUND('',#2004,.T.);
#2006=ADVANCED_FACE('F757',(#2005),#1999,.F.);
#2007=CARTESIAN_POINT('',(20.6332196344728,62.23,-13.0427408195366));
#2008=DIRECTION('',(0.967859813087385,0.,0.251490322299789));
#2009=DIRECTION('',(0.251490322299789,0.,-0.967859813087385));
#2010=AXIS2_PLACEMENT_3D('',#2007,#2008,#2009);
#2011=PLANE('',#2010);
#2012=ORIENTED_EDGE('',*,*,#379,.T.);
#2013=ORIENTED_EDGE('',*,*,#1934,.F.);
#2014=ORIENTED_EDGE('',*,*,#1949,.T.);
#2015=ORIENTED_EDGE('',*,*,#1659,.T.);
#2016=EDGE_LOOP('',(#2012,#2013,#2014,#2015));
#2017=FACE_BOUND('',#2016,.T.);
#2018=ADVANCED_FACE('F762',(#2017),#2011,.F.);
#2019=CARTESIAN_POINT('',(13.0427408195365,62.23,20.6332196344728));
#2020=DIRECTION('',(0.,1.,0.));
#2021=DIRECTION('',(-1.,0.,0.));
#2022=AXIS2_PLACEMENT_3D('',#2019,#2020,#2021);
#2023=PLANE('',#2022);
#2024=CARTESIAN_POINT('',(16.8379802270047,62.23,16.8379802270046));
#2025=DIRECTION('',(0.,1.,0.));
#2026=DIRECTION('',(0.,0.,1.));
#2027=AXIS2_PLACEMENT_3D('',#2024,#2025,#2026);
#2028=CIRCLE('',#2027,3.9624);
#2029=CARTESIAN_POINT('',(16.8379802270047,62.23,20.8003802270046));
#2030=VERTEX_POINT('',#2029);
#2031=EDGE_CURVE('E1280',#2030,#2030,#2028,.T.);
#2032=ORIENTED_EDGE('',*,*,#2031,.F.);
#2033=EDGE_LOOP('',(#2032));
#2034=FACE_BOUND('',#2033,.T.);
#2035=ORIENTED_EDGE('',*,*,#1105,.F.);
#2036=DIRECTION('',(-0.251490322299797,0.,-0.967859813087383));
#2037=VECTOR('',#2036,1.);
#2038=CARTESIAN_POINT('',(23.2979505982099,62.23,23.2979505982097));
#2039=LINE('',#2038,#2037);
#2040=CARTESIAN_POINT('',(20.633219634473,62.23,13.0427408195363));
#2041=VERTEX_POINT('',#2040);
#2042=EDGE_CURVE('E693',#359,#2041,#2039,.T.);
#2043=ORIENTED_EDGE('',*,*,#2042,.T.);
#2044=DIRECTION('',(-0.965925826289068,0.,-0.258819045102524));
#2045=VECTOR('',#2044,1.);
#2046=CARTESIAN_POINT('',(20.633219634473,62.23,13.0427408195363));
#2047=LINE('',#2046,#2045);
#2048=CARTESIAN_POINT('',(15.4488261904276,62.23,11.6535867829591));
#2049=VERTEX_POINT('',#2048);
#2050=EDGE_CURVE('E695',#2041,#2049,#2047,.T.);
#2051=ORIENTED_EDGE('',*,*,#2050,.T.);
#2052=DIRECTION('',(-0.70710678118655,0.,0.707106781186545));
#2053=VECTOR('',#2052,1.);
#2054=CARTESIAN_POINT('',(15.4488261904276,62.23,11.6535867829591));
#2055=LINE('',#2054,#2053);
#2056=CARTESIAN_POINT('',(11.6535867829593,62.23,15.4488261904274));
#2057=VERTEX_POINT('',#2056);
#2058=EDGE_CURVE('E698',#2049,#2057,#2055,.T.);
#2059=ORIENTED_EDGE('',*,*,#2058,.T.);
#2060=DIRECTION('',(0.258819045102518,0.,0.965925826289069));
#2061=VECTOR('',#2060,1.);
#2062=CARTESIAN_POINT('',(11.6535867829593,62.23,15.4488261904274));
#2063=LINE('',#2062,#2061);
#2064=CARTESIAN_POINT('',(13.0427408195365,62.23,20.6332196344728));
#2065=VERTEX_POINT('',#2064);
#2066=EDGE_CURVE('E686',#2057,#2065,#2063,.T.);
#2067=ORIENTED_EDGE('',*,*,#2066,.T.);
#2068=DIRECTION('',(0.967859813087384,0.,0.251490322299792));
#2069=VECTOR('',#2068,1.);
#2070=CARTESIAN_POINT('',(13.0427408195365,62.23,20.6332196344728));
#2071=LINE('',#2070,#2069);
#2072=EDGE_CURVE('E689',#2065,#205,#2071,.T.);
#2073=ORIENTED_EDGE('',*,*,#2072,.T.);
#2074=EDGE_LOOP('',(#2035,#2043,#2051,#2059,#2067,#2073));
#2075=FACE_BOUND('',#2074,.T.);
#2076=ADVANCED_FACE('F742',(#2034,#2075),#2023,.T.);
#2077=CARTESIAN_POINT('',(11.6535867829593,62.23,15.4488261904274));
#2078=DIRECTION('',(-0.965925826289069,0.,0.258819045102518));
#2079=DIRECTION('',(0.258819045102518,0.,0.965925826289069));
#2080=AXIS2_PLACEMENT_3D('',#2077,#2078,#2079);
#2081=PLANE('',#2080);
#2082=ORIENTED_EDGE('',*,*,#1732,.T.);
#2083=DIRECTION('',(0.,1.,0.));
#2084=VECTOR('',#2083,1.);
#2085=CARTESIAN_POINT('',(13.0427408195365,62.23,20.6332196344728));
#2086=LINE('',#2085,#2084);
#2087=EDGE_CURVE('E701',#2065,#1723,#2086,.T.);
#2088=ORIENTED_EDGE('',*,*,#2087,.F.);
#2089=ORIENTED_EDGE('',*,*,#2066,.F.);
#2090=DIRECTION('',(0.,1.,0.));
#2091=VECTOR('',#2090,1.);
#2092=CARTESIAN_POINT('',(11.6535867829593,62.23,15.4488261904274));
#2093=LINE('',#2092,#2091);
#2094=EDGE_CURVE('E710',#2057,#1731,#2093,.T.);
#2095=ORIENTED_EDGE('',*,*,#2094,.T.);
#2096=EDGE_LOOP('',(#2082,#2088,#2089,#2095));
#2097=FACE_BOUND('',#2096,.T.);
#2098=ADVANCED_FACE('F738',(#2097),#2081,.F.);
#2099=CARTESIAN_POINT('',(15.4488261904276,62.23,11.6535867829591));
#2100=DIRECTION('',(-0.707106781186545,0.,-0.70710678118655));
#2101=DIRECTION('',(-0.70710678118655,0.,0.707106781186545));
#2102=AXIS2_PLACEMENT_3D('',#2099,#2100,#2101);
#2103=PLANE('',#2102);
#2104=ORIENTED_EDGE('',*,*,#1740,.T.);
#2105=ORIENTED_EDGE('',*,*,#2094,.F.);
#2106=ORIENTED_EDGE('',*,*,#2058,.F.);
#2107=DIRECTION('',(0.,1.,0.));
#2108=VECTOR('',#2107,1.);
#2109=CARTESIAN_POINT('',(15.4488261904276,62.23,11.6535867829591));
#2110=LINE('',#2109,#2108);
#2111=EDGE_CURVE('E713',#2049,#1739,#2110,.T.);
#2112=ORIENTED_EDGE('',*,*,#2111,.T.);
#2113=EDGE_LOOP('',(#2104,#2105,#2106,#2112));
#2114=FACE_BOUND('',#2113,.T.);
#2115=ADVANCED_FACE('F741',(#2114),#2103,.F.);
#2116=CARTESIAN_POINT('',(20.633219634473,62.23,13.0427408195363));
#2117=DIRECTION('',(0.258819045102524,0.,-0.965925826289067));
#2118=DIRECTION('',(-0.965925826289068,0.,-0.258819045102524));
#2119=AXIS2_PLACEMENT_3D('',#2116,#2117,#2118);
#2120=PLANE('',#2119);
#2121=ORIENTED_EDGE('',*,*,#1746,.T.);
#2122=ORIENTED_EDGE('',*,*,#2111,.F.);
#2123=ORIENTED_EDGE('',*,*,#2050,.F.);
#2124=DIRECTION('',(0.,1.,0.));
#2125=VECTOR('',#2124,1.);
#2126=CARTESIAN_POINT('',(20.633219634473,62.23,13.0427408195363));
#2127=LINE('',#2126,#2125);
#2128=EDGE_CURVE('E715',#2041,#1712,#2127,.T.);
#2129=ORIENTED_EDGE('',*,*,#2128,.T.);
#2130=EDGE_LOOP('',(#2121,#2122,#2123,#2129));
#2131=FACE_BOUND('',#2130,.T.);
#2132=ADVANCED_FACE('F1457',(#2131),#2120,.F.);
#2133=CARTESIAN_POINT('',(23.2979505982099,62.23,23.2979505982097));
#2134=DIRECTION('',(0.967859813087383,0.,-0.251490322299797));
#2135=DIRECTION('',(-0.251490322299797,0.,-0.967859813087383));
#2136=AXIS2_PLACEMENT_3D('',#2133,#2134,#2135);
#2137=PLANE('',#2136);
#2138=ORIENTED_EDGE('',*,*,#360,.T.);
#2139=ORIENTED_EDGE('',*,*,#1713,.T.);
#2140=ORIENTED_EDGE('',*,*,#2128,.F.);
#2141=ORIENTED_EDGE('',*,*,#2042,.F.);
#2142=EDGE_LOOP('',(#2138,#2139,#2140,#2141));
#2143=FACE_BOUND('',#2142,.T.);
#2144=ADVANCED_FACE('F734',(#2143),#2137,.F.);
#2145=CARTESIAN_POINT('',(13.0427408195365,62.23,20.6332196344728));
#2146=DIRECTION('',(-0.251490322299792,0.,0.967859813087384));
#2147=DIRECTION('',(0.967859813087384,0.,0.251490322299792));
#2148=AXIS2_PLACEMENT_3D('',#2145,#2146,#2147);
#2149=PLANE('',#2148);
#2150=ORIENTED_EDGE('',*,*,#221,.T.);
#2151=ORIENTED_EDGE('',*,*,#2072,.F.);
#2152=ORIENTED_EDGE('',*,*,#2087,.T.);
#2153=ORIENTED_EDGE('',*,*,#1724,.T.);
#2154=EDGE_LOOP('',(#2150,#2151,#2152,#2153));
#2155=FACE_BOUND('',#2154,.T.);
#2156=ADVANCED_FACE('F655',(#2155),#2149,.F.);
#2157=CARTESIAN_POINT('',(-20.6332196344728,62.23,13.0427408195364));
#2158=DIRECTION('',(0.,1.,0.));
#2159=DIRECTION('',(0.,0.,-1.));
#2160=AXIS2_PLACEMENT_3D('',#2157,#2158,#2159);
#2161=PLANE('',#2160);
#2162=CARTESIAN_POINT('',(-16.8379802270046,62.23,16.8379802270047));
#2163=DIRECTION('',(0.,1.,0.));
#2164=DIRECTION('',(0.,0.,1.));
#2165=AXIS2_PLACEMENT_3D('',#2162,#2163,#2164);
#2166=CIRCLE('',#2165,3.9624);
#2167=CARTESIAN_POINT('',(-16.8379802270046,62.23,20.8003802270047));
#2168=VERTEX_POINT('',#2167);
#2169=EDGE_CURVE('E1288',#2168,#2168,#2166,.T.);
#2170=ORIENTED_EDGE('',*,*,#2169,.F.);
#2171=EDGE_LOOP('',(#2170));
#2172=FACE_BOUND('',#2171,.T.);
#2173=ORIENTED_EDGE('',*,*,#1108,.F.);
#2174=DIRECTION('',(0.967859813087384,0.,-0.251490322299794));
#2175=VECTOR('',#2174,1.);
#2176=CARTESIAN_POINT('',(-23.2979505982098,62.23,23.2979505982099));
#2177=LINE('',#2176,#2175);
#2178=CARTESIAN_POINT('',(-13.0427408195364,62.23,20.633219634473));
#2179=VERTEX_POINT('',#2178);
#2180=EDGE_CURVE('E1341',#201,#2179,#2177,.T.);
#2181=ORIENTED_EDGE('',*,*,#2180,.T.);
#2182=DIRECTION('',(0.258819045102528,0.,-0.965925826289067));
#2183=VECTOR('',#2182,1.);
#2184=CARTESIAN_POINT('',(-13.0427408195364,62.23,20.633219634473));
#2185=LINE('',#2184,#2183);
#2186=CARTESIAN_POINT('',(-11.6535867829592,62.23,15.4488261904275));
#2187=VERTEX_POINT('',#2186);
#2188=EDGE_CURVE('E1351',#2179,#2187,#2185,.T.);
#2189=ORIENTED_EDGE('',*,*,#2188,.T.);
#2190=DIRECTION('',(-0.707106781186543,0.,-0.707106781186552));
#2191=VECTOR('',#2190,1.);
#2192=CARTESIAN_POINT('',(-11.6535867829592,62.23,15.4488261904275));
#2193=LINE('',#2192,#2191);
#2194=CARTESIAN_POINT('',(-15.4488261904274,62.23,11.6535867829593));
#2195=VERTEX_POINT('',#2194);
#2196=EDGE_CURVE('E2111',#2187,#2195,#2193,.T.);
#2197=ORIENTED_EDGE('',*,*,#2196,.T.);
#2198=DIRECTION('',(-0.96592582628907,0.,0.258819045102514));
#2199=VECTOR('',#2198,1.);
#2200=CARTESIAN_POINT('',(-15.4488261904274,62.23,11.6535867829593));
#2201=LINE('',#2200,#2199);
#2202=CARTESIAN_POINT('',(-20.6332196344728,62.23,13.0427408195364));
#2203=VERTEX_POINT('',#2202);
#2204=EDGE_CURVE('E2122',#2195,#2203,#2201,.T.);
#2205=ORIENTED_EDGE('',*,*,#2204,.T.);
#2206=DIRECTION('',(-0.251490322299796,0.,0.967859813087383));
#2207=VECTOR('',#2206,1.);
#2208=CARTESIAN_POINT('',(-20.6332196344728,62.23,13.0427408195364));
#2209=LINE('',#2208,#2207);
#2210=EDGE_CURVE('E1345',#2203,#47,#2209,.T.);
#2211=ORIENTED_EDGE('',*,*,#2210,.T.);
#2212=EDGE_LOOP('',(#2173,#2181,#2189,#2197,#2205,#2211));
#2213=FACE_BOUND('',#2212,.T.);
#2214=ADVANCED_FACE('F651',(#2172,#2213),#2161,.T.);
#2215=CARTESIAN_POINT('',(-15.4488261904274,62.23,11.6535867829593));
#2216=DIRECTION('',(-0.258819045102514,0.,-0.96592582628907));
#2217=DIRECTION('',(-0.96592582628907,0.,0.258819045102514));
#2218=AXIS2_PLACEMENT_3D('',#2215,#2216,#2217);
#2219=PLANE('',#2218);
#2220=ORIENTED_EDGE('',*,*,#1797,.T.);
#2221=DIRECTION('',(0.,1.,0.));
#2222=VECTOR('',#2221,1.);
#2223=CARTESIAN_POINT('',(-20.6332196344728,62.23,13.0427408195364));
#2224=LINE('',#2223,#2222);
#2225=EDGE_CURVE('E2110',#2203,#1788,#2224,.T.);
#2226=ORIENTED_EDGE('',*,*,#2225,.F.);
#2227=ORIENTED_EDGE('',*,*,#2204,.F.);
#2228=DIRECTION('',(0.,1.,0.));
#2229=VECTOR('',#2228,1.);
#2230=CARTESIAN_POINT('',(-15.4488261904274,62.23,11.6535867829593));
#2231=LINE('',#2230,#2229);
#2232=EDGE_CURVE('E2100',#2195,#1796,#2231,.T.);
#2233=ORIENTED_EDGE('',*,*,#2232,.T.);
#2234=EDGE_LOOP('',(#2220,#2226,#2227,#2233));
#2235=FACE_BOUND('',#2234,.T.);
#2236=ADVANCED_FACE('F654',(#2235),#2219,.F.);
#2237=CARTESIAN_POINT('',(-11.6535867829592,62.23,15.4488261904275));
#2238=DIRECTION('',(0.707106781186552,0.,-0.707106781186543));
#2239=DIRECTION('',(-0.707106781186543,0.,-0.707106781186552));
#2240=AXIS2_PLACEMENT_3D('',#2237,#2238,#2239);
#2241=PLANE('',#2240);
#2242=ORIENTED_EDGE('',*,*,#1805,.T.);
#2243=ORIENTED_EDGE('',*,*,#2232,.F.);
#2244=ORIENTED_EDGE('',*,*,#2196,.F.);
#2245=DIRECTION('',(0.,1.,0.));
#2246=VECTOR('',#2245,1.);
#2247=CARTESIAN_POINT('',(-11.6535867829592,62.23,15.4488261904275));
#2248=LINE('',#2247,#2246);
#2249=EDGE_CURVE('E2101',#2187,#1804,#2248,.T.);
#2250=ORIENTED_EDGE('',*,*,#2249,.T.);
#2251=EDGE_LOOP('',(#2242,#2243,#2244,#2250));
#2252=FACE_BOUND('',#2251,.T.);
#2253=ADVANCED_FACE('F657',(#2252),#2241,.F.);
#2254=CARTESIAN_POINT('',(-13.0427408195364,62.23,20.633219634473));
#2255=DIRECTION('',(0.965925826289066,0.,0.258819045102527));
#2256=DIRECTION('',(0.258819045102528,0.,-0.965925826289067));
#2257=AXIS2_PLACEMENT_3D('',#2254,#2255,#2256);
#2258=PLANE('',#2257);
#2259=ORIENTED_EDGE('',*,*,#1811,.T.);
#2260=ORIENTED_EDGE('',*,*,#2249,.F.);
#2261=ORIENTED_EDGE('',*,*,#2188,.F.);
#2262=DIRECTION('',(0.,1.,0.));
#2263=VECTOR('',#2262,1.);
#2264=CARTESIAN_POINT('',(-13.0427408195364,62.23,20.633219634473));
#2265=LINE('',#2264,#2263);
#2266=EDGE_CURVE('E1349',#2179,#1777,#2265,.T.);
#2267=ORIENTED_EDGE('',*,*,#2266,.T.);
#2268=EDGE_LOOP('',(#2259,#2260,#2261,#2267));
#2269=FACE_BOUND('',#2268,.T.);
#2270=ADVANCED_FACE('F660',(#2269),#2258,.F.);
#2271=CARTESIAN_POINT('',(-23.2979505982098,62.23,23.2979505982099));
#2272=DIRECTION('',(0.251490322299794,0.,0.967859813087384));
#2273=DIRECTION('',(0.967859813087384,0.,-0.251490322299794));
#2274=AXIS2_PLACEMENT_3D('',#2271,#2272,#2273);
#2275=PLANE('',#2274);
#2276=ORIENTED_EDGE('',*,*,#202,.T.);
#2277=ORIENTED_EDGE('',*,*,#1778,.T.);
#2278=ORIENTED_EDGE('',*,*,#2266,.F.);
#2279=ORIENTED_EDGE('',*,*,#2180,.F.);
#2280=EDGE_LOOP('',(#2276,#2277,#2278,#2279));
#2281=FACE_BOUND('',#2280,.T.);
#2282=ADVANCED_FACE('F664',(#2281),#2275,.F.);
#2283=CARTESIAN_POINT('',(-20.6332196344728,62.23,13.0427408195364));
#2284=DIRECTION('',(-0.967859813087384,0.,-0.251490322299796));
#2285=DIRECTION('',(-0.251490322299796,0.,0.967859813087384));
#2286=AXIS2_PLACEMENT_3D('',#2283,#2284,#2285);
#2287=PLANE('',#2286);
#2288=ORIENTED_EDGE('',*,*,#63,.T.);
#2289=ORIENTED_EDGE('',*,*,#2210,.F.);
#2290=ORIENTED_EDGE('',*,*,#2225,.T.);
#2291=ORIENTED_EDGE('',*,*,#1789,.T.);
#2292=EDGE_LOOP('',(#2288,#2289,#2290,#2291));
#2293=FACE_BOUND('',#2292,.T.);
#2294=ADVANCED_FACE('F669',(#2293),#2287,.F.);
#2295=CARTESIAN_POINT('',(-13.0427408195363,62.23,-20.6332196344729));
#2296=DIRECTION('',(0.,1.,0.));
#2297=DIRECTION('',(1.,0.,0.));
#2298=AXIS2_PLACEMENT_3D('',#2295,#2296,#2297);
#2299=PLANE('',#2298);
#2300=CARTESIAN_POINT('',(-16.8379802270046,62.23,-16.8379802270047));
#2301=DIRECTION('',(0.,1.,0.));
#2302=DIRECTION('',(0.,0.,1.));
#2303=AXIS2_PLACEMENT_3D('',#2300,#2301,#2302);
#2304=CIRCLE('',#2303,3.9624);
#2305=CARTESIAN_POINT('',(-16.8379802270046,62.23,-12.8755802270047));
#2306=VERTEX_POINT('',#2305);
#2307=EDGE_CURVE('E1291',#2306,#2306,#2304,.T.);
#2308=ORIENTED_EDGE('',*,*,#2307,.F.);
#2309=EDGE_LOOP('',(#2308));
#2310=FACE_BOUND('',#2309,.T.);
#2311=ORIENTED_EDGE('',*,*,#1111,.F.);
#2312=DIRECTION('',(0.25149032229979,0.,0.967859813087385));
#2313=VECTOR('',#2312,1.);
#2314=CARTESIAN_POINT('',(-23.2979505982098,62.23,-23.2979505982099));
#2315=LINE('',#2314,#2313);
#2316=CARTESIAN_POINT('',(-20.6332196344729,62.23,-13.0427408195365));
#2317=VERTEX_POINT('',#2316);
#2318=EDGE_CURVE('E594',#36,#2317,#2315,.T.);
#2319=ORIENTED_EDGE('',*,*,#2318,.T.);
#2320=DIRECTION('',(0.965925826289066,0.,0.258819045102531));
#2321=VECTOR('',#2320,1.);
#2322=CARTESIAN_POINT('',(-20.6332196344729,62.23,-13.0427408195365));
#2323=LINE('',#2322,#2321);
#2324=CARTESIAN_POINT('',(-15.4488261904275,62.23,-11.6535867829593));
#2325=VERTEX_POINT('',#2324);
#2326=EDGE_CURVE('E596',#2317,#2325,#2323,.T.);
#2327=ORIENTED_EDGE('',*,*,#2326,.T.);
#2328=DIRECTION('',(0.707106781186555,0.,-0.70710678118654));
#2329=VECTOR('',#2328,1.);
#2330=CARTESIAN_POINT('',(-15.4488261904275,62.23,-11.6535867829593));
#2331=LINE('',#2330,#2329);
#2332=CARTESIAN_POINT('',(-11.6535867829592,62.23,-15.4488261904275));
#2333=VERTEX_POINT('',#2332);
#2334=EDGE_CURVE('E599',#2325,#2333,#2331,.T.);
#2335=ORIENTED_EDGE('',*,*,#2334,.T.);
#2336=DIRECTION('',(-0.258819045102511,0.,-0.965925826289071));
#2337=VECTOR('',#2336,1.);
#2338=CARTESIAN_POINT('',(-11.6535867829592,62.23,-15.4488261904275));
#2339=LINE('',#2338,#2337);
#2340=CARTESIAN_POINT('',(-13.0427408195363,62.23,-20.6332196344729));
#2341=VERTEX_POINT('',#2340);
#2342=EDGE_CURVE('E587',#2333,#2341,#2339,.T.);
#2343=ORIENTED_EDGE('',*,*,#2342,.T.);
#2344=DIRECTION('',(-0.967859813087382,0.,-0.251490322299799));
#2345=VECTOR('',#2344,1.);
#2346=CARTESIAN_POINT('',(-13.0427408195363,62.23,-20.6332196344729));
#2347=LINE('',#2346,#2345);
#2348=EDGE_CURVE('E590',#2341,#521,#2347,.T.);
#2349=ORIENTED_EDGE('',*,*,#2348,.T.);
#2350=EDGE_LOOP('',(#2311,#2319,#2327,#2335,#2343,#2349));
#2351=FACE_BOUND('',#2350,.T.);
#2352=ADVANCED_FACE('F649',(#2310,#2351),#2299,.T.);
#2353=CARTESIAN_POINT('',(-11.6535867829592,62.23,-15.4488261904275));
#2354=DIRECTION('',(0.965925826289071,0.,-0.258819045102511));
#2355=DIRECTION('',(-0.258819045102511,0.,-0.965925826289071));
#2356=AXIS2_PLACEMENT_3D('',#2353,#2354,#2355);
#2357=PLANE('',#2356);
#2358=ORIENTED_EDGE('',*,*,#1862,.T.);
#2359=DIRECTION('',(0.,1.,0.));
#2360=VECTOR('',#2359,1.);
#2361=CARTESIAN_POINT('',(-13.0427408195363,62.23,-20.6332196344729));
#2362=LINE('',#2361,#2360);
#2363=EDGE_CURVE('E602',#2341,#1853,#2362,.T.);
#2364=ORIENTED_EDGE('',*,*,#2363,.F.);
#2365=ORIENTED_EDGE('',*,*,#2342,.F.);
#2366=DIRECTION('',(0.,1.,0.));
#2367=VECTOR('',#2366,1.);
#2368=CARTESIAN_POINT('',(-11.6535867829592,62.23,-15.4488261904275));
#2369=LINE('',#2368,#2367);
#2370=EDGE_CURVE('E611',#2333,#1861,#2369,.T.);
#2371=ORIENTED_EDGE('',*,*,#2370,.T.);
#2372=EDGE_LOOP('',(#2358,#2364,#2365,#2371));
#2373=FACE_BOUND('',#2372,.T.);
#2374=ADVANCED_FACE('F645',(#2373),#2357,.F.);
#2375=CARTESIAN_POINT('',(-15.4488261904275,62.23,-11.6535867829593));
#2376=DIRECTION('',(0.70710678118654,0.,0.707106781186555));
#2377=DIRECTION('',(0.707106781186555,0.,-0.70710678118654));
#2378=AXIS2_PLACEMENT_3D('',#2375,#2376,#2377);
#2379=PLANE('',#2378);
#2380=ORIENTED_EDGE('',*,*,#1870,.T.);
#2381=ORIENTED_EDGE('',*,*,#2370,.F.);
#2382=ORIENTED_EDGE('',*,*,#2334,.F.);
#2383=DIRECTION('',(0.,1.,0.));
#2384=VECTOR('',#2383,1.);
#2385=CARTESIAN_POINT('',(-15.4488261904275,62.23,-11.6535867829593));
#2386=LINE('',#2385,#2384);
#2387=EDGE_CURVE('E614',#2325,#1869,#2386,.T.);
#2388=ORIENTED_EDGE('',*,*,#2387,.T.);
#2389=EDGE_LOOP('',(#2380,#2381,#2382,#2388));
#2390=FACE_BOUND('',#2389,.T.);
#2391=ADVANCED_FACE('F648',(#2390),#2379,.F.);
#2392=CARTESIAN_POINT('',(-20.6332196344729,62.23,-13.0427408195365));
#2393=DIRECTION('',(-0.258819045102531,0.,0.965925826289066));
#2394=DIRECTION('',(0.965925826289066,0.,0.258819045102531));
#2395=AXIS2_PLACEMENT_3D('',#2392,#2393,#2394);
#2396=PLANE('',#2395);
#2397=ORIENTED_EDGE('',*,*,#1876,.T.);
#2398=ORIENTED_EDGE('',*,*,#2387,.F.);
#2399=ORIENTED_EDGE('',*,*,#2326,.F.);
#2400=DIRECTION('',(0.,1.,0.));
#2401=VECTOR('',#2400,1.);
#2402=CARTESIAN_POINT('',(-20.6332196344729,62.23,-13.0427408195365));
#2403=LINE('',#2402,#2401);
#2404=EDGE_CURVE('E616',#2317,#1842,#2403,.T.);
#2405=ORIENTED_EDGE('',*,*,#2404,.T.);
#2406=EDGE_LOOP('',(#2397,#2398,#2399,#2405));
#2407=FACE_BOUND('',#2406,.T.);
#2408=ADVANCED_FACE('F1258',(#2407),#2396,.F.);
#2409=CARTESIAN_POINT('',(-23.2979505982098,62.23,-23.2979505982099));
#2410=DIRECTION('',(-0.967859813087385,0.,0.25149032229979));
#2411=DIRECTION('',(0.25149032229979,0.,0.967859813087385));
#2412=AXIS2_PLACEMENT_3D('',#2409,#2410,#2411);
#2413=PLANE('',#2412);
#2414=ORIENTED_EDGE('',*,*,#39,.T.);
#2415=ORIENTED_EDGE('',*,*,#1843,.T.);
#2416=ORIENTED_EDGE('',*,*,#2404,.F.);
#2417=ORIENTED_EDGE('',*,*,#2318,.F.);
#2418=EDGE_LOOP('',(#2414,#2415,#2416,#2417));
#2419=FACE_BOUND('',#2418,.T.);
#2420=ADVANCED_FACE('F641',(#2419),#2413,.F.);
#2421=CARTESIAN_POINT('',(-13.0427408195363,62.23,-20.6332196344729));
#2422=DIRECTION('',(0.251490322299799,0.,-0.967859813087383));
#2423=DIRECTION('',(-0.967859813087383,0.,-0.251490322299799));
#2424=AXIS2_PLACEMENT_3D('',#2421,#2422,#2423);
#2425=PLANE('',#2424);
#2426=ORIENTED_EDGE('',*,*,#537,.T.);
#2427=ORIENTED_EDGE('',*,*,#2348,.F.);
#2428=ORIENTED_EDGE('',*,*,#2363,.T.);
#2429=ORIENTED_EDGE('',*,*,#1854,.T.);
#2430=EDGE_LOOP('',(#2426,#2427,#2428,#2429));
#2431=FACE_BOUND('',#2430,.T.);
#2432=ADVANCED_FACE('F636',(#2431),#2425,.F.);
#2433=CARTESIAN_POINT('',(16.8379802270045,51.0226403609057,-16.8379802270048));
#2434=DIRECTION('',(0.,1.,0.));
#2435=DIRECTION('',(0.,0.,1.));
#2436=AXIS2_PLACEMENT_3D('',#2433,#2434,#2435);
#2437=CYLINDRICAL_SURFACE('',#2436,3.9624);
#2438=CARTESIAN_POINT('',(16.8379802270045,68.199,-16.8379802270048));
#2439=DIRECTION('',(0.,1.,0.));
#2440=DIRECTION('',(0.,0.,1.));
#2441=AXIS2_PLACEMENT_3D('',#2438,#2439,#2440);
#2442=CIRCLE('',#2441,3.9624);
#2443=CARTESIAN_POINT('',(16.8379802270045,68.199,-12.8755802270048));
#2444=VERTEX_POINT('',#2443);
#2445=EDGE_CURVE('E1297',#2444,#2444,#2442,.F.);
#2446=ORIENTED_EDGE('',*,*,#2445,.T.);
#2447=EDGE_LOOP('',(#2446));
#2448=FACE_BOUND('',#2447,.T.);
#2449=ORIENTED_EDGE('',*,*,#1893,.T.);
#2450=EDGE_LOOP('',(#2449));
#2451=FACE_BOUND('',#2450,.T.);
#2452=ADVANCED_FACE('F640',(#2448,#2451),#2437,.T.);
#2453=CARTESIAN_POINT('',(16.8379802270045,68.58,-16.8379802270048));
#2454=DIRECTION('',(0.,1.,0.));
#2455=DIRECTION('',(0.,0.,1.));
#2456=AXIS2_PLACEMENT_3D('',#2453,#2454,#2455);
#2457=PLANE('',#2456);
#2458=CARTESIAN_POINT('',(16.8379802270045,68.58,-16.8379802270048));
#2459=DIRECTION('',(0.,1.,0.));
#2460=DIRECTION('',(0.,0.,1.));
#2461=AXIS2_PLACEMENT_3D('',#2458,#2459,#2460);
#2462=CIRCLE('',#2461,3.58139999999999);
#2463=CARTESIAN_POINT('',(16.8379802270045,68.58,-13.2565802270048));
#2464=VERTEX_POINT('',#2463);
#2465=EDGE_CURVE('E1294',#2464,#2464,#2462,.T.);
#2466=ORIENTED_EDGE('',*,*,#2465,.T.);
#2467=EDGE_LOOP('',(#2466));
#2468=FACE_BOUND('',#2467,.T.);
#2469=DIRECTION('',(0.499999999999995,0.,-0.866025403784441));
#2470=VECTOR('',#2469,1.);
#2471=CARTESIAN_POINT('',(17.9567610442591,68.58,-14.9001950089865));
#2472=LINE('',#2471,#2470);
#2473=CARTESIAN_POINT('',(17.9567610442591,68.58,-14.9001950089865));
#2474=VERTEX_POINT('',#2473);
#2475=CARTESIAN_POINT('',(19.0755418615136,68.58,-16.8379802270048));
#2476=VERTEX_POINT('',#2475);
#2477=EDGE_CURVE('E528',#2474,#2476,#2472,.T.);
#2478=ORIENTED_EDGE('',*,*,#2477,.F.);
#2479=DIRECTION('',(1.,0.,0.));
#2480=VECTOR('',#2479,1.);
#2481=CARTESIAN_POINT('',(15.71919940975,68.58,-14.9001950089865));
#2482=LINE('',#2481,#2480);
#2483=CARTESIAN_POINT('',(15.71919940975,68.58,-14.9001950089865));
#2484=VERTEX_POINT('',#2483);
#2485=EDGE_CURVE('E543',#2484,#2474,#2482,.T.);
#2486=ORIENTED_EDGE('',*,*,#2485,.F.);
#2487=DIRECTION('',(0.500000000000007,0.,0.866025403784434));
#2488=VECTOR('',#2487,1.);
#2489=CARTESIAN_POINT('',(14.6004185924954,68.58,-16.8379802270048));
#2490=LINE('',#2489,#2488);
#2491=CARTESIAN_POINT('',(14.6004185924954,68.58,-16.8379802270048));
#2492=VERTEX_POINT('',#2491);
#2493=EDGE_CURVE('E569',#2492,#2484,#2490,.T.);
#2494=ORIENTED_EDGE('',*,*,#2493,.F.);
#2495=DIRECTION('',(-0.499999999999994,0.,0.866025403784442));
#2496=VECTOR('',#2495,1.);
#2497=CARTESIAN_POINT('',(15.71919940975,68.58,-18.7757654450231));
#2498=LINE('',#2497,#2496);
#2499=CARTESIAN_POINT('',(15.71919940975,68.58,-18.7757654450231));
#2500=VERTEX_POINT('',#2499);
#2501=EDGE_CURVE('E566',#2500,#2492,#2498,.T.);
#2502=ORIENTED_EDGE('',*,*,#2501,.F.);
#2503=DIRECTION('',(-1.,0.,0.));
#2504=VECTOR('',#2503,1.);
#2505=CARTESIAN_POINT('',(17.956761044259,68.58,-18.7757654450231));
#2506=LINE('',#2505,#2504);
#2507=CARTESIAN_POINT('',(17.956761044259,68.58,-18.7757654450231));
#2508=VERTEX_POINT('',#2507);
#2509=EDGE_CURVE('E563',#2508,#2500,#2506,.T.);
#2510=ORIENTED_EDGE('',*,*,#2509,.F.);
#2511=DIRECTION('',(-0.500000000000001,0.,-0.866025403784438));
#2512=VECTOR('',#2511,1.);
#2513=CARTESIAN_POINT('',(19.0755418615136,68.58,-16.8379802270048));
#2514=LINE('',#2513,#2512);
#2515=EDGE_CURVE('E560',#2476,#2508,#2514,.T.);
#2516=ORIENTED_EDGE('',*,*,#2515,.F.);
#2517=EDGE_LOOP('',(#2478,#2486,#2494,#2502,#2510,#2516));
#2518=FACE_BOUND('',#2517,.T.);
#2519=ADVANCED_FACE('F1246',(#2468,#2518),#2457,.T.);
#2520=CARTESIAN_POINT('',(17.9567610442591,65.405,-14.9001950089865));
#2521=DIRECTION('',(0.866025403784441,0.,0.499999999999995));
#2522=DIRECTION('',(0.499999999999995,0.,-0.866025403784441));
#2523=AXIS2_PLACEMENT_3D('',#2520,#2521,#2522);
#2524=PLANE('',#2523);
#2525=ORIENTED_EDGE('',*,*,#2477,.T.);
#2526=DIRECTION('',(0.,1.,0.));
#2527=VECTOR('',#2526,1.);
#2528=CARTESIAN_POINT('',(19.0755418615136,65.405,-16.8379802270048));
#2529=LINE('',#2528,#2527);
#2530=CARTESIAN_POINT('',(19.0755418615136,65.405,-16.8379802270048));
#2531=VERTEX_POINT('',#2530);
#2532=EDGE_CURVE('E558',#2531,#2476,#2529,.T.);
#2533=ORIENTED_EDGE('',*,*,#2532,.F.);
#2534=DIRECTION('',(0.499999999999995,0.,-0.866025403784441));
#2535=VECTOR('',#2534,1.);
#2536=CARTESIAN_POINT('',(17.9567610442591,65.405,-14.9001950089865));
#2537=LINE('',#2536,#2535);
#2538=CARTESIAN_POINT('',(17.9567610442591,65.405,-14.9001950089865));
#2539=VERTEX_POINT('',#2538);
#2540=EDGE_CURVE('E539',#2539,#2531,#2537,.T.);
#2541=ORIENTED_EDGE('',*,*,#2540,.F.);
#2542=DIRECTION('',(0.,1.,0.));
#2543=VECTOR('',#2542,1.);
#2544=CARTESIAN_POINT('',(17.9567610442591,65.405,-14.9001950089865));
#2545=LINE('',#2544,#2543);
#2546=EDGE_CURVE('E574',#2539,#2474,#2545,.T.);
#2547=ORIENTED_EDGE('',*,*,#2546,.T.);
#2548=EDGE_LOOP('',(#2525,#2533,#2541,#2547));
#2549=FACE_BOUND('',#2548,.T.);
#2550=ADVANCED_FACE('F1228',(#2549),#2524,.F.);
#2551=CARTESIAN_POINT('',(15.71919940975,65.405,-14.9001950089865));
#2552=DIRECTION('',(0.,0.,1.));
#2553=DIRECTION('',(1.,0.,0.));
#2554=AXIS2_PLACEMENT_3D('',#2551,#2552,#2553);
#2555=PLANE('',#2554);
#2556=ORIENTED_EDGE('',*,*,#2485,.T.);
#2557=ORIENTED_EDGE('',*,*,#2546,.F.);
#2558=DIRECTION('',(1.,0.,0.));
#2559=VECTOR('',#2558,1.);
#2560=CARTESIAN_POINT('',(15.71919940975,65.405,-14.9001950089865));
#2561=LINE('',#2560,#2559);
#2562=CARTESIAN_POINT('',(15.71919940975,65.405,-14.9001950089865));
#2563=VERTEX_POINT('',#2562);
#2564=EDGE_CURVE('E555',#2563,#2539,#2561,.T.);
#2565=ORIENTED_EDGE('',*,*,#2564,.F.);
#2566=DIRECTION('',(0.,1.,0.));
#2567=VECTOR('',#2566,1.);
#2568=CARTESIAN_POINT('',(15.71919940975,65.405,-14.9001950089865));
#2569=LINE('',#2568,#2567);
#2570=EDGE_CURVE('E577',#2563,#2484,#2569,.T.);
#2571=ORIENTED_EDGE('',*,*,#2570,.T.);
#2572=EDGE_LOOP('',(#2556,#2557,#2565,#2571));
#2573=FACE_BOUND('',#2572,.T.);
#2574=ADVANCED_FACE('F1224',(#2573),#2555,.F.);
#2575=CARTESIAN_POINT('',(14.6004185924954,65.405,-16.8379802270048));
#2576=DIRECTION('',(-0.866025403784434,0.,0.500000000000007));
#2577=DIRECTION('',(0.500000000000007,0.,0.866025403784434));
#2578=AXIS2_PLACEMENT_3D('',#2575,#2576,#2577);
#2579=PLANE('',#2578);
#2580=ORIENTED_EDGE('',*,*,#2493,.T.);
#2581=ORIENTED_EDGE('',*,*,#2570,.F.);
#2582=DIRECTION('',(0.500000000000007,0.,0.866025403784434));
#2583=VECTOR('',#2582,1.);
#2584=CARTESIAN_POINT('',(14.6004185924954,65.405,-16.8379802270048));
#2585=LINE('',#2584,#2583);
#2586=CARTESIAN_POINT('',(14.6004185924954,65.405,-16.8379802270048));
#2587=VERTEX_POINT('',#2586);
#2588=EDGE_CURVE('E552',#2587,#2563,#2585,.T.);
#2589=ORIENTED_EDGE('',*,*,#2588,.F.);
#2590=DIRECTION('',(0.,1.,0.));
#2591=VECTOR('',#2590,1.);
#2592=CARTESIAN_POINT('',(14.6004185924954,65.405,-16.8379802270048));
#2593=LINE('',#2592,#2591);
#2594=EDGE_CURVE('E579',#2587,#2492,#2593,.T.);
#2595=ORIENTED_EDGE('',*,*,#2594,.T.);
#2596=EDGE_LOOP('',(#2580,#2581,#2589,#2595));
#2597=FACE_BOUND('',#2596,.T.);
#2598=ADVANCED_FACE('F1227',(#2597),#2579,.F.);
#2599=CARTESIAN_POINT('',(15.71919940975,65.405,-18.7757654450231));
#2600=DIRECTION('',(-0.866025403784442,0.,-0.499999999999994));
#2601=DIRECTION('',(-0.499999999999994,0.,0.866025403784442));
#2602=AXIS2_PLACEMENT_3D('',#2599,#2600,#2601);
#2603=PLANE('',#2602);
#2604=ORIENTED_EDGE('',*,*,#2501,.T.);
#2605=ORIENTED_EDGE('',*,*,#2594,.F.);
#2606=DIRECTION('',(-0.499999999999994,0.,0.866025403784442));
#2607=VECTOR('',#2606,1.);
#2608=CARTESIAN_POINT('',(15.71919940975,65.405,-18.7757654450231));
#2609=LINE('',#2608,#2607);
#2610=CARTESIAN_POINT('',(15.71919940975,65.405,-18.7757654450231));
#2611=VERTEX_POINT('',#2610);
#2612=EDGE_CURVE('E549',#2611,#2587,#2609,.T.);
#2613=ORIENTED_EDGE('',*,*,#2612,.F.);
#2614=DIRECTION('',(0.,1.,0.));
#2615=VECTOR('',#2614,1.);
#2616=CARTESIAN_POINT('',(15.71919940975,65.405,-18.7757654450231));
#2617=LINE('',#2616,#2615);
#2618=EDGE_CURVE('E581',#2611,#2500,#2617,.T.);
#2619=ORIENTED_EDGE('',*,*,#2618,.T.);
#2620=EDGE_LOOP('',(#2604,#2605,#2613,#2619));
#2621=FACE_BOUND('',#2620,.T.);
#2622=ADVANCED_FACE('F1232',(#2621),#2603,.F.);
#2623=CARTESIAN_POINT('',(17.956761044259,65.405,-18.7757654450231));
#2624=DIRECTION('',(0.,0.,-1.));
#2625=DIRECTION('',(-1.,0.,0.));
#2626=AXIS2_PLACEMENT_3D('',#2623,#2624,#2625);
#2627=PLANE('',#2626);
#2628=ORIENTED_EDGE('',*,*,#2509,.T.);
#2629=ORIENTED_EDGE('',*,*,#2618,.F.);
#2630=DIRECTION('',(-1.,0.,0.));
#2631=VECTOR('',#2630,1.);
#2632=CARTESIAN_POINT('',(17.956761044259,65.405,-18.7757654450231));
#2633=LINE('',#2632,#2631);
#2634=CARTESIAN_POINT('',(17.956761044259,65.405,-18.7757654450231));
#2635=VERTEX_POINT('',#2634);
#2636=EDGE_CURVE('E546',#2635,#2611,#2633,.T.);
#2637=ORIENTED_EDGE('',*,*,#2636,.F.);
#2638=DIRECTION('',(0.,1.,0.));
#2639=VECTOR('',#2638,1.);
#2640=CARTESIAN_POINT('',(17.956761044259,65.405,-18.7757654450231));
#2641=LINE('',#2640,#2639);
#2642=EDGE_CURVE('E583',#2635,#2508,#2641,.T.);
#2643=ORIENTED_EDGE('',*,*,#2642,.T.);
#2644=EDGE_LOOP('',(#2628,#2629,#2637,#2643));
#2645=FACE_BOUND('',#2644,.T.);
#2646=ADVANCED_FACE('F1236',(#2645),#2627,.F.);
#2647=CARTESIAN_POINT('',(19.0755418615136,65.405,-16.8379802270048));
#2648=DIRECTION('',(0.866025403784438,0.,-0.500000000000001));
#2649=DIRECTION('',(-0.500000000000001,0.,-0.866025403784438));
#2650=AXIS2_PLACEMENT_3D('',#2647,#2648,#2649);
#2651=PLANE('',#2650);
#2652=ORIENTED_EDGE('',*,*,#2515,.T.);
#2653=ORIENTED_EDGE('',*,*,#2642,.F.);
#2654=DIRECTION('',(-0.500000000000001,0.,-0.866025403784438));
#2655=VECTOR('',#2654,1.);
#2656=CARTESIAN_POINT('',(19.0755418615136,65.405,-16.8379802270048));
#2657=LINE('',#2656,#2655);
#2658=EDGE_CURVE('E542',#2531,#2635,#2657,.T.);
#2659=ORIENTED_EDGE('',*,*,#2658,.F.);
#2660=ORIENTED_EDGE('',*,*,#2532,.T.);
#2661=EDGE_LOOP('',(#2652,#2653,#2659,#2660));
#2662=FACE_BOUND('',#2661,.T.);
#2663=ADVANCED_FACE('F1222',(#2662),#2651,.F.);
#2664=CARTESIAN_POINT('',(19.0755418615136,65.405,-16.8379802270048));
#2665=DIRECTION('',(0.,1.,0.));
#2666=DIRECTION('',(0.,0.,1.));
#2667=AXIS2_PLACEMENT_3D('',#2664,#2665,#2666);
#2668=PLANE('',#2667);
#2669=ORIENTED_EDGE('',*,*,#2540,.T.);
#2670=ORIENTED_EDGE('',*,*,#2658,.T.);
#2671=ORIENTED_EDGE('',*,*,#2636,.T.);
#2672=ORIENTED_EDGE('',*,*,#2612,.T.);
#2673=ORIENTED_EDGE('',*,*,#2588,.T.);
#2674=ORIENTED_EDGE('',*,*,#2564,.T.);
#2675=EDGE_LOOP('',(#2669,#2670,#2671,#2672,#2673,#2674));
#2676=FACE_BOUND('',#2675,.T.);
#2677=ADVANCED_FACE('F1218',(#2676),#2668,.T.);
#2678=CARTESIAN_POINT('',(16.8379802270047,51.0226403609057,16.8379802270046));
#2679=DIRECTION('',(0.,1.,0.));
#2680=DIRECTION('',(0.,0.,1.));
#2681=AXIS2_PLACEMENT_3D('',#2678,#2679,#2680);
#2682=CYLINDRICAL_SURFACE('',#2681,3.9624);
#2683=CARTESIAN_POINT('',(16.8379802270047,68.199,16.8379802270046));
#2684=DIRECTION('',(0.,1.,0.));
#2685=DIRECTION('',(0.,0.,1.));
#2686=AXIS2_PLACEMENT_3D('',#2683,#2684,#2685);
#2687=CIRCLE('',#2686,3.9624);
#2688=CARTESIAN_POINT('',(16.8379802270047,68.199,20.8003802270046));
#2689=VERTEX_POINT('',#2688);
#2690=EDGE_CURVE('E1100',#2689,#2689,#2687,.F.);
#2691=ORIENTED_EDGE('',*,*,#2690,.T.);
#2692=EDGE_LOOP('',(#2691));
#2693=FACE_BOUND('',#2692,.T.);
#2694=ORIENTED_EDGE('',*,*,#2031,.T.);
#2695=EDGE_LOOP('',(#2694));
#2696=FACE_BOUND('',#2695,.T.);
#2697=ADVANCED_FACE('F1214',(#2693,#2696),#2682,.T.);
#2698=CARTESIAN_POINT('',(16.8379802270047,68.58,16.8379802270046));
#2699=DIRECTION('',(0.,1.,0.));
#2700=DIRECTION('',(-1.,0.,0.));
#2701=AXIS2_PLACEMENT_3D('',#2698,#2699,#2700);
#2702=PLANE('',#2701);
#2703=CARTESIAN_POINT('',(16.8379802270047,68.58,16.8379802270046));
#2704=DIRECTION('',(0.,1.,0.));
#2705=DIRECTION('',(0.,0.,1.));
#2706=AXIS2_PLACEMENT_3D('',#2703,#2704,#2705);
#2707=CIRCLE('',#2706,3.58139999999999);
#2708=CARTESIAN_POINT('',(16.8379802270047,68.58,20.4193802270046));
#2709=VERTEX_POINT('',#2708);
#2710=EDGE_CURVE('E1104',#2709,#2709,#2707,.T.);
#2711=ORIENTED_EDGE('',*,*,#2710,.T.);
#2712=EDGE_LOOP('',(#2711));
#2713=FACE_BOUND('',#2712,.T.);
#2714=DIRECTION('',(0.866025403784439,0.,0.499999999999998));
#2715=VECTOR('',#2714,1.);
#2716=CARTESIAN_POINT('',(14.9001950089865,68.58,17.9567610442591));
#2717=LINE('',#2716,#2715);
#2718=CARTESIAN_POINT('',(14.9001950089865,68.58,17.9567610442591));
#2719=VERTEX_POINT('',#2718);
#2720=CARTESIAN_POINT('',(16.8379802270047,68.58,19.0755418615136));
#2721=VERTEX_POINT('',#2720);
#2722=EDGE_CURVE('E481',#2719,#2721,#2717,.T.);
#2723=ORIENTED_EDGE('',*,*,#2722,.F.);
#2724=DIRECTION('',(0.,0.,1.));
#2725=VECTOR('',#2724,1.);
#2726=CARTESIAN_POINT('',(14.9001950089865,68.58,15.71919940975));
#2727=LINE('',#2726,#2725);
#2728=CARTESIAN_POINT('',(14.9001950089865,68.58,15.71919940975));
#2729=VERTEX_POINT('',#2728);
#2730=EDGE_CURVE('E495',#2729,#2719,#2727,.T.);
#2731=ORIENTED_EDGE('',*,*,#2730,.F.);
#2732=DIRECTION('',(-0.866025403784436,0.,0.500000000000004));
#2733=VECTOR('',#2732,1.);
#2734=CARTESIAN_POINT('',(16.8379802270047,68.58,14.6004185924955));
#2735=LINE('',#2734,#2733);
#2736=CARTESIAN_POINT('',(16.8379802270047,68.58,14.6004185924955));
#2737=VERTEX_POINT('',#2736);
#2738=EDGE_CURVE('E521',#2737,#2729,#2735,.T.);
#2739=ORIENTED_EDGE('',*,*,#2738,.F.);
#2740=DIRECTION('',(-0.86602540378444,0.,-0.499999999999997));
#2741=VECTOR('',#2740,1.);
#2742=CARTESIAN_POINT('',(18.775765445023,68.58,15.71919940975));
#2743=LINE('',#2742,#2741);
#2744=CARTESIAN_POINT('',(18.775765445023,68.58,15.71919940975));
#2745=VERTEX_POINT('',#2744);
#2746=EDGE_CURVE('E518',#2745,#2737,#2743,.T.);
#2747=ORIENTED_EDGE('',*,*,#2746,.F.);
#2748=DIRECTION('',(0.,0.,-1.));
#2749=VECTOR('',#2748,1.);
#2750=CARTESIAN_POINT('',(18.775765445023,68.58,17.9567610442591));
#2751=LINE('',#2750,#2749);
#2752=CARTESIAN_POINT('',(18.775765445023,68.58,17.9567610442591));
#2753=VERTEX_POINT('',#2752);
#2754=EDGE_CURVE('E515',#2753,#2745,#2751,.T.);
#2755=ORIENTED_EDGE('',*,*,#2754,.F.);
#2756=DIRECTION('',(0.86602540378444,0.,-0.499999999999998));
#2757=VECTOR('',#2756,1.);
#2758=CARTESIAN_POINT('',(16.8379802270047,68.58,19.0755418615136));
#2759=LINE('',#2758,#2757);
#2760=EDGE_CURVE('E512',#2721,#2753,#2759,.T.);
#2761=ORIENTED_EDGE('',*,*,#2760,.F.);
#2762=EDGE_LOOP('',(#2723,#2731,#2739,#2747,#2755,#2761));
#2763=FACE_BOUND('',#2762,.T.);
#2764=ADVANCED_FACE('F1210',(#2713,#2763),#2702,.T.);
#2765=CARTESIAN_POINT('',(-16.8379802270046,51.0226403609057,16.8379802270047));
#2766=DIRECTION('',(0.,1.,0.));
#2767=DIRECTION('',(0.,0.,1.));
#2768=AXIS2_PLACEMENT_3D('',#2765,#2766,#2767);
#2769=CYLINDRICAL_SURFACE('',#2768,3.9624);
#2770=CARTESIAN_POINT('',(-16.8379802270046,68.199,16.8379802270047));
#2771=DIRECTION('',(0.,1.,0.));
#2772=DIRECTION('',(0.,0.,1.));
#2773=AXIS2_PLACEMENT_3D('',#2770,#2771,#2772);
#2774=CIRCLE('',#2773,3.9624);
#2775=CARTESIAN_POINT('',(-16.8379802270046,68.199,20.8003802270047));
#2776=VERTEX_POINT('',#2775);
#2777=EDGE_CURVE('E1095',#2776,#2776,#2774,.F.);
#2778=ORIENTED_EDGE('',*,*,#2777,.T.);
#2779=EDGE_LOOP('',(#2778));
#2780=FACE_BOUND('',#2779,.T.);
#2781=ORIENTED_EDGE('',*,*,#2169,.T.);
#2782=EDGE_LOOP('',(#2781));
#2783=FACE_BOUND('',#2782,.T.);
#2784=ADVANCED_FACE('F1207',(#2780,#2783),#2769,.T.);
#2785=CARTESIAN_POINT('',(-16.8379802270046,68.58,16.8379802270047));
#2786=DIRECTION('',(0.,1.,0.));
#2787=DIRECTION('',(0.,0.,-1.));
#2788=AXIS2_PLACEMENT_3D('',#2785,#2786,#2787);
#2789=PLANE('',#2788);
#2790=CARTESIAN_POINT('',(-16.8379802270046,68.58,16.8379802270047));
#2791=DIRECTION('',(0.,1.,0.));
#2792=DIRECTION('',(0.,0.,1.));
#2793=AXIS2_PLACEMENT_3D('',#2790,#2791,#2792);
#2794=CIRCLE('',#2793,3.58139999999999);
#2795=CARTESIAN_POINT('',(-16.8379802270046,68.58,20.4193802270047));
#2796=VERTEX_POINT('',#2795);
#2797=EDGE_CURVE('E1098',#2796,#2796,#2794,.T.);
#2798=ORIENTED_EDGE('',*,*,#2797,.T.);
#2799=EDGE_LOOP('',(#2798));
#2800=FACE_BOUND('',#2799,.T.);
#2801=DIRECTION('',(-0.500000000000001,0.,0.866025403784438));
#2802=VECTOR('',#2801,1.);
#2803=CARTESIAN_POINT('',(-17.9567610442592,68.58,14.9001950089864));
#2804=LINE('',#2803,#2802);
#2805=CARTESIAN_POINT('',(-17.9567610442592,68.58,14.9001950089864));
#2806=VERTEX_POINT('',#2805);
#2807=CARTESIAN_POINT('',(-19.0755418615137,68.58,16.8379802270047));
#2808=VERTEX_POINT('',#2807);
#2809=EDGE_CURVE('E54',#2806,#2808,#2804,.T.);
#2810=ORIENTED_EDGE('',*,*,#2809,.F.);
#2811=DIRECTION('',(-1.,0.,0.));
#2812=VECTOR('',#2811,1.);
#2813=CARTESIAN_POINT('',(-15.7191994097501,68.58,14.9001950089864));
#2814=LINE('',#2813,#2812);
#2815=CARTESIAN_POINT('',(-15.7191994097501,68.58,14.9001950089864));
#2816=VERTEX_POINT('',#2815);
#2817=EDGE_CURVE('E448',#2816,#2806,#2814,.T.);
#2818=ORIENTED_EDGE('',*,*,#2817,.F.);
#2819=DIRECTION('',(-0.500000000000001,0.,-0.866025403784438));
#2820=VECTOR('',#2819,1.);
#2821=CARTESIAN_POINT('',(-14.6004185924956,68.58,16.8379802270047));
#2822=LINE('',#2821,#2820);
#2823=CARTESIAN_POINT('',(-14.6004185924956,68.58,16.8379802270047));
#2824=VERTEX_POINT('',#2823);
#2825=EDGE_CURVE('E474',#2824,#2816,#2822,.T.);
#2826=ORIENTED_EDGE('',*,*,#2825,.F.);
#2827=DIRECTION('',(0.5,0.,-0.866025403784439));
#2828=VECTOR('',#2827,1.);
#2829=CARTESIAN_POINT('',(-15.7191994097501,68.58,18.775765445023));
#2830=LINE('',#2829,#2828);
#2831=CARTESIAN_POINT('',(-15.7191994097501,68.58,18.775765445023));
#2832=VERTEX_POINT('',#2831);
#2833=EDGE_CURVE('E471',#2832,#2824,#2830,.T.);
#2834=ORIENTED_EDGE('',*,*,#2833,.F.);
#2835=DIRECTION('',(1.,0.,0.));
#2836=VECTOR('',#2835,1.);
#2837=CARTESIAN_POINT('',(-17.9567610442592,68.58,18.775765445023));
#2838=LINE('',#2837,#2836);
#2839=CARTESIAN_POINT('',(-17.9567610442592,68.58,18.775765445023));
#2840=VERTEX_POINT('',#2839);
#2841=EDGE_CURVE('E468',#2840,#2832,#2838,.T.);
#2842=ORIENTED_EDGE('',*,*,#2841,.F.);
#2843=DIRECTION('',(0.499999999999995,0.,0.866025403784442));
#2844=VECTOR('',#2843,1.);
#2845=CARTESIAN_POINT('',(-19.0755418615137,68.58,16.8379802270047));
#2846=LINE('',#2845,#2844);
#2847=EDGE_CURVE('E465',#2808,#2840,#2846,.T.);
#2848=ORIENTED_EDGE('',*,*,#2847,.F.);
#2849=EDGE_LOOP('',(#2810,#2818,#2826,#2834,#2842,#2848));
#2850=FACE_BOUND('',#2849,.T.);
#2851=ADVANCED_FACE('F1203',(#2800,#2850),#2789,.T.);
#2852=CARTESIAN_POINT('',(-16.8379802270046,51.0226403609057,-16.8379802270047));
#2853=DIRECTION('',(0.,1.,0.));
#2854=DIRECTION('',(0.,0.,1.));
#2855=AXIS2_PLACEMENT_3D('',#2852,#2853,#2854);
#2856=CYLINDRICAL_SURFACE('',#2855,3.9624);
#2857=CARTESIAN_POINT('',(-16.8379802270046,68.199,-16.8379802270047));
#2858=DIRECTION('',(0.,1.,0.));
#2859=DIRECTION('',(0.,0.,1.));
#2860=AXIS2_PLACEMENT_3D('',#2857,#2858,#2859);
#2861=CIRCLE('',#2860,3.9624);
#2862=CARTESIAN_POINT('',(-16.8379802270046,68.199,-12.8755802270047));
#2863=VERTEX_POINT('',#2862);
#2864=EDGE_CURVE('E11',#2863,#2863,#2861,.F.);
#2865=ORIENTED_EDGE('',*,*,#2864,.T.);
#2866=EDGE_LOOP('',(#2865));
#2867=FACE_BOUND('',#2866,.T.);
#2868=ORIENTED_EDGE('',*,*,#2307,.T.);
#2869=EDGE_LOOP('',(#2868));
#2870=FACE_BOUND('',#2869,.T.);
#2871=ADVANCED_FACE('F1115',(#2867,#2870),#2856,.T.);
#2872=CARTESIAN_POINT('',(-16.8379802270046,68.58,-16.8379802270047));
#2873=DIRECTION('',(0.,1.,0.));
#2874=DIRECTION('',(1.,0.,0.));
#2875=AXIS2_PLACEMENT_3D('',#2872,#2873,#2874);
#2876=PLANE('',#2875);
#2877=CARTESIAN_POINT('',(-16.8379802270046,68.58,-16.8379802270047));
#2878=DIRECTION('',(0.,1.,0.));
#2879=DIRECTION('',(0.,0.,1.));
#2880=AXIS2_PLACEMENT_3D('',#2877,#2878,#2879);
#2881=CIRCLE('',#2880,3.58139999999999);
#2882=CARTESIAN_POINT('',(-16.8379802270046,68.58,-13.2565802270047));
#2883=VERTEX_POINT('',#2882);
#2884=EDGE_CURVE('E39',#2883,#2883,#2881,.T.);
#2885=ORIENTED_EDGE('',*,*,#2884,.T.);
#2886=EDGE_LOOP('',(#2885));
#2887=FACE_BOUND('',#2886,.T.);
#2888=DIRECTION('',(-0.866025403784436,0.,-0.500000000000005));
#2889=VECTOR('',#2888,1.);
#2890=CARTESIAN_POINT('',(-14.9001950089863,68.58,-17.9567610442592));
#2891=LINE('',#2890,#2889);
#2892=CARTESIAN_POINT('',(-14.9001950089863,68.58,-17.9567610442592));
#2893=VERTEX_POINT('',#2892);
#2894=CARTESIAN_POINT('',(-16.8379802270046,68.58,-19.0755418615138));
#2895=VERTEX_POINT('',#2894);
#2896=EDGE_CURVE('E46',#2893,#2895,#2891,.T.);
#2897=ORIENTED_EDGE('',*,*,#2896,.F.);
#2898=DIRECTION('',(0.,0.,-1.));
#2899=VECTOR('',#2898,1.);
#2900=CARTESIAN_POINT('',(-14.9001950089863,68.58,-15.7191994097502));
#2901=LINE('',#2900,#2899);
#2902=CARTESIAN_POINT('',(-14.9001950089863,68.58,-15.7191994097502));
#2903=VERTEX_POINT('',#2902);
#2904=EDGE_CURVE('E411',#2903,#2893,#2901,.T.);
#2905=ORIENTED_EDGE('',*,*,#2904,.F.);
#2906=DIRECTION('',(0.86602540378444,0.,-0.499999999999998));
#2907=VECTOR('',#2906,1.);
#2908=CARTESIAN_POINT('',(-16.8379802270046,68.58,-14.6004185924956));
#2909=LINE('',#2908,#2907);
#2910=CARTESIAN_POINT('',(-16.8379802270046,68.58,-14.6004185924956));
#2911=VERTEX_POINT('',#2910);
#2912=EDGE_CURVE('E414',#2911,#2903,#2909,.T.);
#2913=ORIENTED_EDGE('',*,*,#2912,.F.);
#2914=DIRECTION('',(0.866025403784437,0.,0.500000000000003));
#2915=VECTOR('',#2914,1.);
#2916=CARTESIAN_POINT('',(-18.7757654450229,68.58,-15.7191994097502));
#2917=LINE('',#2916,#2915);
#2918=CARTESIAN_POINT('',(-18.7757654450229,68.58,-15.7191994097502));
#2919=VERTEX_POINT('',#2918);
#2920=EDGE_CURVE('E430',#2919,#2911,#2917,.T.);
#2921=ORIENTED_EDGE('',*,*,#2920,.F.);
#2922=DIRECTION('',(0.,0.,1.));
#2923=VECTOR('',#2922,1.);
#2924=CARTESIAN_POINT('',(-18.7757654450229,68.58,-17.9567610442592));
#2925=LINE('',#2924,#2923);
#2926=CARTESIAN_POINT('',(-18.7757654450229,68.58,-17.9567610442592));
#2927=VERTEX_POINT('',#2926);
#2928=EDGE_CURVE('E427',#2927,#2919,#2925,.T.);
#2929=ORIENTED_EDGE('',*,*,#2928,.F.);
#2930=DIRECTION('',(-0.866025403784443,0.,0.499999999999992));
#2931=VECTOR('',#2930,1.);
#2932=CARTESIAN_POINT('',(-16.8379802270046,68.58,-19.0755418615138));
#2933=LINE('',#2932,#2931);
#2934=EDGE_CURVE('E425',#2895,#2927,#2933,.T.);
#2935=ORIENTED_EDGE('',*,*,#2934,.F.);
#2936=EDGE_LOOP('',(#2897,#2905,#2913,#2921,#2929,#2935));
#2937=FACE_BOUND('',#2936,.T.);
#2938=ADVANCED_FACE('F1110',(#2887,#2937),#2876,.T.);
#2939=CARTESIAN_POINT('',(14.9001950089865,65.405,17.9567610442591));
#2940=DIRECTION('',(-0.499999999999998,0.,0.866025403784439));
#2941=DIRECTION('',(0.86602540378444,0.,0.499999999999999));
#2942=AXIS2_PLACEMENT_3D('',#2939,#2940,#2941);
#2943=PLANE('',#2942);
#2944=ORIENTED_EDGE('',*,*,#2722,.T.);
#2945=DIRECTION('',(0.,1.,0.));
#2946=VECTOR('',#2945,1.);
#2947=CARTESIAN_POINT('',(16.8379802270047,65.405,19.0755418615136));
#2948=LINE('',#2947,#2946);
#2949=CARTESIAN_POINT('',(16.8379802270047,65.405,19.0755418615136));
#2950=VERTEX_POINT('',#2949);
#2951=EDGE_CURVE('E510',#2950,#2721,#2948,.T.);
#2952=ORIENTED_EDGE('',*,*,#2951,.F.);
#2953=DIRECTION('',(0.866025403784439,0.,0.499999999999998));
#2954=VECTOR('',#2953,1.);
#2955=CARTESIAN_POINT('',(14.9001950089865,65.405,17.9567610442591));
#2956=LINE('',#2955,#2954);
#2957=CARTESIAN_POINT('',(14.9001950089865,65.405,17.9567610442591));
#2958=VERTEX_POINT('',#2957);
#2959=EDGE_CURVE('E491',#2958,#2950,#2956,.T.);
#2960=ORIENTED_EDGE('',*,*,#2959,.F.);
#2961=DIRECTION('',(0.,1.,0.));
#2962=VECTOR('',#2961,1.);
#2963=CARTESIAN_POINT('',(14.9001950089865,65.405,17.9567610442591));
#2964=LINE('',#2963,#2962);
#2965=EDGE_CURVE('E526',#2958,#2719,#2964,.T.);
#2966=ORIENTED_EDGE('',*,*,#2965,.T.);
#2967=EDGE_LOOP('',(#2944,#2952,#2960,#2966));
#2968=FACE_BOUND('',#2967,.T.);
#2969=ADVANCED_FACE('F1114',(#2968),#2943,.F.);
#2970=CARTESIAN_POINT('',(14.9001950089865,65.405,15.71919940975));
#2971=DIRECTION('',(-1.,0.,0.));
#2972=DIRECTION('',(0.,0.,1.));
#2973=AXIS2_PLACEMENT_3D('',#2970,#2971,#2972);
#2974=PLANE('',#2973);
#2975=ORIENTED_EDGE('',*,*,#2730,.T.);
#2976=ORIENTED_EDGE('',*,*,#2965,.F.);
#2977=DIRECTION('',(0.,0.,1.));
#2978=VECTOR('',#2977,1.);
#2979=CARTESIAN_POINT('',(14.9001950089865,65.405,15.71919940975));
#2980=LINE('',#2979,#2978);
#2981=CARTESIAN_POINT('',(14.9001950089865,65.405,15.71919940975));
#2982=VERTEX_POINT('',#2981);
#2983=EDGE_CURVE('E507',#2982,#2958,#2980,.T.);
#2984=ORIENTED_EDGE('',*,*,#2983,.F.);
#2985=DIRECTION('',(0.,1.,0.));
#2986=VECTOR('',#2985,1.);
#2987=CARTESIAN_POINT('',(14.9001950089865,65.405,15.71919940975));
#2988=LINE('',#2987,#2986);
#2989=EDGE_CURVE('E529',#2982,#2729,#2988,.T.);
#2990=ORIENTED_EDGE('',*,*,#2989,.T.);
#2991=EDGE_LOOP('',(#2975,#2976,#2984,#2990));
#2992=FACE_BOUND('',#2991,.T.);
#2993=ADVANCED_FACE('F1179',(#2992),#2974,.F.);
#2994=CARTESIAN_POINT('',(16.8379802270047,65.405,14.6004185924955));
#2995=DIRECTION('',(-0.500000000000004,0.,-0.866025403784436));
#2996=DIRECTION('',(-0.866025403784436,0.,0.500000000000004));
#2997=AXIS2_PLACEMENT_3D('',#2994,#2995,#2996);
#2998=PLANE('',#2997);
#2999=ORIENTED_EDGE('',*,*,#2738,.T.);
#3000=ORIENTED_EDGE('',*,*,#2989,.F.);
#3001=DIRECTION('',(-0.866025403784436,0.,0.500000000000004));
#3002=VECTOR('',#3001,1.);
#3003=CARTESIAN_POINT('',(16.8379802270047,65.405,14.6004185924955));
#3004=LINE('',#3003,#3002);
#3005=CARTESIAN_POINT('',(16.8379802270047,65.405,14.6004185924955));
#3006=VERTEX_POINT('',#3005);
#3007=EDGE_CURVE('E504',#3006,#2982,#3004,.T.);
#3008=ORIENTED_EDGE('',*,*,#3007,.F.);
#3009=DIRECTION('',(0.,1.,0.));
#3010=VECTOR('',#3009,1.);
#3011=CARTESIAN_POINT('',(16.8379802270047,65.405,14.6004185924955));
#3012=LINE('',#3011,#3010);
#3013=EDGE_CURVE('E531',#3006,#2737,#3012,.T.);
#3014=ORIENTED_EDGE('',*,*,#3013,.T.);
#3015=EDGE_LOOP('',(#2999,#3000,#3008,#3014));
#3016=FACE_BOUND('',#3015,.T.);
#3017=ADVANCED_FACE('F1182',(#3016),#2998,.F.);
#3018=CARTESIAN_POINT('',(18.775765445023,65.405,15.71919940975));
#3019=DIRECTION('',(0.499999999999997,0.,-0.86602540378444));
#3020=DIRECTION('',(-0.866025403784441,0.,-0.499999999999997));
#3021=AXIS2_PLACEMENT_3D('',#3018,#3019,#3020);
#3022=PLANE('',#3021);
#3023=ORIENTED_EDGE('',*,*,#2746,.T.);
#3024=ORIENTED_EDGE('',*,*,#3013,.F.);
#3025=DIRECTION('',(-0.86602540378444,0.,-0.499999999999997));
#3026=VECTOR('',#3025,1.);
#3027=CARTESIAN_POINT('',(18.775765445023,65.405,15.71919940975));
#3028=LINE('',#3027,#3026);
#3029=CARTESIAN_POINT('',(18.775765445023,65.405,15.71919940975));
#3030=VERTEX_POINT('',#3029);
#3031=EDGE_CURVE('E501',#3030,#3006,#3028,.T.);
#3032=ORIENTED_EDGE('',*,*,#3031,.F.);
#3033=DIRECTION('',(0.,1.,0.));
#3034=VECTOR('',#3033,1.);
#3035=CARTESIAN_POINT('',(18.775765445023,65.405,15.71919940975));
#3036=LINE('',#3035,#3034);
#3037=EDGE_CURVE('E533',#3030,#2745,#3036,.T.);
#3038=ORIENTED_EDGE('',*,*,#3037,.T.);
#3039=EDGE_LOOP('',(#3023,#3024,#3032,#3038));
#3040=FACE_BOUND('',#3039,.T.);
#3041=ADVANCED_FACE('F1186',(#3040),#3022,.F.);
#3042=CARTESIAN_POINT('',(18.775765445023,65.405,17.9567610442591));
#3043=DIRECTION('',(1.,0.,0.));
#3044=DIRECTION('',(0.,0.,-1.));
#3045=AXIS2_PLACEMENT_3D('',#3042,#3043,#3044);
#3046=PLANE('',#3045);
#3047=ORIENTED_EDGE('',*,*,#2754,.T.);
#3048=ORIENTED_EDGE('',*,*,#3037,.F.);
#3049=DIRECTION('',(0.,0.,-1.));
#3050=VECTOR('',#3049,1.);
#3051=CARTESIAN_POINT('',(18.775765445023,65.405,17.9567610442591));
#3052=LINE('',#3051,#3050);
#3053=CARTESIAN_POINT('',(18.775765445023,65.405,17.9567610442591));
#3054=VERTEX_POINT('',#3053);
#3055=EDGE_CURVE('E498',#3054,#3030,#3052,.T.);
#3056=ORIENTED_EDGE('',*,*,#3055,.F.);
#3057=DIRECTION('',(0.,1.,0.));
#3058=VECTOR('',#3057,1.);
#3059=CARTESIAN_POINT('',(18.775765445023,65.405,17.9567610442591));
#3060=LINE('',#3059,#3058);
#3061=EDGE_CURVE('E535',#3054,#2753,#3060,.T.);
#3062=ORIENTED_EDGE('',*,*,#3061,.T.);
#3063=EDGE_LOOP('',(#3047,#3048,#3056,#3062));
#3064=FACE_BOUND('',#3063,.T.);
#3065=ADVANCED_FACE('F1190',(#3064),#3046,.F.);
#3066=CARTESIAN_POINT('',(16.8379802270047,65.405,19.0755418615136));
#3067=DIRECTION('',(0.499999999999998,0.,0.86602540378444));
#3068=DIRECTION('',(0.86602540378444,0.,-0.499999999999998));
#3069=AXIS2_PLACEMENT_3D('',#3066,#3067,#3068);
#3070=PLANE('',#3069);
#3071=ORIENTED_EDGE('',*,*,#2760,.T.);
#3072=ORIENTED_EDGE('',*,*,#3061,.F.);
#3073=DIRECTION('',(0.86602540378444,0.,-0.499999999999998));
#3074=VECTOR('',#3073,1.);
#3075=CARTESIAN_POINT('',(16.8379802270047,65.405,19.0755418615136));
#3076=LINE('',#3075,#3074);
#3077=EDGE_CURVE('E494',#2950,#3054,#3076,.T.);
#3078=ORIENTED_EDGE('',*,*,#3077,.F.);
#3079=ORIENTED_EDGE('',*,*,#2951,.T.);
#3080=EDGE_LOOP('',(#3071,#3072,#3078,#3079));
#3081=FACE_BOUND('',#3080,.T.);
#3082=ADVANCED_FACE('F1177',(#3081),#3070,.F.);
#3083=CARTESIAN_POINT('',(16.8379802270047,65.405,19.0755418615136));
#3084=DIRECTION('',(0.,1.,0.));
#3085=DIRECTION('',(-1.,0.,0.));
#3086=AXIS2_PLACEMENT_3D('',#3083,#3084,#3085);
#3087=PLANE('',#3086);
#3088=ORIENTED_EDGE('',*,*,#2959,.T.);
#3089=ORIENTED_EDGE('',*,*,#3077,.T.);
#3090=ORIENTED_EDGE('',*,*,#3055,.T.);
#3091=ORIENTED_EDGE('',*,*,#3031,.T.);
#3092=ORIENTED_EDGE('',*,*,#3007,.T.);
#3093=ORIENTED_EDGE('',*,*,#2983,.T.);
#3094=EDGE_LOOP('',(#3088,#3089,#3090,#3091,#3092,#3093));
#3095=FACE_BOUND('',#3094,.T.);
#3096=ADVANCED_FACE('F1174',(#3095),#3087,.T.);
#3097=CARTESIAN_POINT('',(-17.9567610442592,65.405,14.9001950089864));
#3098=DIRECTION('',(-0.866025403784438,0.,-0.500000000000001));
#3099=DIRECTION('',(-0.500000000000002,0.,0.866025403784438));
#3100=AXIS2_PLACEMENT_3D('',#3097,#3098,#3099);
#3101=PLANE('',#3100);
#3102=ORIENTED_EDGE('',*,*,#2809,.T.);
#3103=DIRECTION('',(0.,1.,0.));
#3104=VECTOR('',#3103,1.);
#3105=CARTESIAN_POINT('',(-19.0755418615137,65.405,16.8379802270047));
#3106=LINE('',#3105,#3104);
#3107=CARTESIAN_POINT('',(-19.0755418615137,65.405,16.8379802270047));
#3108=VERTEX_POINT('',#3107);
#3109=EDGE_CURVE('E463',#3108,#2808,#3106,.T.);
#3110=ORIENTED_EDGE('',*,*,#3109,.F.);
#3111=DIRECTION('',(-0.500000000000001,0.,0.866025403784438));
#3112=VECTOR('',#3111,1.);
#3113=CARTESIAN_POINT('',(-17.9567610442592,65.405,14.9001950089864));
#3114=LINE('',#3113,#3112);
#3115=CARTESIAN_POINT('',(-17.9567610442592,65.405,14.9001950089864));
#3116=VERTEX_POINT('',#3115);
#3117=EDGE_CURVE('E444',#3116,#3108,#3114,.T.);
#3118=ORIENTED_EDGE('',*,*,#3117,.F.);
#3119=DIRECTION('',(0.,1.,0.));
#3120=VECTOR('',#3119,1.);
#3121=CARTESIAN_POINT('',(-17.9567610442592,65.405,14.9001950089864));
#3122=LINE('',#3121,#3120);
#3123=EDGE_CURVE('E479',#3116,#2806,#3122,.T.);
#3124=ORIENTED_EDGE('',*,*,#3123,.T.);
#3125=EDGE_LOOP('',(#3102,#3110,#3118,#3124));
#3126=FACE_BOUND('',#3125,.T.);
#3127=ADVANCED_FACE('F1156',(#3126),#3101,.F.);
#3128=CARTESIAN_POINT('',(-15.7191994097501,65.405,14.9001950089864));
#3129=DIRECTION('',(0.,0.,-1.));
#3130=DIRECTION('',(-1.,0.,0.));
#3131=AXIS2_PLACEMENT_3D('',#3128,#3129,#3130);
#3132=PLANE('',#3131);
#3133=ORIENTED_EDGE('',*,*,#2817,.T.);
#3134=ORIENTED_EDGE('',*,*,#3123,.F.);
#3135=DIRECTION('',(-1.,0.,0.));
#3136=VECTOR('',#3135,1.);
#3137=CARTESIAN_POINT('',(-15.7191994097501,65.405,14.9001950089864));
#3138=LINE('',#3137,#3136);
#3139=CARTESIAN_POINT('',(-15.7191994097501,65.405,14.9001950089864));
#3140=VERTEX_POINT('',#3139);
#3141=EDGE_CURVE('E460',#3140,#3116,#3138,.T.);
#3142=ORIENTED_EDGE('',*,*,#3141,.F.);
#3143=DIRECTION('',(0.,1.,0.));
#3144=VECTOR('',#3143,1.);
#3145=CARTESIAN_POINT('',(-15.7191994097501,65.405,14.9001950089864));
#3146=LINE('',#3145,#3144);
#3147=EDGE_CURVE('E482',#3140,#2816,#3146,.T.);
#3148=ORIENTED_EDGE('',*,*,#3147,.T.);
#3149=EDGE_LOOP('',(#3133,#3134,#3142,#3148));
#3150=FACE_BOUND('',#3149,.T.);
#3151=ADVANCED_FACE('F1152',(#3150),#3132,.F.);
#3152=CARTESIAN_POINT('',(-14.6004185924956,65.405,16.8379802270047));
#3153=DIRECTION('',(0.866025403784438,0.,-0.500000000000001));
#3154=DIRECTION('',(-0.500000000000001,0.,-0.866025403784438));
#3155=AXIS2_PLACEMENT_3D('',#3152,#3153,#3154);
#3156=PLANE('',#3155);
#3157=ORIENTED_EDGE('',*,*,#2825,.T.);
#3158=ORIENTED_EDGE('',*,*,#3147,.F.);
#3159=DIRECTION('',(-0.500000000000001,0.,-0.866025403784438));
#3160=VECTOR('',#3159,1.);
#3161=CARTESIAN_POINT('',(-14.6004185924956,65.405,16.8379802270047));
#3162=LINE('',#3161,#3160);
#3163=CARTESIAN_POINT('',(-14.6004185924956,65.405,16.8379802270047));
#3164=VERTEX_POINT('',#3163);
#3165=EDGE_CURVE('E457',#3164,#3140,#3162,.T.);
#3166=ORIENTED_EDGE('',*,*,#3165,.F.);
#3167=DIRECTION('',(0.,1.,0.));
#3168=VECTOR('',#3167,1.);
#3169=CARTESIAN_POINT('',(-14.6004185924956,65.405,16.8379802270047));
#3170=LINE('',#3169,#3168);
#3171=EDGE_CURVE('E484',#3164,#2824,#3170,.T.);
#3172=ORIENTED_EDGE('',*,*,#3171,.T.);
#3173=EDGE_LOOP('',(#3157,#3158,#3166,#3172));
#3174=FACE_BOUND('',#3173,.T.);
#3175=ADVANCED_FACE('F1155',(#3174),#3156,.F.);
#3176=CARTESIAN_POINT('',(-15.7191994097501,65.405,18.775765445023));
#3177=DIRECTION('',(0.866025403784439,0.,0.5));
#3178=DIRECTION('',(0.5,0.,-0.866025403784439));
#3179=AXIS2_PLACEMENT_3D('',#3176,#3177,#3178);
#3180=PLANE('',#3179);
#3181=ORIENTED_EDGE('',*,*,#2833,.T.);
#3182=ORIENTED_EDGE('',*,*,#3171,.F.);
#3183=DIRECTION('',(0.5,0.,-0.866025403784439));
#3184=VECTOR('',#3183,1.);
#3185=CARTESIAN_POINT('',(-15.7191994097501,65.405,18.775765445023));
#3186=LINE('',#3185,#3184);
#3187=CARTESIAN_POINT('',(-15.7191994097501,65.405,18.775765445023));
#3188=VERTEX_POINT('',#3187);
#3189=EDGE_CURVE('E454',#3188,#3164,#3186,.T.);
#3190=ORIENTED_EDGE('',*,*,#3189,.F.);
#3191=DIRECTION('',(0.,1.,0.));
#3192=VECTOR('',#3191,1.);
#3193=CARTESIAN_POINT('',(-15.7191994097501,65.405,18.775765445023));
#3194=LINE('',#3193,#3192);
#3195=EDGE_CURVE('E486',#3188,#2832,#3194,.T.);
#3196=ORIENTED_EDGE('',*,*,#3195,.T.);
#3197=EDGE_LOOP('',(#3181,#3182,#3190,#3196));
#3198=FACE_BOUND('',#3197,.T.);
#3199=ADVANCED_FACE('F1160',(#3198),#3180,.F.);
#3200=CARTESIAN_POINT('',(-17.9567610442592,65.405,18.775765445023));
#3201=DIRECTION('',(0.,0.,1.));
#3202=DIRECTION('',(1.,0.,0.));
#3203=AXIS2_PLACEMENT_3D('',#3200,#3201,#3202);
#3204=PLANE('',#3203);
#3205=ORIENTED_EDGE('',*,*,#2841,.T.);
#3206=ORIENTED_EDGE('',*,*,#3195,.F.);
#3207=DIRECTION('',(1.,0.,0.));
#3208=VECTOR('',#3207,1.);
#3209=CARTESIAN_POINT('',(-17.9567610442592,65.405,18.775765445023));
#3210=LINE('',#3209,#3208);
#3211=CARTESIAN_POINT('',(-17.9567610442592,65.405,18.775765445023));
#3212=VERTEX_POINT('',#3211);
#3213=EDGE_CURVE('E451',#3212,#3188,#3210,.T.);
#3214=ORIENTED_EDGE('',*,*,#3213,.F.);
#3215=DIRECTION('',(0.,1.,0.));
#3216=VECTOR('',#3215,1.);
#3217=CARTESIAN_POINT('',(-17.9567610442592,65.405,18.775765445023));
#3218=LINE('',#3217,#3216);
#3219=EDGE_CURVE('E488',#3212,#2840,#3218,.T.);
#3220=ORIENTED_EDGE('',*,*,#3219,.T.);
#3221=EDGE_LOOP('',(#3205,#3206,#3214,#3220));
#3222=FACE_BOUND('',#3221,.T.);
#3223=ADVANCED_FACE('F1164',(#3222),#3204,.F.);
#3224=CARTESIAN_POINT('',(-19.0755418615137,65.405,16.8379802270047));
#3225=DIRECTION('',(-0.866025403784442,0.,0.499999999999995));
#3226=DIRECTION('',(0.499999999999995,0.,0.866025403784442));
#3227=AXIS2_PLACEMENT_3D('',#3224,#3225,#3226);
#3228=PLANE('',#3227);
#3229=ORIENTED_EDGE('',*,*,#2847,.T.);
#3230=ORIENTED_EDGE('',*,*,#3219,.F.);
#3231=DIRECTION('',(0.499999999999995,0.,0.866025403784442));
#3232=VECTOR('',#3231,1.);
#3233=CARTESIAN_POINT('',(-19.0755418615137,65.405,16.8379802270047));
#3234=LINE('',#3233,#3232);
#3235=EDGE_CURVE('E447',#3108,#3212,#3234,.T.);
#3236=ORIENTED_EDGE('',*,*,#3235,.F.);
#3237=ORIENTED_EDGE('',*,*,#3109,.T.);
#3238=EDGE_LOOP('',(#3229,#3230,#3236,#3237));
#3239=FACE_BOUND('',#3238,.T.);
#3240=ADVANCED_FACE('F1150',(#3239),#3228,.F.);
#3241=CARTESIAN_POINT('',(-19.0755418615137,65.405,16.8379802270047));
#3242=DIRECTION('',(0.,1.,0.));
#3243=DIRECTION('',(0.,0.,-1.));
#3244=AXIS2_PLACEMENT_3D('',#3241,#3242,#3243);
#3245=PLANE('',#3244);
#3246=ORIENTED_EDGE('',*,*,#3117,.T.);
#3247=ORIENTED_EDGE('',*,*,#3235,.T.);
#3248=ORIENTED_EDGE('',*,*,#3213,.T.);
#3249=ORIENTED_EDGE('',*,*,#3189,.T.);
#3250=ORIENTED_EDGE('',*,*,#3165,.T.);
#3251=ORIENTED_EDGE('',*,*,#3141,.T.);
#3252=EDGE_LOOP('',(#3246,#3247,#3248,#3249,#3250,#3251));
#3253=FACE_BOUND('',#3252,.T.);
#3254=ADVANCED_FACE('F1138',(#3253),#3245,.T.);
#3255=CARTESIAN_POINT('',(-14.9001950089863,65.405,-17.9567610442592));
#3256=DIRECTION('',(0.500000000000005,0.,-0.866025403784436));
#3257=DIRECTION('',(-0.866025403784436,0.,-0.500000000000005));
#3258=AXIS2_PLACEMENT_3D('',#3255,#3256,#3257);
#3259=PLANE('',#3258);
#3260=ORIENTED_EDGE('',*,*,#2896,.T.);
#3261=DIRECTION('',(0.,1.,0.));
#3262=VECTOR('',#3261,1.);
#3263=CARTESIAN_POINT('',(-16.8379802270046,65.405,-19.0755418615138));
#3264=LINE('',#3263,#3262);
#3265=CARTESIAN_POINT('',(-16.8379802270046,65.405,-19.0755418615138));
#3266=VERTEX_POINT('',#3265);
#3267=EDGE_CURVE('E388',#3266,#2895,#3264,.T.);
#3268=ORIENTED_EDGE('',*,*,#3267,.F.);
#3269=DIRECTION('',(-0.866025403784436,0.,-0.500000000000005));
#3270=VECTOR('',#3269,1.);
#3271=CARTESIAN_POINT('',(-14.9001950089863,65.405,-17.9567610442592));
#3272=LINE('',#3271,#3270);
#3273=CARTESIAN_POINT('',(-14.9001950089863,65.405,-17.9567610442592));
#3274=VERTEX_POINT('',#3273);
#3275=EDGE_CURVE('E392',#3274,#3266,#3272,.T.);
#3276=ORIENTED_EDGE('',*,*,#3275,.F.);
#3277=DIRECTION('',(0.,1.,0.));
#3278=VECTOR('',#3277,1.);
#3279=CARTESIAN_POINT('',(-14.9001950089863,65.405,-17.9567610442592));
#3280=LINE('',#3279,#3278);
#3281=EDGE_CURVE('E435',#3274,#2893,#3280,.T.);
#3282=ORIENTED_EDGE('',*,*,#3281,.T.);
#3283=EDGE_LOOP('',(#3260,#3268,#3276,#3282));
#3284=FACE_BOUND('',#3283,.T.);
#3285=ADVANCED_FACE('F390',(#3284),#3259,.F.);
#3286=CARTESIAN_POINT('',(-14.9001950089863,65.405,-15.7191994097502));
#3287=DIRECTION('',(1.,0.,0.));
#3288=DIRECTION('',(0.,0.,-1.));
#3289=AXIS2_PLACEMENT_3D('',#3286,#3287,#3288);
#3290=PLANE('',#3289);
#3291=ORIENTED_EDGE('',*,*,#2904,.T.);
#3292=ORIENTED_EDGE('',*,*,#3281,.F.);
#3293=DIRECTION('',(0.,0.,-1.));
#3294=VECTOR('',#3293,1.);
#3295=CARTESIAN_POINT('',(-14.9001950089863,65.405,-15.7191994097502));
#3296=LINE('',#3295,#3294);
#3297=CARTESIAN_POINT('',(-14.9001950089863,65.405,-15.7191994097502));
#3298=VERTEX_POINT('',#3297);
#3299=EDGE_CURVE('E398',#3298,#3274,#3296,.T.);
#3300=ORIENTED_EDGE('',*,*,#3299,.F.);
#3301=DIRECTION('',(0.,1.,0.));
#3302=VECTOR('',#3301,1.);
#3303=CARTESIAN_POINT('',(-14.9001950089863,65.405,-15.7191994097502));
#3304=LINE('',#3303,#3302);
#3305=EDGE_CURVE('E437',#3298,#2903,#3304,.T.);
#3306=ORIENTED_EDGE('',*,*,#3305,.T.);
#3307=EDGE_LOOP('',(#3291,#3292,#3300,#3306));
#3308=FACE_BOUND('',#3307,.T.);
#3309=ADVANCED_FACE('F1130',(#3308),#3290,.F.);
#3310=CARTESIAN_POINT('',(-16.8379802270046,65.405,-14.6004185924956));
#3311=DIRECTION('',(0.499999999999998,0.,0.86602540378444));
#3312=DIRECTION('',(0.86602540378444,0.,-0.499999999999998));
#3313=AXIS2_PLACEMENT_3D('',#3310,#3311,#3312);
#3314=PLANE('',#3313);
#3315=ORIENTED_EDGE('',*,*,#2912,.T.);
#3316=ORIENTED_EDGE('',*,*,#3305,.F.);
#3317=DIRECTION('',(0.86602540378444,0.,-0.499999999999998));
#3318=VECTOR('',#3317,1.);
#3319=CARTESIAN_POINT('',(-16.8379802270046,65.405,-14.6004185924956));
#3320=LINE('',#3319,#3318);
#3321=CARTESIAN_POINT('',(-16.8379802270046,65.405,-14.6004185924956));
#3322=VERTEX_POINT('',#3321);
#3323=EDGE_CURVE('E421',#3322,#3298,#3320,.T.);
#3324=ORIENTED_EDGE('',*,*,#3323,.F.);
#3325=DIRECTION('',(0.,1.,0.));
#3326=VECTOR('',#3325,1.);
#3327=CARTESIAN_POINT('',(-16.8379802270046,65.405,-14.6004185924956));
#3328=LINE('',#3327,#3326);
#3329=EDGE_CURVE('E439',#3322,#2911,#3328,.T.);
#3330=ORIENTED_EDGE('',*,*,#3329,.T.);
#3331=EDGE_LOOP('',(#3315,#3316,#3324,#3330));
#3332=FACE_BOUND('',#3331,.T.);
#3333=ADVANCED_FACE('F1128',(#3332),#3314,.F.);
#3334=CARTESIAN_POINT('',(-18.7757654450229,65.405,-15.7191994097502));
#3335=DIRECTION('',(-0.500000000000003,0.,0.866025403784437));
#3336=DIRECTION('',(0.866025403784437,0.,0.500000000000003));
#3337=AXIS2_PLACEMENT_3D('',#3334,#3335,#3336);
#3338=PLANE('',#3337);
#3339=ORIENTED_EDGE('',*,*,#2920,.T.);
#3340=ORIENTED_EDGE('',*,*,#3329,.F.);
#3341=DIRECTION('',(0.866025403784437,0.,0.500000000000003));
#3342=VECTOR('',#3341,1.);
#3343=CARTESIAN_POINT('',(-18.7757654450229,65.405,-15.7191994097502));
#3344=LINE('',#3343,#3342);
#3345=CARTESIAN_POINT('',(-18.7757654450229,65.405,-15.7191994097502));
#3346=VERTEX_POINT('',#3345);
#3347=EDGE_CURVE('E418',#3346,#3322,#3344,.T.);
#3348=ORIENTED_EDGE('',*,*,#3347,.F.);
#3349=DIRECTION('',(0.,1.,0.));
#3350=VECTOR('',#3349,1.);
#3351=CARTESIAN_POINT('',(-18.7757654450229,65.405,-15.7191994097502));
#3352=LINE('',#3351,#3350);
#3353=EDGE_CURVE('E441',#3346,#2919,#3352,.T.);
#3354=ORIENTED_EDGE('',*,*,#3353,.T.);
#3355=EDGE_LOOP('',(#3339,#3340,#3348,#3354));
#3356=FACE_BOUND('',#3355,.T.);
#3357=ADVANCED_FACE('F1126',(#3356),#3338,.F.);
#3358=CARTESIAN_POINT('',(-18.7757654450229,65.405,-17.9567610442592));
#3359=DIRECTION('',(-1.,0.,0.));
#3360=DIRECTION('',(0.,0.,1.));
#3361=AXIS2_PLACEMENT_3D('',#3358,#3359,#3360);
#3362=PLANE('',#3361);
#3363=ORIENTED_EDGE('',*,*,#2928,.T.);
#3364=ORIENTED_EDGE('',*,*,#3353,.F.);
#3365=DIRECTION('',(0.,0.,1.));
#3366=VECTOR('',#3365,1.);
#3367=CARTESIAN_POINT('',(-18.7757654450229,65.405,-17.9567610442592));
#3368=LINE('',#3367,#3366);
#3369=CARTESIAN_POINT('',(-18.7757654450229,65.405,-17.9567610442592));
#3370=VERTEX_POINT('',#3369);
#3371=EDGE_CURVE('E406',#3370,#3346,#3368,.T.);
#3372=ORIENTED_EDGE('',*,*,#3371,.F.);
#3373=DIRECTION('',(0.,1.,0.));
#3374=VECTOR('',#3373,1.);
#3375=CARTESIAN_POINT('',(-18.7757654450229,65.405,-17.9567610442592));
#3376=LINE('',#3375,#3374);
#3377=EDGE_CURVE('E397',#3370,#2927,#3376,.T.);
#3378=ORIENTED_EDGE('',*,*,#3377,.T.);
#3379=EDGE_LOOP('',(#3363,#3364,#3372,#3378));
#3380=FACE_BOUND('',#3379,.T.);
#3381=ADVANCED_FACE('F1122',(#3380),#3362,.F.);
#3382=CARTESIAN_POINT('',(-16.8379802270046,65.405,-19.0755418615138));
#3383=DIRECTION('',(-0.499999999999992,0.,-0.866025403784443));
#3384=DIRECTION('',(-0.866025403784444,0.,0.499999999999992));
#3385=AXIS2_PLACEMENT_3D('',#3382,#3383,#3384);
#3386=PLANE('',#3385);
#3387=ORIENTED_EDGE('',*,*,#2934,.T.);
#3388=ORIENTED_EDGE('',*,*,#3377,.F.);
#3389=DIRECTION('',(-0.866025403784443,0.,0.499999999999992));
#3390=VECTOR('',#3389,1.);
#3391=CARTESIAN_POINT('',(-16.8379802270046,65.405,-19.0755418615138));
#3392=LINE('',#3391,#3390);
#3393=EDGE_CURVE('E401',#3266,#3370,#3392,.T.);
#3394=ORIENTED_EDGE('',*,*,#3393,.F.);
#3395=ORIENTED_EDGE('',*,*,#3267,.T.);
#3396=EDGE_LOOP('',(#3387,#3388,#3394,#3395));
#3397=FACE_BOUND('',#3396,.T.);
#3398=ADVANCED_FACE('F402',(#3397),#3386,.F.);
#3399=CARTESIAN_POINT('',(-16.8379802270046,65.405,-19.0755418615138));
#3400=DIRECTION('',(0.,1.,0.));
#3401=DIRECTION('',(1.,0.,0.));
#3402=AXIS2_PLACEMENT_3D('',#3399,#3400,#3401);
#3403=PLANE('',#3402);
#3404=ORIENTED_EDGE('',*,*,#3275,.T.);
#3405=ORIENTED_EDGE('',*,*,#3393,.T.);
#3406=ORIENTED_EDGE('',*,*,#3371,.T.);
#3407=ORIENTED_EDGE('',*,*,#3347,.T.);
#3408=ORIENTED_EDGE('',*,*,#3323,.T.);
#3409=ORIENTED_EDGE('',*,*,#3299,.T.);
#3410=EDGE_LOOP('',(#3404,#3405,#3406,#3407,#3408,#3409));
#3411=FACE_BOUND('',#3410,.T.);
#3412=ADVANCED_FACE('F408',(#3411),#3403,.T.);
#3413=CARTESIAN_POINT('',(16.8379802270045,68.58,-16.8379802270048));
#3414=DIRECTION('',(0.,-1.,0.));
#3415=DIRECTION('',(0.,0.,-1.));
#3416=AXIS2_PLACEMENT_3D('',#3413,#3414,#3415);
#3417=CONICAL_SURFACE('',#3416,3.58139999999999,0.785398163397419);
#3418=ORIENTED_EDGE('',*,*,#2445,.F.);
#3419=EDGE_LOOP('',(#3418));
#3420=FACE_BOUND('',#3419,.T.);
#3421=ORIENTED_EDGE('',*,*,#2465,.F.);
#3422=EDGE_LOOP('',(#3421));
#3423=FACE_BOUND('',#3422,.T.);
#3424=ADVANCED_FACE('F1078',(#3420,#3423),#3417,.T.);
#3425=CARTESIAN_POINT('',(16.8379802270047,68.58,16.8379802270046));
#3426=DIRECTION('',(0.,-1.,0.));
#3427=DIRECTION('',(0.,0.,-1.));
#3428=AXIS2_PLACEMENT_3D('',#3425,#3426,#3427);
#3429=CONICAL_SURFACE('',#3428,3.58139999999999,0.785398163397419);
#3430=ORIENTED_EDGE('',*,*,#2690,.F.);
#3431=EDGE_LOOP('',(#3430));
#3432=FACE_BOUND('',#3431,.T.);
#3433=ORIENTED_EDGE('',*,*,#2710,.F.);
#3434=EDGE_LOOP('',(#3433));
#3435=FACE_BOUND('',#3434,.T.);
#3436=ADVANCED_FACE('F1081',(#3432,#3435),#3429,.T.);
#3437=CARTESIAN_POINT('',(-16.8379802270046,68.58,16.8379802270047));
#3438=DIRECTION('',(0.,-1.,0.));
#3439=DIRECTION('',(0.,0.,-1.));
#3440=AXIS2_PLACEMENT_3D('',#3437,#3438,#3439);
#3441=CONICAL_SURFACE('',#3440,3.58139999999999,0.785398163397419);
#3442=ORIENTED_EDGE('',*,*,#2777,.F.);
#3443=EDGE_LOOP('',(#3442));
#3444=FACE_BOUND('',#3443,.T.);
#3445=ORIENTED_EDGE('',*,*,#2797,.F.);
#3446=EDGE_LOOP('',(#3445));
#3447=FACE_BOUND('',#3446,.T.);
#3448=ADVANCED_FACE('F1084',(#3444,#3447),#3441,.T.);
#3449=CARTESIAN_POINT('',(-16.8379802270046,68.58,-16.8379802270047));
#3450=DIRECTION('',(0.,-1.,0.));
#3451=DIRECTION('',(0.,0.,-1.));
#3452=AXIS2_PLACEMENT_3D('',#3449,#3450,#3451);
#3453=CONICAL_SURFACE('',#3452,3.58139999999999,0.785398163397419);
#3454=ORIENTED_EDGE('',*,*,#2864,.F.);
#3455=EDGE_LOOP('',(#3454));
#3456=FACE_BOUND('',#3455,.T.);
#3457=ORIENTED_EDGE('',*,*,#2884,.F.);
#3458=EDGE_LOOP('',(#3457));
#3459=FACE_BOUND('',#3458,.T.);
#3460=ADVANCED_FACE('F33',(#3456,#3459),#3453,.T.);
#3461=CLOSED_SHELL('',(#674,#1024,#1041,#1061,#1081,#1101,#1119,#1139,#1167,#1187,#1207,#1228,
#1248,#1260,#1280,#1301,#1321,#1333,#1345,#1357,#1377,#1430,#1510,#1542,#1566,#1591,#1608,#1620,
#1636,#1685,#1701,#1750,#1766,#1815,#1831,#1880,#1938,#1960,#1977,#1994,#2006,#2018,#2076,#2098,
#2115,#2132,#2144,#2156,#2214,#2236,#2253,#2270,#2282,#2294,#2352,#2374,#2391,#2408,#2420,#2432,
#2452,#2519,#2550,#2574,#2598,#2622,#2646,#2663,#2677,#2697,#2764,#2784,#2851,#2871,#2938,#2969,
#2993,#3017,#3041,#3065,#3082,#3096,#3127,#3151,#3175,#3199,#3223,#3240,#3254,#3285,#3309,#3333,
#3357,#3381,#3398,#3412,#3424,#3436,#3448,#3460));
#3462=MANIFOLD_SOLID_BREP('B2',#3461);
#3463=ADVANCED_BREP_SHAPE_REPRESENTATION('',(#18,#3462),#14);
#3464=SHAPE_DEFINITION_REPRESENTATION(#9,#3463);
ENDSEC;
END-ISO-10303-21;
